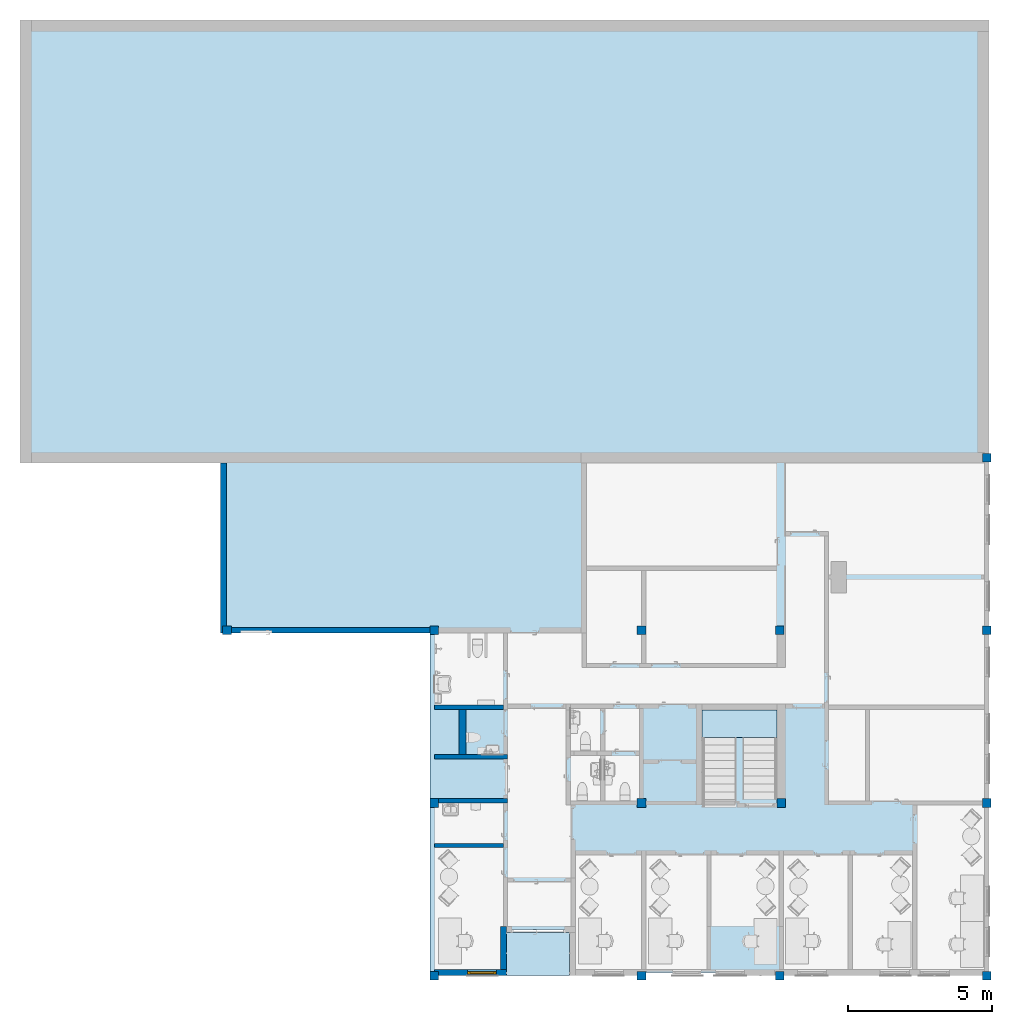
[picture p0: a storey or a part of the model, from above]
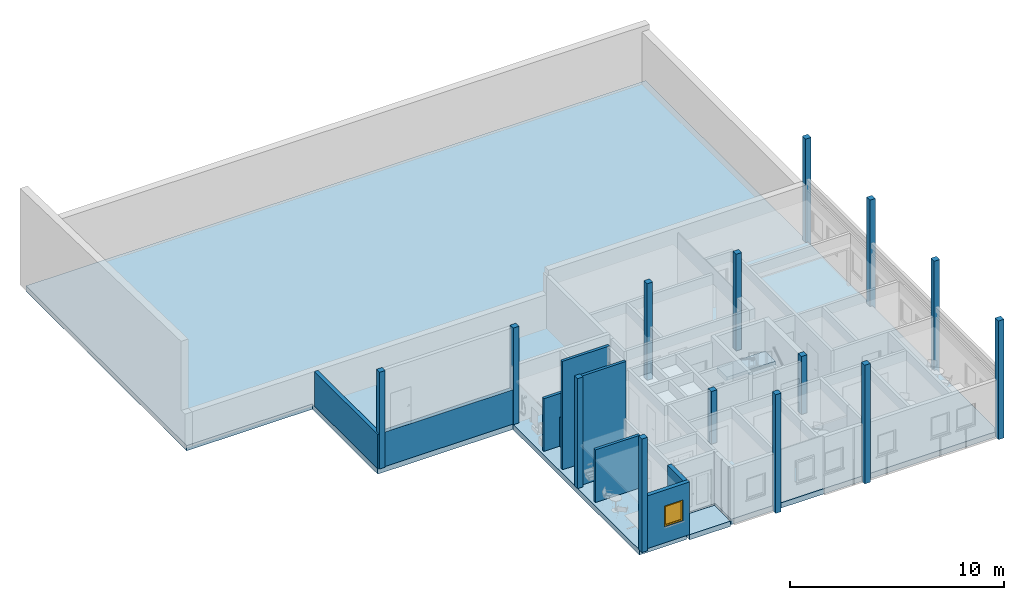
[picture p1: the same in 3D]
Properties of the parts of a building model (IFC2X3), part 1 of 4

# File
Description: ViewDefinition [CoordinationView_V2.0], RevitIdentifiers [ContentGUID: , VersionGUID: c2dd3010-3e74-4256-bd05-e16716eef5d8, NumberOfSaves: 1689], ExchangeRequirement [], CoordinateReference [CoordinateBase: Project Base Point, ProjectSite: Internal]
File name: A-200-00-ARK_TLV.ifc
Time: 2025-12-17T15:34:03+01:00
Organization: Arkitema
Written by: ODA SDAI 22.12
Made in: Autodesk Revit 23.1.80.30 (ENU) - IFC 23.4.1.0

# IfcProject, A271908
LongName: TROMSØ LEGEVAKT; Phase: SKISSEPROSJEKT

# IfcSite, Default
RefLatitude: 59, 54, 57, 599999; RefLongitude: 10, 44, 59, 999999; RefElevation: 0 mm

# IfcSite: Coordinate Marker Primary:Architect, Coordinate Marker Primary:Architect:1420675
Material: A_Coordinate Marker_ARC

# IfcBuilding
Pset_BuildingCommon - NumberOfStoreys: 8

# IfcBuildingStorey: Level:Trekant (8)
Pset_AirSideSystemInformation - sets with these values: 2
Name | LongName = Name | Elevation (mm)
OPPSTILLING | OPPSTILLING | -50000 | Pset_BuildingStoreyCommon - EntranceLevel: no
HAV | HAV | 6.71378e-11 | Pset_BuildingStoreyCommon - EntranceLevel: yes
PLAN U1 | PLAN U1 | 31140
PLAN 01 | PLAN 01 | 33100 | Pset_BuildingStoreyCommon - EntranceLevel: yes
PLAN 02 | PLAN 02 | 34440
TEKNISK SKILLE | TEKNISK SKILLE | 36090
PLAN 03 (EKS. TAK) | PLAN 03 (EKS. TAK) | 37100
PLAN 04 (TAK) | PLAN 04 (TAK) | 42000

# IfcSpace: Akuttrom 01 B4-407:1695459, B4-407
In: PLAN 01
LongName: Akuttrom 01; InteriorOrExteriorSpace: INTERNAL
Pset_AirSideSystemInformation - Name: Akuttrom 01; sets with these values: 2
Pset_SpaceCommon - Reference: Akuttrom 01 B4-407; FloorCovering: Vinyl, Halvledende; WallCovering: Baderomsplater; CeilingCovering: Perforert gipshimling

# IfcSpace: Akuttrom 02 B4-408:1695458, B4-408
In: PLAN 01
LongName: Akuttrom 02; InteriorOrExteriorSpace: INTERNAL
Pset_AirSideSystemInformation - Name: Akuttrom 02; sets with these values: 2
Pset_SpaceCommon - Reference: Akuttrom 02 B4-408; FloorCovering: Vinyl, Halvledende; WallCovering: Malt Gips; CeilingCovering: Systemhimling. hygiene

# IfcSpace: Ambulanse garasje B4-408A:1717682, B4-408A
In: PLAN 01
LongName: Ambulanse garasje; InteriorOrExteriorSpace: INTERNAL
Pset_AirSideSystemInformation - Name: Ambulanse garasje; sets with these values: 2
Pset_SpaceCommon - Reference: Ambulanse garasje B4-408A; FloorCovering: Epoxy / kjøresterk overflate; WallCovering: Platekledning; CeilingCovering: Støvbundet betong

# IfcSpace: Auditorie B5-306:1706835, B5-306
In: PLAN U1
LongName: Auditorie; InteriorOrExteriorSpace: INTERNAL
Pset_AirSideSystemInformation - Name: Auditorie; sets with these values: 2
Pset_SpaceCommon - Reference: Auditorie B5-306

# IfcSpace: Avfall 409:1706508, 409
In: PLAN 01
LongName: Avfall; InteriorOrExteriorSpace: INTERNAL
Pset_AirSideSystemInformation - Name: Avfall; sets with these values: 2
Pset_SpaceCommon - Reference: Avfall 409; FloorCovering: Epoxy; WallCovering: Malt Betong, våtromsmaling; CeilingCovering: Malt betong

# IfcSpace: Avklaringsrom B4-401:1695460, B4-401
In: PLAN 01
LongName: Avklaringsrom; InteriorOrExteriorSpace: INTERNAL
Pset_AirSideSystemInformation - Name: Avklaringsrom; sets with these values: 2
Pset_SpaceCommon - Reference: Avklaringsrom B4-401; FloorCovering: Vinyl; WallCovering: Malt Gips; CeilingCovering: Systemhimling. hygiene

# IfcSpace: BK. B5-302:1801416, B5-302
In: PLAN U1
LongName: BK.; InteriorOrExteriorSpace: INTERNAL
Pset_AirSideSystemInformation - Name: BK.; sets with these values: 2
Pset_SpaceCommon - Reference: BK. B5-302

# IfcSpace: BK. B5-413:1701542, B5-413
In: PLAN 02
LongName: BK.; InteriorOrExteriorSpace: INTERNAL
Pset_AirSideSystemInformation - Name: BK.; sets with these values: 2
Pset_SpaceCommon - Reference: BK. B5-413; FloorCovering: Vinyl; WallCovering: Malt Gips; CeilingCovering: Fast himling - våtromsmaling

# IfcSpace: Damegarderobe B5-421:2713467, B5-421
In: PLAN 02
LongName: Damegarderobe; InteriorOrExteriorSpace: INTERNAL
Pset_AirSideSystemInformation - Name: Damegarderobe; sets with these values: 2
Pset_SpaceCommon - Reference: Damegarderobe B5-421; FloorCovering: Vinyl; WallCovering: Malt Gips; CeilingCovering: Fast himling - våtromsmaling

# IfcSpace: Dusj B5-420B:2713472, B5-420B
In: PLAN 02
LongName: Dusj; InteriorOrExteriorSpace: INTERNAL
Pset_AirSideSystemInformation - Name: Dusj; sets with these values: 2
Pset_SpaceCommon - Reference: Dusj B5-420B; FloorCovering: Sklisikker Vinyl; WallCovering: Baderomsplater; CeilingCovering: Fast himling - våtromsmaling

# IfcSpace: Dusj B5-421B:2713502, B5-421B
In: PLAN 02
LongName: Dusj; InteriorOrExteriorSpace: INTERNAL
Pset_AirSideSystemInformation - Name: Dusj; sets with these values: 2
Pset_SpaceCommon - Reference: Dusj B5-421B; FloorCovering: Sklisikker Vinyl; WallCovering: Baderomsplater; CeilingCovering: Fast himling - våtromsmaling

# IfcSpace: EL Tavle B4-416A:1695467, B4-416A
In: PLAN 01
LongName: EL Tavle; InteriorOrExteriorSpace: INTERNAL
Pset_AirSideSystemInformation - Name: EL Tavle; sets with these values: 2
Pset_SpaceCommon - Reference: EL Tavle B4-416A

# IfcSpace: EL Tavle B5-309:1801423, B5-309
In: PLAN U1
LongName: EL Tavle; InteriorOrExteriorSpace: INTERNAL
Pset_AirSideSystemInformation - Name: EL Tavle; sets with these values: 2
Pset_SpaceCommon - Reference: EL Tavle B5-309

# IfcSpace: EL Tavle B5-312:1801425, B5-312
In: PLAN U1
LongName: EL Tavle; InteriorOrExteriorSpace: INTERNAL
Pset_AirSideSystemInformation - Name: EL Tavle; sets with these values: 2
Pset_SpaceCommon - Reference: EL Tavle B5-312

# IfcSpace: EL Tavle og UPS B4-414:1695468, B4-414
In: PLAN 01
LongName: EL Tavle og UPS; InteriorOrExteriorSpace: INTERNAL
Pset_AirSideSystemInformation - Name: EL Tavle og UPS; sets with these values: 2
Pset_SpaceCommon - Reference: EL Tavle og UPS B4-414; FloorCovering: Vinyl; WallCovering: Malt Gips; CeilingCovering: Systemhimling

# IfcSpace: Ekspedisjon/Sluse B4-425:2043666, B4-425
In: PLAN 01
LongName: Ekspedisjon/Sluse; InteriorOrExteriorSpace: INTERNAL
Pset_AirSideSystemInformation - Name: Ekspedisjon/Sluse; sets with these values: 2
Pset_SpaceCommon - Reference: Ekspedisjon/Sluse B4-425; FloorCovering: Vinyl; WallCovering: Malt Gips; CeilingCovering: Systemhimling

# IfcSpace: Ekspedisjon/Triage B4-425C:1734509, B4-425C
In: PLAN 01
LongName: Ekspedisjon/Triage; InteriorOrExteriorSpace: INTERNAL
Pset_AirSideSystemInformation - Name: Ekspedisjon/Triage; sets with these values: 2
Pset_SpaceCommon - Reference: Ekspedisjon/Triage B4-425C; FloorCovering: Vinyl; WallCovering: Malt Gips; CeilingCovering: Systemhimling

# IfcSpace: Felles Pauserom B5-422:1701539, B5-422
In: PLAN 02
LongName: Felles Pauserom; InteriorOrExteriorSpace: INTERNAL
Pset_AirSideSystemInformation - Name: Felles Pauserom; sets with these values: 2
Pset_SpaceCommon - Reference: Felles Pauserom B5-422; FloorCovering: Vinyl m trinnlydsdemping; WallCovering: Malt Gips; CeilingCovering: Treullsementplater montert UK dekke

# IfcSpace: Forrom B5-311:3232516, B5-311
In: PLAN U1
LongName: Forrom; InteriorOrExteriorSpace: INTERNAL
Pset_AirSideSystemInformation - Name: Forrom; sets with these values: 2
Pset_SpaceCommon - Reference: Forrom B5-311; FloorCovering: Vinyl; WallCovering: Malt Gips; CeilingCovering: Systemhimling

# IfcSpace: Forrom, smitte B5-409A:1837150, B5-409A
In: PLAN 01
LongName: Forrom, smitte; InteriorOrExteriorSpace: INTERNAL
Pset_AirSideSystemInformation - Name: Forrom, smitte; sets with these values: 2
Pset_SpaceCommon - Reference: Forrom, smitte B5-409A; FloorCovering: Vinyl; WallCovering: Malt Gips; CeilingCovering: Systemhimling. hygiene

# IfcSpace: Gang 410:1706509, 410
In: PLAN 01
LongName: Gang; InteriorOrExteriorSpace: INTERNAL
Pset_AirSideSystemInformation - Name: Gang; sets with these values: 2
Pset_SpaceCommon - Reference: Gang 410; FloorCovering: Vinyl; WallCovering: Malt Gips; CeilingCovering: Systemhimling

# IfcSpace: Gang:2708464
In: PLAN U1
LongName: Gang; InteriorOrExteriorSpace: INTERNAL
Pset_AirSideSystemInformation - Name: Gang; sets with these values: 2
Pset_SpaceCommon - Reference: Gang; FloorCovering: Nytt belegg i berørte områder (Vinyl); WallCovering: Males noe i berørte områder; CeilingCovering: Systemhimling tilpasses mot nye vegger

# IfcSpace: HC WC/dusj B4-411:1695466, B4-411
In: PLAN 01
LongName: HC WC/dusj; InteriorOrExteriorSpace: INTERNAL
Pset_AirSideSystemInformation - Name: HC WC/dusj; sets with these values: 2
Pset_SpaceCommon - Reference: HC WC/dusj B4-411; FloorCovering: Sklisikker Vinyl; WallCovering: Baderomsplater; CeilingCovering: Systemhimling. hygiene

# IfcSpace: HCWC B5-304:1805190, B5-304
In: PLAN U1
LongName: HCWC; InteriorOrExteriorSpace: INTERNAL
Pset_AirSideSystemInformation - Name: HCWC; sets with these values: 2
Pset_SpaceCommon - Reference: HCWC B5-304

# IfcSpace: HCWC/dusj B5-420:2713465, B5-420
In: PLAN 02
LongName: HCWC/dusj; InteriorOrExteriorSpace: INTERNAL
Pset_AirSideSystemInformation - Name: HCWC/dusj; sets with these values: 2
Pset_SpaceCommon - Reference: HCWC/dusj B5-420; FloorCovering: Sklisikker Vinyl; WallCovering: Baderomsplater; CeilingCovering: Fast himling - våtromsmaling

# IfcSpace: HCWC/stellerom B4-423:1697714, B4-423
In: PLAN 01
LongName: HCWC/stellerom; InteriorOrExteriorSpace: INTERNAL
Pset_AirSideSystemInformation - Name: HCWC/stellerom; sets with these values: 2
Pset_SpaceCommon - Reference: HCWC/stellerom B4-423; FloorCovering: Vinyl; WallCovering: Baderomsplater; CeilingCovering: Systemhimling

# IfcSpace: Heis 408:1706507, 408
In: PLAN 01
LongName: Heis; InteriorOrExteriorSpace: INTERNAL
Pset_AirSideSystemInformation - Name: Heis; sets with these values: 2
Pset_SpaceCommon - Reference: Heis 408

# IfcSpace: Herregarderobe B5-420:2713503, B5-420
In: PLAN 02
LongName: Herregarderobe; InteriorOrExteriorSpace: INTERNAL
Pset_AirSideSystemInformation - Name: Herregarderobe; sets with these values: 2
Pset_SpaceCommon - Reference: Herregarderobe B5-420; FloorCovering: Vinyl; WallCovering: Malt Gips; CeilingCovering: Fast himling - våtromsmaling

# IfcSpace: Hvilerom B5-405:2985970, B5-405
In: PLAN 02
LongName: Hvilerom; InteriorOrExteriorSpace: INTERNAL
Pset_AirSideSystemInformation - Name: Hvilerom; sets with these values: 2
Pset_SpaceCommon - Reference: Hvilerom B5-405; FloorCovering: Vinyl m trinnlydsdemping; WallCovering: Malt Gips; CeilingCovering: Systemhimling montert i UK. dekke

# IfcSpace: Interkommunal Legevaktsentral B5-421:1701530, B5-421
In: PLAN 02
LongName: Interkommunal Legevaktsentral; InteriorOrExteriorSpace: INTERNAL
Pset_AirSideSystemInformation - Name: Interkommunal Legevaktsentral; sets with these values: 2
Pset_SpaceCommon - Reference: Interkommunal Legevaktsentral B5-421; FloorCovering: Vinyl m trinnlydsdemping; WallCovering: Malt Gips; CeilingCovering: Treullsementplater montert UK dekke

# IfcSpace: Kontor B5-301:1801415, B5-301
In: PLAN U1
LongName: Kontor; InteriorOrExteriorSpace: INTERNAL
Pset_AirSideSystemInformation - Name: Kontor; sets with these values: 2
Pset_SpaceCommon - Reference: Kontor B5-301

# IfcSpace: Kontor B5-319:1801408, B5-319
In: PLAN U1
LongName: Kontor; InteriorOrExteriorSpace: INTERNAL
Pset_AirSideSystemInformation - Name: Kontor; sets with these values: 2
Pset_SpaceCommon - Reference: Kontor B5-319

# IfcSpace: Kontor B5-321:1801409, B5-321
In: PLAN U1
LongName: Kontor; InteriorOrExteriorSpace: INTERNAL
Pset_AirSideSystemInformation - Name: Kontor; sets with these values: 2
Pset_SpaceCommon - Reference: Kontor B5-321

# IfcSpace: Kontor B5-322:1801410, B5-322
In: PLAN U1
LongName: Kontor; InteriorOrExteriorSpace: INTERNAL
Pset_AirSideSystemInformation - Name: Kontor; sets with these values: 2
Pset_SpaceCommon - Reference: Kontor B5-322

# IfcSpace: Kontor B5-323:4452262, B5-323
In: PLAN U1
LongName: Kontor; InteriorOrExteriorSpace: INTERNAL
Pset_AirSideSystemInformation - Name: Kontor; sets with these values: 2
Pset_SpaceCommon - Reference: Kontor B5-323

# IfcSpace: Kontor B5-324:4452263, B5-324
In: PLAN U1
LongName: Kontor; InteriorOrExteriorSpace: INTERNAL
Pset_AirSideSystemInformation - Name: Kontor; sets with these values: 2
Pset_SpaceCommon - Reference: Kontor B5-324; FloorCovering: Nytt belegg i berørte områder (Vinyl); WallCovering: Malt Gips; CeilingCovering: systemhimling byttes i berørte områder

# IfcSpace: Kontor B5-326:4452264, B5-326
In: PLAN U1
LongName: Kontor; InteriorOrExteriorSpace: INTERNAL
Pset_AirSideSystemInformation - Name: Kontor; sets with these values: 2
Pset_SpaceCommon - Reference: Kontor B5-326

# IfcSpace: Kontor B5-403:2040337, B5-403
In: PLAN 02
LongName: Kontor; InteriorOrExteriorSpace: INTERNAL
Pset_AirSideSystemInformation - Name: Kontor; sets with these values: 2
Pset_SpaceCommon - Reference: Kontor B5-403; FloorCovering: Vinyl m trinnlydsdemping; WallCovering: Malt Gips; CeilingCovering: Systemhimling montert i UK. dekke

# IfcSpace: Kontor B5-408:1701536, B5-408
In: PLAN 02
LongName: Kontor; InteriorOrExteriorSpace: INTERNAL
Pset_AirSideSystemInformation - Name: Kontor; sets with these values: 2
Pset_SpaceCommon - Reference: Kontor B5-408; FloorCovering: Vinyl m trinnlydsdemping; WallCovering: Malt Gips; CeilingCovering: Systemhimling montert i UK. dekke

# IfcSpace: Kontor B5-409:1701532, B5-409
In: PLAN 02
LongName: Kontor; InteriorOrExteriorSpace: INTERNAL
Pset_AirSideSystemInformation - Name: Kontor; sets with these values: 2
Pset_SpaceCommon - Reference: Kontor B5-409; FloorCovering: Vinyl m trinnlydsdemping; WallCovering: Malt Gips; CeilingCovering: Systemhimling montert i UK. dekke

# IfcSpace: Kontor m. seng B5-406:1701538, B5-406
In: PLAN 02
LongName: Kontor m. seng; InteriorOrExteriorSpace: INTERNAL
Pset_AirSideSystemInformation - Name: Kontor m. seng; sets with these values: 2
Pset_SpaceCommon - Reference: Kontor m. seng B5-406; FloorCovering: Vinyl m trinnlydsdemping; WallCovering: Malt Gips; CeilingCovering: Systemhimling montert i UK. dekke

# IfcSpace: Kontor:2708261
In: PLAN U1
LongName: Kontor; InteriorOrExteriorSpace: INTERNAL
Pset_AirSideSystemInformation - Name: Kontor; sets with these values: 2
Pset_SpaceCommon - Reference: Kontor; FloorCovering: Vinyl; WallCovering: Malt Gips; CeilingCovering: Systemhimling tilpasses mot nye vegger

# IfcSpace: Kopirom B5-401:1801430, B5-401
In: PLAN U1
LongName: Kopirom; InteriorOrExteriorSpace: INTERNAL
Pset_AirSideSystemInformation - Name: Kopirom; sets with these values: 2
Pset_SpaceCommon - Reference: Kopirom B5-401

# IfcSpace: Kopirom/lager B5-303:1801418, B5-303
In: PLAN U1
LongName: Kopirom/lager; InteriorOrExteriorSpace: INTERNAL
Pset_AirSideSystemInformation - Name: Kopirom/lager; sets with these values: 2
Pset_SpaceCommon - Reference: Kopirom/lager B5-303

# IfcSpace: Korridor B4-002:1695457, B4-002
In: PLAN 01
LongName: Korridor; InteriorOrExteriorSpace: INTERNAL
Pset_AirSideSystemInformation - Name: Korridor; sets with these values: 2
Pset_SpaceCommon - Reference: Korridor B4-002; FloorCovering: Vinyl; WallCovering: Malt Gips; CeilingCovering: Systemhimling

# IfcSpace: Korridor B4-408B:2741082, B4-408B
In: PLAN 01
LongName: Korridor; InteriorOrExteriorSpace: INTERNAL
Pset_AirSideSystemInformation - Name: Korridor; sets with these values: 2
Pset_SpaceCommon - Reference: Korridor B4-408B; FloorCovering: Vinyl; WallCovering: Malt betong; CeilingCovering: Systemhimling

# IfcSpace: Korridor B4-419A:1706201, B4-419A
In: PLAN 01
LongName: Korridor; InteriorOrExteriorSpace: INTERNAL
Pset_AirSideSystemInformation - Name: Korridor; sets with these values: 2
Pset_SpaceCommon - Reference: Korridor B4-419A; FloorCovering: Vinyl; WallCovering: Malt Gips; CeilingCovering: Systemhimling

# IfcSpace: Korridor B4-424:1800888, B4-424
In: PLAN 01
LongName: Korridor; InteriorOrExteriorSpace: INTERNAL
Pset_AirSideSystemInformation - Name: Korridor; sets with these values: 2
Pset_SpaceCommon - Reference: Korridor B4-424; FloorCovering: Vinyl; WallCovering: Malt Gips; CeilingCovering: Treullsementplater

# IfcSpace: Korridor B5-318:4452265, B5-318
In: PLAN U1
LongName: Korridor; InteriorOrExteriorSpace: INTERNAL
Pset_AirSideSystemInformation - Name: Korridor; sets with these values: 2
Pset_SpaceCommon - Reference: Korridor B5-318; FloorCovering: Nytt belegg i berørte områder (Vinyl); WallCovering: Males noe i berørte områder; CeilingCovering: systemhimling byttes i berørte områder

# IfcSpace: Korridor B5-320:4929273, B5-320
In: PLAN 01
LongName: Korridor; InteriorOrExteriorSpace: INTERNAL
Pset_AirSideSystemInformation - Name: Korridor; sets with these values: 2
Pset_SpaceCommon - Reference: Korridor B5-320; FloorCovering: Vinyl; WallCovering: Malt Gips; CeilingCovering: Treullsementplater

# IfcSpace: Korridor B5-402:1940733, B5-402
In: PLAN 02
LongName: Korridor; InteriorOrExteriorSpace: INTERNAL
Pset_AirSideSystemInformation - Name: Korridor; sets with these values: 2
Pset_SpaceCommon - Reference: Korridor B5-402; FloorCovering: Vinyl m trinnlydsdemping; WallCovering: Malt Gips; CeilingCovering: Treullsementplater montert UK dekke

# IfcSpace: Korridor:1801431
In: PLAN U1
LongName: Korridor; InteriorOrExteriorSpace: INTERNAL
Pset_AirSideSystemInformation - Name: Korridor; sets with these values: 2
Pset_SpaceCommon - Reference: Korridor; WallCovering: Males noe i berørte områder; CeilingCovering: Systemhimling tilpasses mot nye vegger

# IfcSpace: Lab. B4-417A:1695430, B4-417A
In: PLAN 01
LongName: Lab.; InteriorOrExteriorSpace: INTERNAL
Pset_AirSideSystemInformation - Name: Lab.; sets with these values: 2
Pset_SpaceCommon - Reference: Lab. B4-417A; FloorCovering: Vinyl; WallCovering: Malt Gips; CeilingCovering: Systemhimling. hygiene

# IfcSpace: Lager B4-409:2512479, B4-409
In: PLAN 01
LongName: Lager; InteriorOrExteriorSpace: INTERNAL
Pset_AirSideSystemInformation - Name: Lager; sets with these values: 2
Pset_SpaceCommon - Reference: Lager B4-409; FloorCovering: Vinyl; WallCovering: Malt Gips; CeilingCovering: Systemhimling

# IfcSpace: Lager B4-412:1922391, B4-412
In: PLAN 01
LongName: Lager; InteriorOrExteriorSpace: INTERNAL
Pset_AirSideSystemInformation - Name: Lager; sets with these values: 2
Pset_SpaceCommon - Reference: Lager B4-412; FloorCovering: Vinyl; WallCovering: Malt Gips; CeilingCovering: Systemhimling

# IfcSpace: Lager B4-419B:2564856, B4-419B
In: PLAN 01
LongName: Lager; InteriorOrExteriorSpace: INTERNAL
Pset_AirSideSystemInformation - Name: Lager; sets with these values: 2
Pset_SpaceCommon - Reference: Lager B4-419B; FloorCovering: Vinyl; WallCovering: Malt Gips; CeilingCovering: Systemhimling

# IfcSpace: Lager B5-417:2039801, B5-417
In: PLAN 02
LongName: Lager; InteriorOrExteriorSpace: INTERNAL
Pset_AirSideSystemInformation - Name: Lager; sets with these values: 2
Pset_SpaceCommon - Reference: Lager B5-417; FloorCovering: Vinyl; WallCovering: Malt Gips; CeilingCovering: Malt betong

# IfcSpace: Lager Nisje B4-404B:2099752, B4-404B
In: PLAN 01
LongName: Lager Nisje; InteriorOrExteriorSpace: INTERNAL
Pset_AirSideSystemInformation - Name: Lager Nisje; sets with these values: 2
Pset_SpaceCommon - Reference: Lager Nisje B4-404B; FloorCovering: Vinyl; WallCovering: Malt Gips; CeilingCovering: Systemhimling

# IfcSpace: Lager Nisje B4-422B:2104934, B4-422B
In: PLAN 01
LongName: Lager Nisje; InteriorOrExteriorSpace: INTERNAL
Pset_AirSideSystemInformation - Name: Lager Nisje; sets with these values: 2
Pset_SpaceCommon - Reference: Lager Nisje B4-422B; FloorCovering: Vinyl; WallCovering: Malt Gips; CeilingCovering: Systemhimling

# IfcSpace: Lager Tøy B4-403B:1757750, B4-403B
In: PLAN 01
LongName: Lager Tøy; InteriorOrExteriorSpace: INTERNAL
Pset_AirSideSystemInformation - Name: Lager Tøy; sets with these values: 2
Pset_SpaceCommon - Reference: Lager Tøy B4-403B; FloorCovering: Vinyl; WallCovering: Malt Gips; CeilingCovering: Systemhimling

# IfcSpace: Løfteplattform B5-414:1705806, B5-414
In: PLAN 02
LongName: Løfteplattform; InteriorOrExteriorSpace: INTERNAL
Pset_AirSideSystemInformation - Name: Løfteplattform; sets with these values: 2
Pset_SpaceCommon - Reference: Løfteplattform B5-414; FloorCovering: Malt betong; WallCovering: Støvbundet betong; CeilingCovering: Støvbundet betong

# IfcSpace: Medisinrom B4-407B:1756223, B4-407B
In: PLAN 01
LongName: Medisinrom; InteriorOrExteriorSpace: INTERNAL
Pset_AirSideSystemInformation - Name: Medisinrom; sets with these values: 2
Pset_SpaceCommon - Reference: Medisinrom B4-407B; FloorCovering: Vinyl; WallCovering: Malt Gips; CeilingCovering: Systemhimling

# IfcSpace: Møterom B5-307:1801420, B5-307
In: PLAN U1
LongName: Møterom; InteriorOrExteriorSpace: INTERNAL
Pset_AirSideSystemInformation - Name: Møterom; sets with these values: 2
Pset_SpaceCommon - Reference: Møterom B5-307

# IfcSpace: Møterom B5-313:1801426, B5-313
In: PLAN U1
LongName: Møterom; InteriorOrExteriorSpace: INTERNAL
Pset_AirSideSystemInformation - Name: Møterom; sets with these values: 2
Pset_SpaceCommon - Reference: Møterom B5-313

# IfcSpace: Møterom B5-314:1801406, B5-314
In: PLAN U1
LongName: Møterom; InteriorOrExteriorSpace: INTERNAL
Pset_AirSideSystemInformation - Name: Møterom; sets with these values: 2
Pset_SpaceCommon - Reference: Møterom B5-314

# IfcSpace: Møterom B5-317:3502699, B5-317
In: PLAN U1
LongName: Møterom; InteriorOrExteriorSpace: INTERNAL
Pset_AirSideSystemInformation - Name: Møterom; sets with these values: 2
Pset_SpaceCommon - Reference: Møterom B5-317

# IfcSpace: Møterom B5-412:1701531, B5-412
In: PLAN 02
LongName: Møterom; InteriorOrExteriorSpace: INTERNAL
Pset_AirSideSystemInformation - Name: Møterom; sets with these values: 2
Pset_SpaceCommon - Reference: Møterom B5-412; FloorCovering: Vinyl m trinnlydsdemping; WallCovering: Malt Gips; CeilingCovering: Systemhimling montert i UK. dekke

# IfcSpace: Oppbevaring O2:2806572
In: PLAN 01
LongName: Oppbevaring O2; InteriorOrExteriorSpace: INTERNAL
Pset_AirSideSystemInformation - Name: Oppbevaring O2; sets with these values: 2
Pset_SpaceCommon - Reference: Oppbevaring O2; FloorCovering: Epoxy / kjøresterk overflate; WallCovering: Platekledning; CeilingCovering: Støvbundet betong

# IfcSpace: Prøvetaking B4-417:1695433, B4-417
In: PLAN 01
LongName: Prøvetaking; InteriorOrExteriorSpace: INTERNAL
Pset_AirSideSystemInformation - Name: Prøvetaking; sets with these values: 2
Pset_SpaceCommon - Reference: Prøvetaking B4-417; FloorCovering: Vinyl; WallCovering: Malt Gips; CeilingCovering: Systemhimling. hygiene

# IfcSpace: Renhold B4-413:1712593, B4-413
In: PLAN 01
LongName: Renhold; InteriorOrExteriorSpace: INTERNAL
Pset_AirSideSystemInformation - Name: Renhold; sets with these values: 2
Pset_SpaceCommon - Reference: Renhold B4-413; FloorCovering: Vinyl; WallCovering: Malt Gips, våtromsmaling; CeilingCovering: Systemhimling. hygiene

# IfcSpace: Skyllerom B4-412:1695534, B4-412
In: PLAN 01
LongName: Skyllerom; InteriorOrExteriorSpace: INTERNAL
Pset_AirSideSystemInformation - Name: Skyllerom; sets with these values: 2
Pset_SpaceCommon - Reference: Skyllerom B4-412; FloorCovering: Vinyl; WallCovering: Malt Gips, våtromsmaling; CeilingCovering: Systemhimling. hygiene

# IfcSpace: Sosial sone B5-416:1940722, B5-416
In: PLAN 02
LongName: Sosial sone; InteriorOrExteriorSpace: INTERNAL
Pset_AirSideSystemInformation - Name: Sosial sone; sets with these values: 2
Pset_SpaceCommon - Reference: Sosial sone B5-416; FloorCovering: Vinyl m trinnlydsdemping; WallCovering: Malt Gips; CeilingCovering: Treullsementplater montert UK dekke

# IfcSpace: Tekn. rom /KR B5-418:2712851, B5-418
In: PLAN 02
LongName: Tekn. rom /KR; InteriorOrExteriorSpace: INTERNAL
Pset_AirSideSystemInformation - Name: Tekn. rom /KR; sets with these values: 2
Pset_SpaceCommon - Reference: Tekn. rom /KR B5-418; FloorCovering: Antistatisk vinyl; WallCovering: Malt Gips; CeilingCovering: Malt betong

# IfcSpace: Tekn. rom B5-418A:1701546, B5-418A
In: PLAN 02
LongName: Tekn. rom; InteriorOrExteriorSpace: INTERNAL
Pset_AirSideSystemInformation - Name: Tekn. rom; sets with these values: 2
Pset_SpaceCommon - Reference: Tekn. rom B5-418A; FloorCovering: Eksisterende vinyl; WallCovering: Malt Gips; CeilingCovering: Malt betong

# IfcSpace: Teknisk rom B4-416:1695456, B4-416
In: PLAN 01
LongName: Teknisk rom; InteriorOrExteriorSpace: INTERNAL
Pset_AirSideSystemInformation - Name: Teknisk rom; sets with these values: 2
Pset_SpaceCommon - Reference: Teknisk rom B4-416; FloorCovering: Epoxy

# IfcSpace: Trapp B5-415:2567414, B5-415
In: PLAN 02
LongName: Trapp; InteriorOrExteriorSpace: INTERNAL
Pset_AirSideSystemInformation - Name: Trapp; sets with these values: 2
Pset_SpaceCommon - Reference: Trapp B5-415; FloorCovering: Vinyl m trinnlydsdemping; WallCovering: Malt Gips; CeilingCovering: Treullsementplater montert UK dekke

# IfcSpace: Trapperom B5-401:2746336, B5-401
In: PLAN 02
LongName: Trapperom; InteriorOrExteriorSpace: INTERNAL
Pset_AirSideSystemInformation - Name: Trapperom; sets with these values: 2
Pset_SpaceCommon - Reference: Trapperom B5-401

# IfcSpace: Trapperom:2941036
In: PLAN U1
LongName: Trapperom; InteriorOrExteriorSpace: INTERNAL
Pset_AirSideSystemInformation - Name: Trapperom; sets with these values: 2
Pset_SpaceCommon - Reference: Trapperom; WallCovering: Males noe i berørte områder

# IfcSpace: Triage B4-425B:1695436, B4-425B
In: PLAN 01
LongName: Triage; InteriorOrExteriorSpace: INTERNAL
Pset_AirSideSystemInformation - Name: Triage; sets with these values: 2
Pset_SpaceCommon - Reference: Triage B4-425B; FloorCovering: Vinyl; WallCovering: Malt Gips; CeilingCovering: Systemhimling. hygiene

# IfcSpace: Undersøkelse, behandlingsrom B4-403:1695461, B4-403
In: PLAN 01
LongName: Undersøkelse, behandlingsrom; InteriorOrExteriorSpace: INTERNAL
Pset_AirSideSystemInformation - Name: Undersøkelse, behandlingsrom; sets with these values: 2
Pset_SpaceCommon - Reference: Undersøkelse, behandlingsrom B4-403; FloorCovering: Vinyl; WallCovering: Malt Gips; CeilingCovering: Systemhimling. hygiene

# IfcSpace: Undersøkelse, behandlingsrom B4-404:1695462, B4-404
In: PLAN 01
LongName: Undersøkelse, behandlingsrom; InteriorOrExteriorSpace: INTERNAL
Pset_AirSideSystemInformation - Name: Undersøkelse, behandlingsrom; sets with these values: 2
Pset_SpaceCommon - Reference: Undersøkelse, behandlingsrom B4-404; FloorCovering: Vinyl; WallCovering: Malt Gips; CeilingCovering: Systemhimling. hygiene

# IfcSpace: Undersøkelse, behandlingsrom B4-406:1695463, B4-406
In: PLAN 01
LongName: Undersøkelse, behandlingsrom; InteriorOrExteriorSpace: INTERNAL
Pset_AirSideSystemInformation - Name: Undersøkelse, behandlingsrom; sets with these values: 2
Pset_SpaceCommon - Reference: Undersøkelse, behandlingsrom B4-406; FloorCovering: Vinyl; WallCovering: Malt Gips; CeilingCovering: Systemhimling. hygiene

# IfcSpace: Undersøkelse, behandlingsrom B5-409:1695464, B5-409
In: PLAN 01
LongName: Undersøkelse, behandlingsrom; InteriorOrExteriorSpace: INTERNAL
Pset_AirSideSystemInformation - Name: Undersøkelse, behandlingsrom; sets with these values: 2
Pset_SpaceCommon - Reference: Undersøkelse, behandlingsrom B5-409; FloorCovering: Vinyl; WallCovering: Malt Gips; CeilingCovering: Systemhimling. hygiene

# IfcSpace: Uteplass:2806164
In: PLAN 01
LongName: Uteplass; InteriorOrExteriorSpace: INTERNAL
Pset_AirSideSystemInformation - Name: Uteplass; sets with these values: 2
Pset_SpaceCommon - Reference: Uteplass

# IfcSpace: Vaktrom B4-425A:1695445, B4-425A
In: PLAN 01
LongName: Vaktrom; InteriorOrExteriorSpace: INTERNAL
Pset_AirSideSystemInformation - Name: Vaktrom; sets with these values: 2
Pset_SpaceCommon - Reference: Vaktrom B4-425A; FloorCovering: Vinyl; WallCovering: Malt Gips; CeilingCovering: Systemhimling

# IfcSpace: Vaskerom B5-419:2713466, B5-419
In: PLAN 02
LongName: Vaskerom; InteriorOrExteriorSpace: INTERNAL
Pset_AirSideSystemInformation - Name: Vaskerom; sets with these values: 2
Pset_SpaceCommon - Reference: Vaskerom B5-419; FloorCovering: Vinyl; WallCovering: Malt Gips, våtromsmaling; CeilingCovering: Fast himling - våtromsmaling

# IfcSpace: Venterom B4-010:1833794, B4-010
In: PLAN 01
LongName: Venterom; InteriorOrExteriorSpace: INTERNAL
Pset_AirSideSystemInformation - Name: Venterom; sets with these values: 2
Pset_SpaceCommon - Reference: Venterom B4-010; FloorCovering: Vinyl; WallCovering: Malt Gips; CeilingCovering: Systemhimling

# IfcSpace: Venterom B4-401A:2564837, B4-401A
In: PLAN 01
LongName: Venterom; InteriorOrExteriorSpace: INTERNAL
Pset_AirSideSystemInformation - Name: Venterom; sets with these values: 2
Pset_SpaceCommon - Reference: Venterom B4-401A; FloorCovering: Vinyl; WallCovering: Malt Gips; CeilingCovering: Systemhimling

# IfcSpace: Venterom B4-424B:1695455, B4-424B
In: PLAN 01
LongName: Venterom; InteriorOrExteriorSpace: INTERNAL
Pset_AirSideSystemInformation - Name: Venterom; sets with these values: 2
Pset_SpaceCommon - Reference: Venterom B4-424B; FloorCovering: Vinyl; WallCovering: Malt Gips; CeilingCovering: Treullsementplater

# IfcSpace: Vindfang B4-001:4286111, B4-001
In: PLAN 01
LongName: Vindfang; InteriorOrExteriorSpace: INTERNAL
Pset_AirSideSystemInformation - Name: Vindfang; sets with these values: 2
Pset_SpaceCommon - Reference: Vindfang B4-001; FloorCovering: Fliser; WallCovering: Malt Gips; CeilingCovering: Treullsementplater

# IfcSpace: Vindfang:1801414
In: PLAN U1
LongName: Vindfang; InteriorOrExteriorSpace: INTERNAL
Pset_AirSideSystemInformation - Name: Vindfang; sets with these values: 2
Pset_SpaceCommon - Reference: Vindfang

# IfcSpace: WC B4-422:1698915, B4-422
In: PLAN 01
LongName: WC; InteriorOrExteriorSpace: INTERNAL
Pset_AirSideSystemInformation - Name: WC; sets with these values: 2
Pset_SpaceCommon - Reference: WC B4-422; FloorCovering: Vinyl; WallCovering: Baderomsplater; CeilingCovering: Systemhimling

# IfcSpace: WC B5-303:1939560, B5-303
In: PLAN U1
LongName: WC; InteriorOrExteriorSpace: INTERNAL
Pset_AirSideSystemInformation - Name: WC; sets with these values: 2
Pset_SpaceCommon - Reference: WC B5-303; FloorCovering: Vinyl; WallCovering: Malt Gips; CeilingCovering: Malt Gips

# IfcSpace: WC B5-311A:1801427, B5-311A
In: PLAN U1
LongName: WC; InteriorOrExteriorSpace: INTERNAL
Pset_AirSideSystemInformation - Name: WC; sets with these values: 2
Pset_SpaceCommon - Reference: WC B5-311A; WallCovering: Malt Gips; CeilingCovering: Systemhimling

# IfcSpace: WC B5-311B:1801428, B5-311B
In: PLAN U1
LongName: WC; InteriorOrExteriorSpace: INTERNAL
Pset_AirSideSystemInformation - Name: WC; sets with these values: 2
Pset_SpaceCommon - Reference: WC B5-311B; FloorCovering: Vinyl; WallCovering: Malt Gips; CeilingCovering: Systemhimling

# IfcSpace: WC B5-420A:2713471, B5-420A
In: PLAN 02
LongName: WC; InteriorOrExteriorSpace: INTERNAL
Pset_AirSideSystemInformation - Name: WC; sets with these values: 2
Pset_SpaceCommon - Reference: WC B5-420A; FloorCovering: Vinyl; WallCovering: Baderomsplater; CeilingCovering: Fast himling - våtromsmaling

# IfcSpace: WC B5-420A:2713473, B5-420A
In: PLAN 02
LongName: WC; InteriorOrExteriorSpace: INTERNAL
Pset_AirSideSystemInformation - Name: WC; sets with these values: 2
Pset_SpaceCommon - Reference: WC B5-420A; FloorCovering: Vinyl; WallCovering: Baderomsplater; CeilingCovering: Fast himling - våtromsmaling

# IfcSpace: WC:4167080
In: PLAN U1
LongName: WC; InteriorOrExteriorSpace: INTERNAL
Pset_AirSideSystemInformation - Name: WC; sets with these values: 2
Pset_SpaceCommon - Reference: WC; FloorCovering: Vinyl; WallCovering: Malt Gips; CeilingCovering: Systemhimling

# IfcBuildingElementProxy: 012.013-Blodtrykksapparat:Blodtrykksapparat, elektronisk, med pulsokymeter, 012.013-Blodtrykksapparat:Blodtrykksapparat, elektronisk, med pulsokymeter:4877518
In: B4-425B
Type - Material: <Unnamed>
Pset_BuildingElementProxyCommon - Reference: Blodtrykksapparat, elektronisk, med pulsokymeter; sets with these values: 2

# IfcBuildingElementProxy: 012_02_003-Lampe_operasjon_100 000 lux:Operasjonslampe (2)
Type - Material: <Unnamed>
Pset_BuildingElementProxyCommon - Reference: Operasjonslampe; sets with these values: 2
Name (012_02_003-Lampe_operasjon_100 000 lux:Operasjonslampe:...) | In
2418147 | B4-408
4878788 | B4-407

# IfcBuildingElementProxy: 031-020-Akuttvogn med skuffer:Akutttralle, 031-020-Akuttvogn med skuffer:Akutttralle:4824039
In: B4-425A
Type - Material: <Unnamed>
Pset_BuildingElementProxyCommon - Reference: Akutttralle; sets with these values: 2

# IfcBuildingElementProxy: 090.016-Makuleringsmaskin:Makuleringsmaskin, 090.016-Makuleringsmaskin:Makuleringsmaskin:2425658
In: B5-402
Type - Material: <Unnamed>
Pset_BuildingElementProxyCommon - Reference: Makuleringsmaskin; sets with these values: 2

# IfcBuildingElementProxy: 490_01_018-KK3701_Back_up_kanal_operasjon:Sykeromskanal_Vertikal (2)
Type - Material: <Unnamed>
Pset_BuildingElementProxyCommon - Reference: Sykeromskanal_Vertikal; sets with these values: 2
Name (490_01_018-KK3701_Back_up_kanal_operasjon:Sykeromskanal_Vertikal:...) | In
4906728 | B4-406
4906935 | B4-404

# IfcBuildingElementProxy: 660_04_185-El_kanal_m_lys_vegghengt:Sykeromskanal Horisontal (2)
Type - Material: <Unnamed>
Pset_BuildingElementProxyCommon - Reference: Sykeromskanal Horisontal; sets with these values: 2
Name (660_04_185-El_kanal_m_lys_vegghengt:Sykeromskanal Horisontal:...) | In
4901323 | B4-407
4907012 | B4-408

# IfcBuildingElementProxy: Avfallsbeholder:Avfallsbøtte med hjul (7)
Type - Material: <Unnamed>, Metall
Pset_BuildingElementProxyCommon - Reference: Avfallsbøtte med hjul; sets with these values: 2
Name (Avfallsbeholder:Avfallsbøtte med hjul:...) | In
4585392 | B4-407
4585874 | B4-408
4585990 | B4-406
4586014 | B4-404
4586038 | B4-403
4645027 | B4-425C
4687270 | B5-409

# IfcBuildingElementProxy: Benkebelysning LED:Benkebelysning LED (3)
Type - Material: <Unnamed>
Pset_BuildingElementProxyCommon - Reference: Benkebelysning LED; sets with these values: 2
Name (Benkebelysning LED:Benkebelysning LED:...) | In
4904861 | B4-407
4907594 | B4-408
4937859 | B4-403

# IfcBuildingElementProxy: Båre:Båre, akutt (4)
Type - Material: <Unnamed>
Pset_BuildingElementProxyCommon - Reference: Båre, akutt; sets with these values: 2
Name (Båre:Båre, akutt:...) | In
1728677 | B4-408
1728794 | B4-407
1937154 | B4-401
2554737 | B4-425B

# IfcBuildingElementProxy: Båre:Båre, bariatrisk, Båre:Båre, bariatrisk:1727363
In: B4-401
Type - Material: <Unnamed>
Pset_BuildingElementProxyCommon - Reference: Båre, bariatrisk; sets with these values: 2

# IfcBuildingElementProxy: CAR_Person car B_5 km-t:Legvaktsbil, CAR_Person car B_5 km-t:Legvaktsbil:2114667
In: PLAN 01
Type - Material: Rubber, Painted_ShadowBlack, Painted_BlueJeans_Metallic, Glazing_DarkGrey
Pset_BuildingElementProxyCommon - Reference: Legvaktsbil; sets with these values: 2

# IfcBuildingElementProxy: Dekontaminator:Dekontaminator_spyl_enkel_desinf, Dekontaminator:Dekontaminator_spyl_enkel_desinf:2419850
In: B4-412
Type - Material: <Unnamed>
Pset_BuildingElementProxyCommon - Reference: Dekontaminator_spyl_enkel_desinf; sets with these values: 2

# IfcBuildingElementProxy: El_kanal_vegghengt:Elkanal (10)
Type - Material: <Unnamed>
Pset_BuildingElementProxyCommon - Reference: Elkanal; sets with these values: 2
Name (El_kanal_vegghengt:Elkanal:...) | In
4904075 | B4-407
4907452 | B4-408
4929402 | B4-403
4929614 | B4-403
4929854 | B4-403
4930153 | B4-407
4930442 | B5-409
4934603 | B4-417
4934865 | B4-417A
4934875 | B4-412

# IfcBuildingElementProxy: Enscape AssetDefinition - Ambulance 001:Ambulanse, Enscape AssetDefinition - Ambulance 001:Ambulanse:2114665
In: B4-408A
Type - Material: <Unnamed>
Pset_BuildingElementProxyCommon - Reference: Ambulanse; sets with these values: 2

# IfcBuildingElementProxy: Fallsikring:Fallsikring (58)
In: PLAN 04 (TAK)
Type - Material: <Unnamed>
Pset_BuildingElementProxyCommon - Reference: Fallsikring; sets with these values: 2
Name (Fallsikring:Fallsikring:...)
3473098
3473319
3473415
3473421
3473429
3473533
3473534
3473535
3473536
3473604
3473605
3473606
3473607
3473613
3473614
3473615
3473616
3473624
3473625
3473626
3473627
3473636
3473637
3473766
3473788
3473796
3473804
3474338
3474461
3477048
3477056
3477064
3477205
3477213
3477286
3479202
3479295
3479303
3479311
3479349
3479350
3479351
3479357
3479358
3479359
3479367
3479368
3479369
3479599
3479600
3479601
3479602
3479612
3479613
3479614
3479615
3479626
3479627

# IfcBuildingElementProxy: Fasade profil, HOR:Fasade profil 100x50 (74)
Type - Material: Aluminum
Pset_BuildingElementProxyCommon - Reference: Fasade profil 100x50; sets with these values: 2
Name (Fasade profil, HOR:Fasade profil 100x50:...) | In
3268012 | PLAN 01
3268300 | PLAN 02
3268347 | PLAN 01
3268348 | PLAN 02
3268357 | PLAN 01
3268358 | PLAN 02
3268582 | PLAN 01
3268583 | PLAN 02
3269045 | TEKNISK SKILLE
3269114 | TEKNISK SKILLE
3269146 | PLAN 02
3269147 | PLAN 02
3269209 | TEKNISK SKILLE
3269210 | PLAN 02
3269223 | TEKNISK SKILLE
3269224 | PLAN 02
3269235 | TEKNISK SKILLE
3269236 | PLAN 02
3269251 | TEKNISK SKILLE
3269252 | PLAN 02
3269263 | TEKNISK SKILLE
3269264 | PLAN 02
3269273 | PLAN 01
3269274 | PLAN U1
3269388 | PLAN 01
3269389 | PLAN U1
3269424 | PLAN 01
3269425 | PLAN U1
3269450 | PLAN 01
3269451 | PLAN U1
3269462 | PLAN 01
3269463 | PLAN U1
3269476 | PLAN 01
3269477 | PLAN U1
3269563 | PLAN 01
3270055 | TEKNISK SKILLE
3270056 | PLAN 02
3270057 | PLAN 01
3270058 | PLAN U1
3270383 | PLAN 01
3270384 | PLAN U1
3270395 | TEKNISK SKILLE
3270396 | PLAN 02
3270409 | TEKNISK SKILLE
3270410 | PLAN 02
3270419 | TEKNISK SKILLE
3270420 | PLAN 02
3270433 | TEKNISK SKILLE
3270434 | PLAN 02
3270445 | TEKNISK SKILLE
3270446 | PLAN 02
3270457 | TEKNISK SKILLE
3270458 | PLAN 02
3270467 | TEKNISK SKILLE
3270468 | PLAN 02
3270477 | PLAN 01
3270478 | PLAN U1
3270487 | PLAN 01
3270488 | PLAN U1
3270499 | PLAN 01
3270500 | PLAN U1
3270509 | PLAN 01
3270510 | PLAN U1
3270519 | PLAN 01
3270520 | PLAN U1
3270531 | PLAN 01
3270532 | PLAN U1
3271530 | PLAN 01
3271727 | PLAN 02
3272196 | PLAN 01
4452269 | PLAN 01
4452270 | PLAN U1
4531708 | TEKNISK SKILLE
4531709 | PLAN 02

# IfcBuildingElementProxy: Fasade profil, VER:Fasade profil 100x50 (341)
Type - Material: Aluminum
Pset_BuildingElementProxyCommon - Reference: Fasade profil 100x50; sets with these values: 2
Name (Fasade profil, VER:Fasade profil 100x50:...) | In
2393034 | PLAN 01
2394160 | PLAN 01
2394266 | PLAN 01
2394510 | PLAN 01
2394530 | PLAN 01
2394625 | PLAN 01
2394690 | PLAN 01
2394698 | PLAN 01
2394781 | PLAN 01
2394832 | PLAN 01
2395017 | PLAN 01
2395167 | PLAN 01
2395178 | PLAN 01
2395286 | PLAN 01
2395419 | PLAN 01
2395523 | PLAN 01
2395524 | PLAN 01
2395525 | PLAN 01
2395527 | PLAN 01
2395528 | PLAN 01
2395530 | PLAN 01
2395531 | PLAN 01
2395544 | PLAN 01
2396640 | PLAN 01
2396641 | PLAN 01
2397020 | PLAN 01
2397291 | PLAN 01
2397411 | PLAN 01
2397906 | PLAN 01
2397984 | PLAN 01
2398217 | PLAN 01
2398265 | PLAN 01
2398295 | PLAN 01
2398328 | PLAN 01
2398340 | PLAN 01
2398389 | PLAN 01
2398669 | PLAN 01
2398997 | PLAN 01
2399015 | PLAN 01
2399176 | PLAN 01
2399476 | PLAN 01
2399811 | PLAN 01
2400050 | PLAN 01
2400256 | PLAN 02
2400349 | PLAN 01
2400642 | PLAN 03 (EKS. TAK)
2400854 | PLAN 01
2401374 | PLAN 01
2401691 | PLAN 01
2401977 | PLAN U1
2402091 | PLAN 03 (EKS. TAK)
2402179 | PLAN 03 (EKS. TAK)
2402193 | PLAN 01
2402195 | PLAN U1
2402197 | PLAN 03 (EKS. TAK)
2402213 | PLAN 01
2402217 | PLAN 03 (EKS. TAK)
2402229 | PLAN 01
2402233 | PLAN 03 (EKS. TAK)
2402569 | PLAN 01
2402660 | PLAN 01
2402874 | PLAN 01
2404548 | PLAN 01
2404668 | PLAN 01
2404699 | PLAN 01
2404755 | PLAN 01
2404793 | PLAN 01
2404803 | PLAN 01
2404813 | PLAN 01
2404853 | PLAN 01
2404896 | PLAN 01
2404916 | PLAN 01
2404926 | PLAN 01
2404936 | PLAN 01
2404987 | PLAN 01
2405031 | PLAN 01
2405041 | PLAN 01
2405098 | PLAN 01
2405131 | PLAN 01
2405165 | PLAN 01
2405459 | PLAN 01
2405568 | PLAN 01
2405610 | PLAN 01
2405617 | PLAN 01
2405634 | PLAN 01
2405762 | PLAN 01
2405771 | PLAN 01
2405782 | PLAN 01
2405842 | PLAN 03 (EKS. TAK)
2406079 | PLAN 03 (EKS. TAK)
2406094 | PLAN 03 (EKS. TAK)
2406105 | PLAN 03 (EKS. TAK)
2406116 | PLAN 03 (EKS. TAK)
2406125 | PLAN 03 (EKS. TAK)
2406134 | PLAN 03 (EKS. TAK)
2406145 | PLAN 03 (EKS. TAK)
2406219 | PLAN 04 (TAK)
2406294 | PLAN 04 (TAK)
2406362 | PLAN 04 (TAK)
2406373 | PLAN 04 (TAK)
2406386 | PLAN 04 (TAK)
2406395 | PLAN 04 (TAK)
2406404 | PLAN 04 (TAK)
2406415 | PLAN 04 (TAK)
2406711 | PLAN 03 (EKS. TAK)
2406890 | PLAN 01
2406900 | PLAN 01
2406946 | PLAN 01
2407007 | PLAN 01
2409231 | PLAN 01
2409455 | PLAN 01
2409461 | PLAN 01
2409709 | PLAN 02
2409963 | PLAN 01
2410114 | PLAN 01
2410167 | PLAN 01
2410169 | PLAN 01
2410213 | PLAN 02
2410314 | PLAN 02
2410320 | PLAN 02
2410328 | PLAN 02
2410336 | PLAN 02
2410562 | PLAN 02
2410563 | PLAN 02
2410564 | PLAN 02
2410565 | PLAN 02
2410607 | PLAN 02
2410608 | PLAN 02
2410609 | PLAN 02
2410610 | PLAN 02
2410611 | PLAN 02
2410612 | PLAN 02
2410613 | PLAN 02
2410614 | PLAN 02
2410713 | PLAN 02
2410714 | PLAN 02
2410780 | PLAN 02
2410788 | PLAN 02
2410903 | PLAN 02
2410911 | PLAN 02
2410919 | PLAN 02
2410927 | PLAN 02
2410933 | PLAN 02
2411244 | PLAN 02
2411252 | PLAN 02
2411260 | PLAN 02
2411272 | PLAN 02
2411280 | PLAN 02
2446720 | PLAN 02
2446728 | PLAN 02
2446736 | PLAN 02
2446744 | PLAN 02
2446752 | PLAN 02
2446760 | PLAN 02
2446768 | PLAN 02
2446776 | PLAN 02
2446784 | PLAN 02
2446792 | PLAN 02
2446800 | PLAN 02
2446808 | PLAN 02
2446816 | PLAN 02
2446824 | PLAN 02
2446832 | PLAN 02
2446840 | PLAN 02
2446850 | PLAN 02
2446858 | PLAN 02
2446866 | PLAN 02
2446876 | PLAN 02
2446884 | PLAN 02
2446892 | PLAN 02
2446900 | PLAN 02
2446908 | PLAN 02
2446916 | PLAN 02
2446924 | PLAN 02
2446932 | PLAN 02
2446942 | PLAN 02
2446950 | PLAN 02
2446958 | PLAN 02
2446966 | PLAN 02
2446974 | PLAN 02
2447014 | PLAN 02
2447022 | PLAN 02
2447030 | PLAN 02
2447038 | PLAN 02
2467775 | PLAN 02
2467883 | PLAN 02
2467891 | PLAN 02
2467899 | PLAN 02
2467905 | PLAN 02
2467911 | PLAN 02
2467919 | PLAN 02
3265974 | PLAN 01
3265975 | PLAN 01
3266119 | PLAN 01
3266127 | PLAN 01
3266598 | PLAN 01
3268987 | PLAN 01
3268988 | PLAN 01
3269335 | PLAN 01
3269336 | PLAN U1
3269562 | PLAN 01
3269655 | PLAN 01
3269661 | PLAN 01
3519533 | PLAN 01
3519541 | PLAN 01
3519549 | PLAN 01
3519557 | PLAN 01
3519565 | PLAN 01
3541587 | PLAN 02
3541588 | PLAN 02
3541589 | PLAN 02
3541590 | PLAN 02
3541591 | PLAN 02
3541592 | PLAN 02
3541593 | PLAN 02
3541594 | PLAN 02
3541595 | PLAN 02
3541596 | PLAN 02
3541597 | PLAN 02
3541598 | PLAN 02
3541599 | PLAN 02
3541600 | PLAN 02
3541601 | PLAN 02
3541602 | PLAN 02
3541603 | PLAN 02
3541604 | PLAN 02
3541605 | PLAN 02
3541606 | PLAN 02
3541607 | PLAN 02
3541608 | PLAN 02
3541609 | PLAN 02
3541610 | PLAN 02
3541611 | PLAN 02
3541612 | PLAN 02
3541613 | PLAN 02
3541614 | PLAN 02
3541615 | PLAN 02
3541616 | PLAN 02
3541617 | PLAN 02
3541618 | PLAN 02
3541619 | PLAN 02
3541620 | PLAN 02
3541621 | PLAN 02
3541622 | PLAN 02
3541623 | PLAN 02
3541624 | PLAN 02
3541625 | PLAN 02
3541626 | PLAN 02
3541627 | PLAN 02
3541628 | PLAN 02
3541629 | PLAN 02
3542099 | PLAN 02
3542118 | PLAN 02
3542338 | PLAN 02
3542339 | PLAN 01
3542340 | PLAN 01
3542341 | PLAN 01
3542342 | PLAN 01
3621882 | PLAN 01
3621883 | PLAN 01
3622121 | PLAN 01
3622129 | PLAN 01
3622137 | PLAN 01
3622431 | PLAN 02
3622553 | PLAN 02
3622561 | PLAN 02
3622569 | PLAN 02
3622577 | PLAN 02
3624164 | PLAN 02
3627899 | PLAN 02
3627900 | PLAN 02
3627901 | PLAN 02
3668187 | PLAN U1
3668374 | PLAN U1
3668845 | PLAN U1
3668897 | PLAN U1
3669005 | PLAN U1
3669099 | PLAN U1
3669100 | PLAN U1
3669101 | PLAN U1
3669253 | PLAN 01
3669280 | PLAN 01
3669288 | PLAN 01
3669296 | PLAN 01
3669304 | PLAN 01
3669312 | PLAN 01
3669716 | PLAN 01
3777106 | PLAN 01
3777635 | TEKNISK SKILLE
3777740 | TEKNISK SKILLE
3778060 | PLAN 01
3778145 | PLAN 01
3778267 | PLAN 01
3778268 | TEKNISK SKILLE
3778526 | TEKNISK SKILLE
3778621 | TEKNISK SKILLE
3780203 | PLAN 01
3780204 | TEKNISK SKILLE
3780205 | PLAN 01
3780206 | TEKNISK SKILLE
3780207 | PLAN 01
3780208 | TEKNISK SKILLE
3780209 | PLAN 01
3780210 | TEKNISK SKILLE
3783827 | PLAN 02
3783830 | PLAN 02
3783831 | PLAN 02
3783832 | PLAN 02
3783833 | PLAN 02
3783834 | PLAN 02
3783837 | PLAN 02
3783838 | PLAN 02
3785184 | PLAN 02
3785342 | PLAN 02
3785479 | PLAN 02
3785480 | PLAN 02
3785481 | PLAN 02
3785482 | PLAN 02
3785565 | PLAN 02
3785625 | PLAN 02
3785678 | PLAN 02
3785679 | PLAN 02
4302608 | PLAN 01
4302616 | PLAN 01
4302624 | PLAN 01
4302632 | PLAN 01
4302640 | PLAN 01
4302648 | PLAN 01
4452266 | PLAN U1
4452267 | PLAN 01
4452268 | PLAN 01
4452271 | PLAN 01
4452272 | PLAN 01
4452273 | PLAN 01
4452274 | PLAN 01
4531560 | PLAN 01
4531639 | PLAN 01
4531710 | TEKNISK SKILLE
4531769 | PLAN 01
4531770 | PLAN 02
4532011 | PLAN 01

# IfcBuildingElementProxy: Flatskjermer:Monitor, 50-52", inkl. høyttalere (2)
In: B4-425A
Type - Material: <Unnamed>
Pset_BuildingElementProxyCommon - Reference: Monitor, 50-52", inkl. høyttalere; sets with these values: 2
Name (Flatskjermer:Monitor, 50-52", inkl. høyttalere:...)
2736904
2799293

# IfcBuildingElementProxy: Flatskjermer:Monitor, 55-60", inkl. høyttalere (5)
Type - Material: <Unnamed>
Pset_BuildingElementProxyCommon - Reference: Monitor, 55-60", inkl. høyttalere; sets with these values: 2
Name (Flatskjermer:Monitor, 55-60", inkl. høyttalere:...) | In
3032917 | B5-421
4330661 | B4-424B
4348734 | B5-422
4531115 | B5-412
4531286 | B5-422

# IfcBuildingElementProxy: Gulvvaskemaskin:Gulvvaskemaskin, stor, Gulvvaskemaskin:Gulvvaskemaskin, stor:2094450
In: B4-413
Type - Material: <Unnamed>
Pset_BuildingElementProxyCommon - Reference: Gulvvaskemaskin, stor; sets with these values: 2

# IfcBuildingElementProxy: Kaffemaskin:Kaffemaskin (2)
Type - Material: <Unnamed>, _Kaffemaschine_Black, _Kaffemaschine_Silber
Pset_BuildingElementProxyCommon - Reference: Kaffemaskin; sets with these values: 2
Name (Kaffemaskin:Kaffemaskin:...) | In
2636061 | B5-422
3109596 | B4-424B

# IfcBuildingElementProxy: Kaffetrakter:Kaffetrakter (2)
Type - Material: <Unnamed>
Pset_BuildingElementProxyCommon - Reference: Kaffetrakter; sets with these values: 2
Name (Kaffetrakter:Kaffetrakter:...) | In
2633653 | B5-422
2798276 | B4-425A

# IfcBuildingElementProxy: Kjøleskap:Kjøleskap, medisin 1 dør, Kjøleskap:Kjøleskap, medisin 1 dør:2553589
In: B4-417A
Type - Material: <Unnamed>
Pset_BuildingElementProxyCommon - Reference: Kjøleskap, medisin 1 dør; sets with these values: 2

# IfcBuildingElementProxy: Kjøleskap:Kjøleskap, medisin, H85cm, Kjøleskap:Kjøleskap, medisin, H85cm:2740052
In: B4-407B
Type - Material: <Unnamed>
Pset_BuildingElementProxyCommon - Reference: Kjøleskap, medisin, H85cm; sets with these values: 2

# IfcBuildingElementProxy: Kjøleskap:Kjøleskap, mopper, Kjøleskap:Kjøleskap, mopper:4323588
In: B4-413
Type - Material: <Unnamed>
Pset_BuildingElementProxyCommon - Reference: Kjøleskap, mopper; sets with these values: 2

# IfcBuildingElementProxy: Klokke:Klokke (15)
Type - Material: A_Default_Building_Part, <Unnamed>
Pset_BuildingElementProxyCommon - Reference: Klokke; sets with these values: 2
Name (Klokke:Klokke:...) | In
2594626 | B4-424B
2596676 | B4-425
2596841 | B4-425C
2596930 | B4-425B
2597178 | B4-425A
2597346 | B4-401
2597474 | B4-408
2598028 | B5-409
2598122 | B4-417
2939856 | B5-421
3501667 | B4-406
3501689 | B4-404
3501844 | B4-403
4619522 | B4-407
4849549 | B5-422

# IfcBuildingElementProxy: Lampe_undersøkelse_takmontert:Undersøk_lampe_kombi_Gyn (4)
Type - Material: <Unnamed>
Pset_BuildingElementProxyCommon - Reference: Undersøk_lampe_kombi_Gyn; sets with these values: 2
Name (Lampe_undersøkelse_takmontert:Undersøk_lampe_kombi_Gyn:...) | In
2770779 | B4-404
2770781 | B4-406
2770782 | B4-403
4916610 | B5-409

# IfcBuildingElementProxy: Legevakt skilt frittstående:Legevakt skilt frittstående, Legevakt skilt frittstående:Legevakt skilt frittstående:3779414
In: PLAN 01
Type - Material: Legevakt Skilt, A_Finish_Metal_Steel_Brushed
Pset_BuildingElementProxyCommon - Reference: Legevakt skilt frittstående; sets with these values: 2

# IfcBuildingElementProxy: Model Text:100mm Arial, Model Text:100mm Arial:3794839
In: PLAN 01
Pset_BuildingElementProxyCommon - Reference: 100mm Arial; sets with these values: 2

# IfcBuildingElementProxy: Model Text:180mm Arial, Model Text:180mm Arial:3787844
In: PLAN 02
Pset_BuildingElementProxyCommon - Reference: 180mm Arial; sets with these values: 2

# IfcBuildingElementProxy: Model Text:200mm Arial, Model Text:200mm Arial:3765936
In: PLAN 02
Pset_BuildingElementProxyCommon - Reference: 200mm Arial; sets with these values: 2

# IfcBuildingElementProxy: Model Text:400mm Arial (2)
In: TEKNISK SKILLE
Pset_BuildingElementProxyCommon - Reference: 400mm Arial; sets with these values: 2
Name (Model Text:400mm Arial:...)
3293957
3765934

# IfcBuildingElementProxy: O2 flaske på tralle:O2-flaske (3)
Type - Material: <Unnamed>
Pset_BuildingElementProxyCommon - Reference: O2-flaske; sets with these values: 2
Name (O2 flaske på tralle:O2-flaske:...) | In
4597865 | PLAN 01
4599581 | B4-407
4755784 | B4-408

# IfcBuildingElementProxy: PC, 1 Skjerm og tastatur:PC, 1 skjerm og tastatur (2)
Type - Material: <Unnamed>
Pset_BuildingElementProxyCommon - Reference: PC, 1 skjerm og tastatur; sets with these values: 2
Name (PC, 1 Skjerm og tastatur:PC, 1 skjerm og tastatur:...) | In
3212075 | B4-407B
3212886 | B4-425B

# IfcBuildingElementProxy: PC, 2 skjermer:PC, 2 skjermer og tastatur (7)
Type - Material: <Unnamed>
Pset_BuildingElementProxyCommon - Reference: PC, 2 skjermer og tastatur; sets with these values: 2
Name (PC, 2 skjermer:PC, 2 skjermer og tastatur:...) | In
3213038 | B5-403
3213284 | B5-409
3213352 | B5-406
3213380 | B5-408
4554644 | B5-403
4943752 | B5-403
4943757 | B5-403

# IfcBuildingElementProxy: PC, 3 Skjermer og tastatur:PC, 3 Skjermer og tastatur (6)
In: B5-421
Type - Material: <Unnamed>
Pset_BuildingElementProxyCommon - Reference: PC, 3 Skjermer og tastatur; sets with these values: 2
Name (PC, 3 Skjermer og tastatur:PC, 3 Skjermer og tastatur:...) | Group
3216600 | Model Group:Klyngebord:3041162
3217806 | Model Group:Klyngebord:3041162
3217857 | Model Group:Klyngebord:3041162
3218304 | Model Group:Klyngebord:3218300
3218305 | Model Group:Klyngebord:3218300
3218306 | Model Group:Klyngebord:3218300

# IfcBuildingElementProxy: PC, Buet skjerm og tastatur:PC, Buet skjerm og tastatur (7)
Type - Material: <Unnamed>
Pset_BuildingElementProxyCommon - Reference: PC, Buet skjerm og tastatur; sets with these values: 2
Name (PC, Buet skjerm og tastatur:PC, Buet skjerm og tastatur:...) | In
3185793 | B4-425A
3211821 | B5-409
3212279 | B4-403
3212333 | B4-404
3212357 | B4-425A
3213406 | B4-406
4138735 | B4-425C

# IfcBuildingElementProxy: Pasientløfter_takskinne:Pasientløfter_takskinne (2)
Type - Material: <Unnamed>
Pset_BuildingElementProxyCommon - Reference: Pasientløfter_takskinne; sets with these values: 2
Name (Pasientløfter_takskinne:Pasientløfter_takskinne:...) | In
2566168 | B4-408
4770197 | B4-407

# IfcBuildingElementProxy: Persiennekasse:Persiennekasse (31)
Type - Material: Aluminum
Pset_BuildingElementProxyCommon - Reference: Persiennekasse; sets with these values: 2
Name (Persiennekasse:Persiennekasse:...) | In
3772282 | B5-409
3772284 | B5-409
3772286 | B5-421
3772287 | B5-403
3772288 | B5-422
3772289 | B5-422
3772290 | B5-422
3772291 | B5-421
3772292 | B5-421
3772294 | B5-412
3772295 | B5-406
3772296 | B5-405
3772297 | B5-403
3772298 | B5-403
3772299 | B5-409
3772300 | B5-408
3772301 | B5-412
3772302 | B5-403
3774762 | B4-403
3774764 | B4-403
3774765 | B4-406
3774766 | B4-406
3774767 | B4-404
3774775 | B4-424B
3774776 | B4-424B
3774779 | B4-425C
3774781 | B4-425C
3774783 | B4-425A
3774784 | B4-425A
3774786 | B4-401
3774787 | B4-401

# IfcBuildingElementProxy: Printer A4:Printer A4 (6)
Type - Material: <Unnamed>
Pset_BuildingElementProxyCommon - Reference: Printer A4; sets with these values: 2
Name (Printer A4:Printer A4:...) | In
2734129 | B4-403
2770768 | B4-406
2770773 | B4-404
2772226 | B5-409
4273698 | B5-421
4645040 | B4-425C

# IfcBuildingElementProxy: Printer med scanner:Printer med scanner, Printer med scanner:Printer med scanner:2612482
In: B4-425A
Type - Material: <Unnamed>
Pset_BuildingElementProxyCommon - Reference: Printer med scanner; sets with these values: 2

# IfcBuildingElementProxy: Radioterminal:Radioterminal, Radioterminal:Radioterminal:4785408
In: B4-425A
Type - Material: <Unnamed>
Pset_BuildingElementProxyCommon - Reference: Radioterminal; sets with these values: 2

# IfcBuildingElementProxy: Rullegardin:Rullegardin (2)
In: B4-401
Type - Material: Overflate-Hvit
Pset_BuildingElementProxyCommon - Reference: Rullegardin; sets with these values: 2
Name (Rullegardin:Rullegardin:...)
4646615
4646905

# IfcBuildingElementProxy: Rullestol:Rullestol (3)
Type - Material: <Unnamed>
Pset_BuildingElementProxyCommon - Reference: Rullestol; sets with these values: 2
Name (Rullestol:Rullestol:...) | In
3122267 | B4-409
3122268 | B4-409
4285021 | B4-001

# IfcBuildingElementProxy: Sekkestativ, tøy:Sekkestativ tøy, Sekkestativ, tøy:Sekkestativ tøy:3034975
In: B5-419
Type - Material: <Unnamed>
Pset_BuildingElementProxyCommon - Reference: Sekkestativ tøy; sets with these values: 2

# IfcBuildingElementProxy: Sekkestativ, tøy:Sekkestativ, tøy, Sekkestativ, tøy:Sekkestativ, tøy:2553584
In: B4-412
Type - Material: <Unnamed>
Pset_BuildingElementProxyCommon - Reference: Sekkestativ, tøy; sets with these values: 2

# IfcBuildingElementProxy: Sekkestativ, tøy:Søppelstativ m. lokk -høy (10)
Type - Material: <Unnamed>
Pset_BuildingElementProxyCommon - Reference: Søppelstativ m. lokk -høy; sets with these values: 2
Name (Sekkestativ, tøy:Søppelstativ m. lokk -høy:...) | In
1765016 | B4-404
1765221 | B4-403
1765280 | B4-406
1890699 | B5-409A
1920300 | B4-412
1921379 | B4-417A
2553583 | B4-408A
3042365 | B4-408
3211495 | B4-407
3389385 | B4-408A

# IfcBuildingElementProxy: Selvbetjeningsautomat:Snacks, automat, Selvbetjeningsautomat:Snacks, automat:4285018
In: B4-001
Type - Material: <Unnamed>
Pset_BuildingElementProxyCommon - Reference: Snacks, automat; sets with these values: 2

# IfcBuildingElementProxy: Sikkerhetskabinett bordmodell:Sikkerhetskabinett bordmodell kl2, Sikkerhetskabinett bordmodell:Sikkerhetskabinett bordmodell kl2:2738721
In: B4-407B
Type - Material: <Unnamed>
Type - Pset_ManufacturerTypeInformation - Manufacturer: Sikkerhetskabinett bordmodell kl2. Sirius
Pset_BuildingElementProxyCommon - Reference: Sikkerhetskabinett bordmodell kl2; sets with these values: 2

# IfcBuildingElementProxy: Skjermtak:Skjermtak, Skjermtak:Skjermtak:3631536
In: PLAN 01
Type - Material: <Unnamed>, Plywood_01_1K
Material: Plywood_01_1K
Pset_BuildingElementProxyCommon - Reference: Skjermtak; sets with these values: 2

# IfcBuildingElementProxy: Stativ Blodtrykksapparat:Stativ Blodtrykksapparat, Stativ Blodtrykksapparat:Stativ Blodtrykksapparat:4877517
In: B4-425B
Type - Material: <Unnamed>
Pset_BuildingElementProxyCommon - Reference: Stativ Blodtrykksapparat; sets with these values: 2

# IfcBuildingElementProxy: Stol_behandling:Stol_behandling, Stol_behandling:Stol_behandling:1762146
In: B4-417
Type - Material: <Unnamed>
Pset_BuildingElementProxyCommon - Reference: Stol_behandling; sets with these values: 2

# IfcBuildingElementProxy: Støvsuger_industri:Støvsuger, industri (2)
Type - Material: <Unnamed>
Pset_BuildingElementProxyCommon - Reference: Støvsuger, industri; sets with these values: 2
Name (Støvsuger_industri:Støvsuger, industri:...) | In
3092854 | B5-413
4323750 | B4-413

# IfcBuildingElementProxy: Sug fastmontert på vegg:Sug, fastmontert på vegg, Sug fastmontert på vegg:Sug, fastmontert på vegg:2643341
In: PLAN 01
Type - Material: <Unnamed>
Pset_BuildingElementProxyCommon - Reference: Sug, fastmontert på vegg; sets with these values: 2

# IfcBuildingElementProxy: Toalett_dusjstol_mobil:Dostol, Toalett_dusjstol_mobil:Dostol:4650541
In: B4-411
Type - Material: <Unnamed>
Pset_BuildingElementProxyCommon - Reference: Dostol; sets with these values: 2

# IfcBuildingElementProxy: Tralle, PC, hev-senk:Tralle, PC, hev-senk (3)
Type - Material: <Unnamed>
Pset_BuildingElementProxyCommon - Reference: Tralle, PC, hev-senk; sets with these values: 2
Name (Tralle, PC, hev-senk:Tralle, PC, hev-senk:...) | In
2795944 | B4-408
2796050 | B4-407
2796112 | B4-401

# IfcBuildingElementProxy: Trillebord_m-håndtak:Trillebord-400x500 (4)
Type - Material: <Unnamed>
Pset_BuildingElementProxyCommon - Reference: Trillebord-400x500; sets with these values: 2
Name (Trillebord_m-håndtak:Trillebord-400x500:...) | In
2561361 | B4-401
2562915 | B4-403
2563112 | B4-404
2563427 | B4-406

# IfcBuildingElementProxy: Trillebord_m-håndtak:Trillebord-400x500, 2 hyller (4)
Type - Material: <Unnamed>
Pset_BuildingElementProxyCommon - Reference: Trillebord-400x500, 2 hyller; sets with these values: 2
Name (Trillebord_m-håndtak:Trillebord-400x500, 2 hyller:...) | In
2560443 | B4-425B
2561871 | B4-408
2562080 | B4-407
2563609 | B5-409

# IfcBuildingElementProxy: Ultralyd:Ultralyd, Ultralyd:Ultralyd:2414349
In: B4-409
Type - Material: <Unnamed>
Pset_BuildingElementProxyCommon - Reference: Ultralyd; sets with these values: 2

# IfcBuildingElementProxy: Undersøkelse- og behandlingsstol, kombi, gyn - vanlig us.benk:Undersøkelse- og behandlingsstol, kombi, gyn-vanlig (4)
Type - Material: <Unnamed>
Pset_BuildingElementProxyCommon - Reference: Undersøkelse- og behandlingsstol, kombi, gyn-vanlig; sets with these values: 2
Name (Undersøkelse- og behandlingsstol, kombi, gyn - vanlig us.benk:Undersøkelse- og behandlingsstol, kombi, gyn-vanlig:...) | In
2734124 | B4-403
2770777 | B4-406
2770778 | B4-404
4878066 | B5-409

# IfcBuildingElementProxy: Vanndispenser, stor:Vanndispenser på benk (2)
Type - Material: Default
Pset_BuildingElementProxyCommon - Reference: Vanndispenser på benk; sets with these values: 2
Name (Vanndispenser, stor:Vanndispenser på benk:...) | In
2417045 | B4-424B
4941037 | B5-422

# IfcBuildingElementProxy: Varmeskap:Varmeskap, Varmeskap:Varmeskap:2740053
In: B4-407B
Type - Material: <Unnamed>
Pset_BuildingElementProxyCommon - Reference: Varmeskap; sets with these values: 2

# IfcBuildingElementProxy: Vattenkokare:Vannkoker (2)
Type - Material: <Unnamed>
Pset_BuildingElementProxyCommon - Reference: Vannkoker; sets with these values: 2
Name (Vattenkokare:Vannkoker:...) | In
2634842 | B5-422
2798277 | B4-425A

# IfcBuildingElementProxy: Vegghengt Kanyleboks:Vegghengt Kanyleboks (6)
Type - Material: <Unnamed>
Pset_BuildingElementProxyCommon - Reference: Vegghengt Kanyleboks; sets with these values: 2
Name (Vegghengt Kanyleboks:Vegghengt Kanyleboks:...) | In
4613259 | B4-403
4630675 | B4-408
4630738 | B4-407
4631046 | B4-404
4631099 | B4-406
4631291 | B4-401

# IfcBuildingElementProxy: Vegghengt oftalmoskop:Vegghengt oftalmoskop_ otoskop (2)
Type - Material: <Unnamed>
Pset_BuildingElementProxyCommon - Reference: Vegghengt oftalmoskop_ otoskop; sets with these values: 2
Name (Vegghengt oftalmoskop:Vegghengt oftalmoskop_ otoskop:...) | In
4623981 | B4-408
4864271 | B4-407

# IfcBuildingElementProxy: Wall Sweep:Gesimsbeslag Garasje, Wall Sweep:Gesimsbeslag Garasje:3433998
In: PLAN 01
Material: A_Finish_Metal_Steel_Polished
Pset_BuildingElementProxyCommon - Reference: Gesimsbeslag Garasje; sets with these values: 2

# IfcBuildingElementProxy: ben-ventestol:Ben (9)
In: B4-424B
Type - Material: Sort metall
Pset_BuildingElementProxyCommon - Reference: Ben; sets with these values: 2
Name (ben-ventestol:Ben:...)
4088935
4088936
4088937
4088938
4093453
4093454
4093455
4093456
4093457

# IfcBuildingElementProxy: ​​Stand med skjerm:Selvinnsjekk, ​​Stand med skjerm:Selvinnsjekk:2421001
In: B4-424B
Type - Material: Sort, <Unnamed>
Pset_BuildingElementProxyCommon - Reference: Selvinnsjekk; sets with these values: 2

# IfcBuildingElementProxy: ​​Stand med skjerm:Taxibestilling, ​​Stand med skjerm:Taxibestilling:2416198
In: B4-424B
Type - Material: Sort, <Unnamed>
Pset_BuildingElementProxyCommon - Reference: Taxibestilling; sets with these values: 2

# IfcColumn: Søyle - Firkantet:222 Betongsøyle 300x300mm (36)
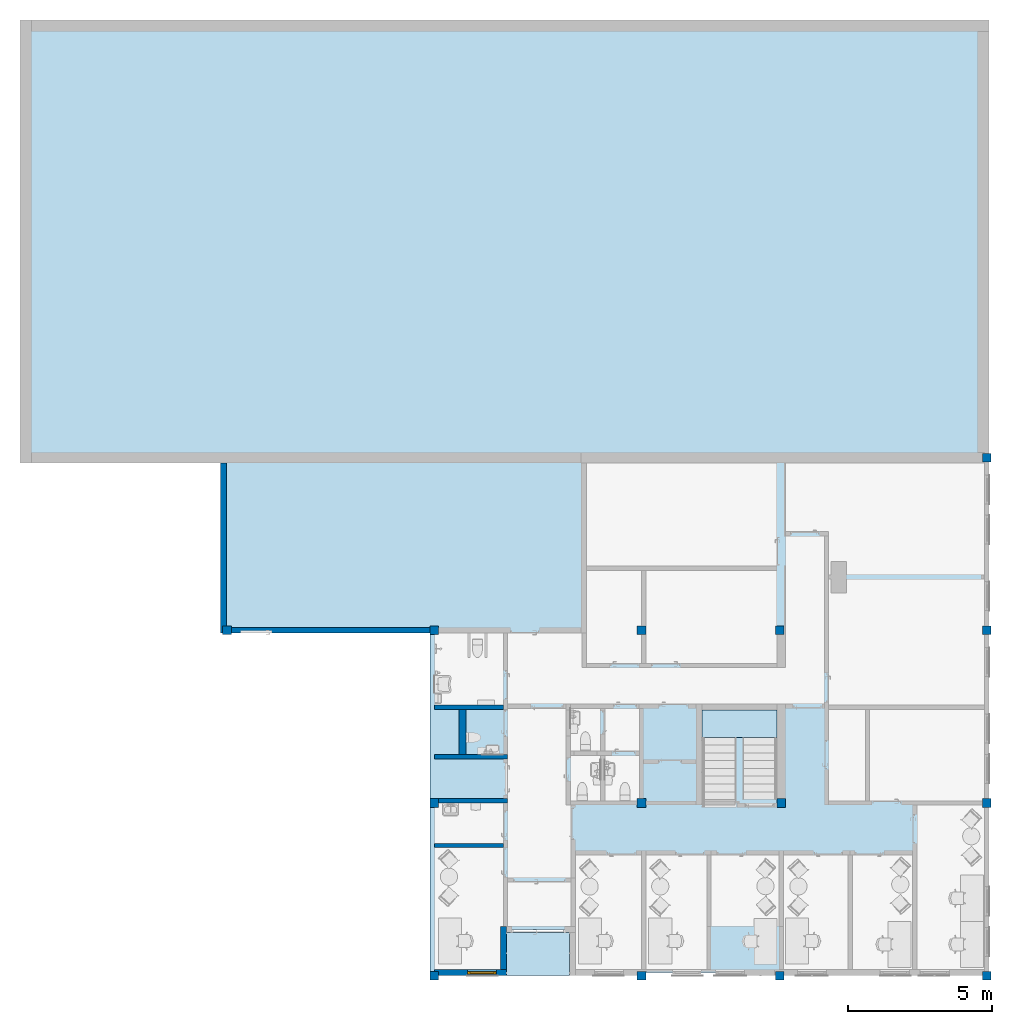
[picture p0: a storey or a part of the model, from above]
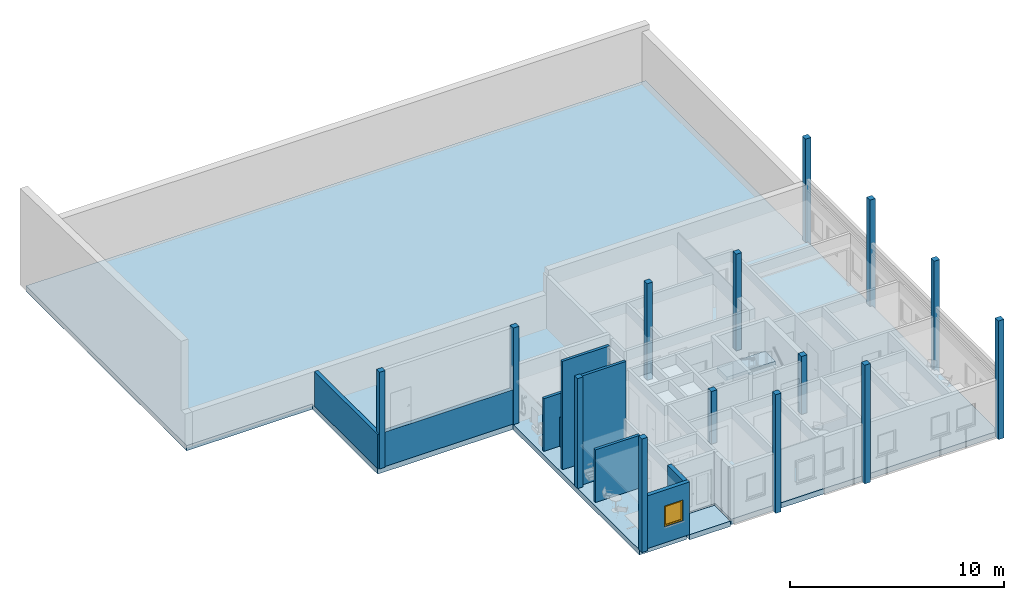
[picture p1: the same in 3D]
Properties of the parts of a building model (IFC2X3), part 2 of 4

# IfcColumn: Søyle - Firkantet:222 Betongsøyle 300x300mm (36)
Type - PredefinedType: COLUMN; Material: A_Material_Concrete_Insitu_Beam_Semi-Rough_Grey
Type - Pset_ColumnCommon - LoadBearing: yes
Pset_ColumnCommon - IsExternal: no; Reference: 222 Betongsøyle 300x300mm
Pset_QuantityTakeOff - Reference: 222 Betongsøyle 300x300mm; sets with these values: 2
Name (Søyle - Firkantet:222 Betongsøyle 300x300mm:...) | In
1557876 | PLAN 01
1558818 | PLAN 01
1558828 | PLAN 01
1558840 | PLAN 01
1559333 | PLAN 01
1559334 | PLAN 01 | Pset_ColumnCommon - Slope: 0 deg
1559335 | PLAN 01 | Pset_ColumnCommon - Slope: 0 deg
1559336 | PLAN 01 | Pset_ColumnCommon - Slope: 0 deg
1559337 | PLAN 02
1559338 | PLAN 02
1559339 | PLAN 02
1559350 | PLAN 01 | Pset_ColumnCommon - Slope: 0 deg
1559351 | PLAN 01
1559352 | PLAN 01
1559353 | PLAN U1
1559354 | PLAN 01
1559355 | PLAN 02
1559356 | PLAN 02
1661931 | PLAN U1
1661932 | PLAN U1
1661933 | PLAN U1
1661934 | PLAN U1 | Pset_ColumnCommon - Slope: 0 deg
1661935 | PLAN U1
1661936 | PLAN U1 | Pset_ColumnCommon - Slope: 0 deg
1661937 | PLAN U1
1661938 | PLAN U1
1661939 | PLAN U1
1661940 | PLAN U1
1661941 | PLAN U1 | Pset_ColumnCommon - Slope: 0 deg
1999590 | PLAN U1
2652073 | PLAN 01
3480429 | PLAN U1
3620614 | PLAN 01
3620615 | PLAN 01 | Pset_ColumnCommon - Slope: 0 deg
3669224 | PLAN 01
3669225 | PLAN 01

# IfcCovering: Compound Ceiling:256 Fast gips himling, perforert 100 mm (2)
In: B4-407
Type - PredefinedType: CEILING
Type - Pset_CoveringCommon - TotalThickness: 100 mm
Material: Gips, himling 100 mm
Pset_CoveringCommon - Reference: 256 Fast gips himling, perforert 100 mm; sets with these values: 2
Name (Compound Ceiling:256 Fast gips himling, perforert 100 mm:...)
1969265
4212259

# IfcCovering: Compound Ceiling:257 Generisk himling 100 mm (19)
Type - PredefinedType: CEILING
Type - Pset_CoveringCommon - TotalThickness: 100 mm
Material: <Unnamed> 100 mm
Pset_CoveringCommon - Reference: 257 Generisk himling 100 mm; sets with these values: 2
Name (Compound Ceiling:257 Generisk himling 100 mm:...) | In
4490592 | B5-326
4490614 | B5-323
4490625 | B5-322
4490633 | B5-321
4490641 | B5-401
4490649 | B5-317
4490657 | B5-314
4490671 | B5-319
4490683 | B5-302
4490691 | B5-301
4490709 | B5-311B
4490717 | WC:4167080
4490725 | B5-311
4490733 | B5-311A
4490749 | B5-304
4490765 | B5-303
4490774 | B5-307
4843217 | B5-313
4843260 | Vindfang:1801414

# IfcCovering: Compound Ceiling:257 Treullsementplater 1200x600 100 mm, T1 (2)
Type - PredefinedType: CEILING
Type - Pset_CoveringCommon - TotalThickness: 100 mm
Material: <Unnamed> 80 mm, Treull sementplater 1200x600 20 mm
Pset_CoveringCommon - Reference: 257 Treullsementplater 1200x600 100 mm, T1; Finish: Treull sementplater 1200x600;
Pset_QuantityTakeOff - Reference: 257 Treullsementplater 1200x600 100 mm, T1
Name (Compound Ceiling:257 Treullsementplater 1200x600 100 mm, T1:...) | In
1969400 | PLAN 01
2264628 | B4-001

# IfcCovering: Compound Ceiling:257 Treullsementplater 1200x600 40 mm, T2 (3)
Type - PredefinedType: CEILING
Type - Pset_CoveringCommon - TotalThickness: 40 mm
Material: Treull sementplater 1200x600 40 mm
Pset_CoveringCommon - Reference: 257 Treullsementplater 1200x600 40 mm, T2; sets with these values: 2
Name (Compound Ceiling:257 Treullsementplater 1200x600 40 mm, T2:...) | In
3395958 | PLAN 02
3807668 | B5-421
4224974 | B5-422

# IfcCovering: Compound Ceiling:2571 Innvendig hygienehimling 600x600 100 mm (14)
Type - PredefinedType: CEILING
Type - Pset_CoveringCommon - TotalThickness: 100 mm
Material: <Unnamed> 80 mm, Himling, system, 600 x 600 20 mm
Pset_CoveringCommon - Reference: 2571 Innvendig hygienehimling 600x600 100 mm; Finish: Himling, system, 600 x 600;
Pset_QuantityTakeOff - Reference: 2571 Innvendig hygienehimling 600x600 100 mm
Name (Compound Ceiling:2571 Innvendig hygienehimling 600x600 100 mm:...) | In
1969212 | B5-409
1969220 | B4-411
1969237 | B4-413
1969253 | B4-408
1969275 | B4-406
1969285 | B4-404
1969339 | B4-403
1969392 | B4-425B
1969436 | B4-412
1969444 | B4-417A
1969452 | B4-417
2242508 | B4-407B
2264615 | B4-401
3396245 | B5-409A

# IfcCovering: Compound Ceiling:2571 Innvendig systemhimling 600x600 100 mm (28)
Type - PredefinedType: CEILING
Type - Pset_CoveringCommon - TotalThickness: 100 mm
Material: <Unnamed> 80 mm, Himling, system, 600 x 600 20 mm
Pset_CoveringCommon - Reference: 2571 Innvendig systemhimling 600x600 100 mm; sets with these values: 2
Name (Compound Ceiling:2571 Innvendig systemhimling 600x600 100 mm:...) | In
1969229 | B4-412
1969245 | B4-409
1969384 | B4-425C
1969415 | B4-423
1969428 | B4-422
2468474 | B4-425A
3394548 | B4-414
3394626 | PLAN 01
3394659 | B4-404B
3394667 | B4-403B
3394715 | PLAN 01
3394729 | PLAN 01
3394874 | B4-425
3394882 | B4-422B
3394896 | B4-010
3395078 | B5-405
3395086 | B5-406
3395094 | B5-408
3395102 | B5-409
3395123 | B5-412
3395168 | B5-403
3395888 | B5-413
4490527 | Korridor:1801431
4490546 | Gang:2708464
4490580 | Kontor:2708261
4490602 | B5-324
4490701 | Vindfang:1801414
4863654 | 410

# IfcDoor: Enfløyet:234 Utvendig WAa 13x21M - Tett, Enfløyet:234 Utvendig WAa 13x21M - Tett:3634529
In: PLAN 01
Type - OperationType: SINGLE_SWING_RIGHT; ParameterTakesPrecedence: no; Sizeable: no; Material: Door - Leaf, Door - Handle, Door - Frame
Type - Enfløyet:234 Utvendig WAa 13x21M - Tett:3634529:1 - PanelOperation: SWINGING
OverallHeight: 2100 mm; OverallWidth: 1310 mm
Pset_DoorCommon - IsExternal: yes; Reference: 234 Utvendig WAa 13x21M - Tett
Pset_QuantityTakeOff - Reference: 234 Utvendig WAa 13x21M - Tett

# IfcDoor: Enfløyet:244 Innvendig AAa 10x21M - Tett (4)
Type - OperationType: SINGLE_SWING_RIGHT; ParameterTakesPrecedence: no; Sizeable: no; Material: Door - Beige, Door - Handle
Type - Enfløyet:244 Innvendig AAa 10x21M - Tett:1707733:1 - PanelOperation: SWINGING
OverallHeight: 2100 mm; OverallWidth: 1010 mm
Pset_DoorCommon - IsExternal: no; Reference: 244 Innvendig AAa 10x21M - Tett
Pset_QuantityTakeOff - Reference: 244 Innvendig AAa 10x21M - Tett
Name (Enfløyet:244 Innvendig AAa 10x21M - Tett:...) | In
1707733 | PLAN 02
1869859 | PLAN 01
2519549 | PLAN 01
2713496 | PLAN 02

# IfcDoor: Enfløyet:244 Innvendig AAa 10x21M - Tett (7)
Type - OperationType: SINGLE_SWING_RIGHT; ParameterTakesPrecedence: no; Sizeable: no; Material: Door - Beige, Door - Handle
Type - Enfløyet:244 Innvendig AAa 10x21M - Tett:1910230:1 - PanelOperation: SWINGING
OverallHeight: 2100 mm; OverallWidth: 1010 mm
Pset_DoorCommon - IsExternal: no; Reference: 244 Innvendig AAa 10x21M - Tett
Pset_QuantityTakeOff - Reference: 244 Innvendig AAa 10x21M - Tett
Name (Enfløyet:244 Innvendig AAa 10x21M - Tett:...) | In
1910230 | PLAN 01
2093668 | PLAN 02
2252644 | PLAN U1
2257676 | PLAN 01
2708142 | PLAN U1
2712880 | PLAN 02
4347422 | PLAN U1

# IfcDoor: Enfløyet:244 Innvendig AAa 10x21M - Tett, Enfløyet:244 Innvendig AAa 10x21M - Tett:1915015
In: PLAN 02
Type - OperationType: SINGLE_SWING_RIGHT; ParameterTakesPrecedence: no; Sizeable: no; Material: Door - Beige, Door - Handle
Type - Enfløyet:244 Innvendig AAa 10x21M - Tett:1915015:1 - PanelOperation: SWINGING
OverallHeight: 2100 mm; OverallWidth: 1010 mm
Pset_DoorCommon - IsExternal: no; Reference: 244 Innvendig AAa 10x21M - Tett
Pset_QuantityTakeOff - Reference: 244 Innvendig AAa 10x21M - Tett

# IfcDoor: Enfløyet:244 Innvendig AAa 10x21M - Tett - Trelaminat (2)
Type - OperationType: SINGLE_SWING_RIGHT; ParameterTakesPrecedence: no; Sizeable: no; Material: Ask, Door - Handle
Type - Enfløyet:244 Innvendig AAa 10x21M - Tett - Trelaminat:1892404:1 - PanelOperation: SWINGING
OverallHeight: 2100 mm; OverallWidth: 1010 mm
Pset_DoorCommon - IsExternal: no; Reference: 244 Innvendig AAa 10x21M - Tett - Trelaminat
Pset_QuantityTakeOff - Reference: 244 Innvendig AAa 10x21M - Tett - Trelaminat
Name (Enfløyet:244 Innvendig AAa 10x21M - Tett - Trelaminat:...) | In
1892404 | PLAN 01
3809020 | PLAN 02

# IfcDoor: Enfløyet:244 Innvendig AAa 10x21M - Tett Grå (2)
In: PLAN 01
Type - OperationType: SINGLE_SWING_RIGHT; ParameterTakesPrecedence: no; Sizeable: no; Material: formica_Citadel, Door - Handle
Type - Enfløyet:244 Innvendig AAa 10x21M - Tett Grå:1779586:1 - PanelOperation: SWINGING
OverallHeight: 2100 mm; OverallWidth: 1010 mm
Pset_DoorCommon - IsExternal: no; Reference: 244 Innvendig AAa 10x21M - Tett Grå
Pset_QuantityTakeOff - Reference: 244 Innvendig AAa 10x21M - Tett Grå
Name (Enfløyet:244 Innvendig AAa 10x21M - Tett Grå:...)
1779586
2526005

# IfcDoor: Enfløyet:244 Innvendig AAa 11x21M - Tett, Enfløyet:244 Innvendig AAa 11x21M - Tett:1705576
In: PLAN 02
Type - OperationType: SINGLE_SWING_RIGHT; ParameterTakesPrecedence: no; Sizeable: no; Material: Door - Beige, Door - Handle
Type - Enfløyet:244 Innvendig AAa 11x21M - Tett:1705576:1 - PanelOperation: SWINGING
OverallHeight: 2100 mm; OverallWidth: 1110 mm
Pset_DoorCommon - IsExternal: no; Reference: 244 Innvendig AAa 11x21M - Tett
Pset_QuantityTakeOff - Reference: 244 Innvendig AAa 11x21M - Tett

# IfcDoor: Enfløyet:244 Innvendig AAa 11x21M - Tett, Enfløyet:244 Innvendig AAa 11x21M - Tett:1705617
In: PLAN 01
Type - OperationType: SINGLE_SWING_RIGHT; ParameterTakesPrecedence: no; Sizeable: no; Material: Door - Beige, Door - Handle
Type - Enfløyet:244 Innvendig AAa 11x21M - Tett:1705617:1 - PanelOperation: SWINGING
OverallHeight: 2100 mm; OverallWidth: 1110 mm
Pset_DoorCommon - IsExternal: no; Reference: 244 Innvendig AAa 11x21M - Tett
Pset_QuantityTakeOff - Reference: 244 Innvendig AAa 11x21M - Tett

# IfcDoor: Enfløyet:244 Innvendig AAa 11x21M - Tett (2)
Type - OperationType: SINGLE_SWING_RIGHT; ParameterTakesPrecedence: no; Sizeable: no; Material: Door - Beige, Door - Handle
Type - Enfløyet:244 Innvendig AAa 11x21M - Tett:2521165:1 - PanelOperation: SWINGING
OverallHeight: 2100 mm; OverallWidth: 1110 mm
Pset_DoorCommon - IsExternal: no; Reference: 244 Innvendig AAa 11x21M - Tett
Pset_QuantityTakeOff - Reference: 244 Innvendig AAa 11x21M - Tett
Name (Enfløyet:244 Innvendig AAa 11x21M - Tett:...) | In
2521165 | PLAN 01
4167103 | PLAN U1

# IfcDoor: Enfløyet:244 Innvendig AAa 11x21M - Tett, Enfløyet:244 Innvendig AAa 11x21M - Tett:2813751
In: PLAN U1
Type - OperationType: SINGLE_SWING_RIGHT; ParameterTakesPrecedence: no; Sizeable: no; Material: Door - Beige, Door - Handle
Type - Enfløyet:244 Innvendig AAa 11x21M - Tett:2813751:1 - PanelOperation: SWINGING
OverallHeight: 2100 mm; OverallWidth: 1110 mm
Pset_DoorCommon - IsExternal: no; Reference: 244 Innvendig AAa 11x21M - Tett
Pset_QuantityTakeOff - Reference: 244 Innvendig AAa 11x21M - Tett

# IfcDoor: Enfløyet:244 Innvendig AAa 11x21M - Tett, Enfløyet:244 Innvendig AAa 11x21M - Tett:4167611
In: PLAN 01
Type - OperationType: SINGLE_SWING_RIGHT; ParameterTakesPrecedence: no; Sizeable: no; Material: Door - Beige, Door - Handle
Type - Enfløyet:244 Innvendig AAa 11x21M - Tett:4167611:1 - PanelOperation: SWINGING
OverallHeight: 2100 mm; OverallWidth: 1110 mm
Pset_DoorCommon - IsExternal: no; Reference: 244 Innvendig AAa 11x21M - Tett
Pset_QuantityTakeOff - Reference: 244 Innvendig AAa 11x21M - Tett

# IfcDoor: Enfløyet:244 Innvendig AAa 11x21M - Tett, Enfløyet:244 Innvendig AAa 11x21M - Tett:4347792
In: PLAN U1
Type - OperationType: SINGLE_SWING_RIGHT; ParameterTakesPrecedence: no; Sizeable: no; Material: Door - Beige, Door - Handle
Type - Enfløyet:244 Innvendig AAa 11x21M - Tett:4347792:1 - PanelOperation: SWINGING
OverallHeight: 2100 mm; OverallWidth: 1110 mm
Pset_DoorCommon - IsExternal: no; Reference: 244 Innvendig AAa 11x21M - Tett
Pset_QuantityTakeOff - Reference: 244 Innvendig AAa 11x21M - Tett

# IfcDoor: Enfløyet:244 Innvendig AAa 11x21M - Tett, Enfløyet:244 Innvendig AAa 11x21M - Tett:4477625
In: PLAN 01
Type - OperationType: SINGLE_SWING_RIGHT; ParameterTakesPrecedence: no; Sizeable: no; Material: Door - Beige, Door - Handle
Type - Enfløyet:244 Innvendig AAa 11x21M - Tett:4477625:1 - PanelOperation: SWINGING
OverallHeight: 2100 mm; OverallWidth: 1110 mm
Pset_DoorCommon - IsExternal: no; Reference: 244 Innvendig AAa 11x21M - Tett
Pset_QuantityTakeOff - Reference: 244 Innvendig AAa 11x21M - Tett

# IfcDoor: Enfløyet:244 Innvendig AAa 11x21M - Tett, Enfløyet:244 Innvendig AAa 11x21M - Tett:4478673
In: PLAN 01
Type - OperationType: SINGLE_SWING_RIGHT; ParameterTakesPrecedence: no; Sizeable: no; Material: Door - Beige, Door - Handle
Type - Enfløyet:244 Innvendig AAa 11x21M - Tett:4478673:1 - PanelOperation: SWINGING
OverallHeight: 2100 mm; OverallWidth: 1110 mm
Pset_DoorCommon - IsExternal: no; Reference: 244 Innvendig AAa 11x21M - Tett
Pset_QuantityTakeOff - Reference: 244 Innvendig AAa 11x21M - Tett

# IfcDoor: Enfløyet:244 Innvendig AAa 11x21M - Tett - Trelaminat (2)
In: PLAN 01
Type - OperationType: SINGLE_SWING_RIGHT; ParameterTakesPrecedence: no; Sizeable: no; Material: Ask, Door - Handle
Type - Enfløyet:244 Innvendig AAa 11x21M - Tett - Trelaminat:1744954:1 - PanelOperation: SWINGING
OverallHeight: 2100 mm; OverallWidth: 1110 mm
Pset_DoorCommon - IsExternal: no; Reference: 244 Innvendig AAa 11x21M - Tett - Trelaminat
Pset_QuantityTakeOff - Reference: 244 Innvendig AAa 11x21M - Tett - Trelaminat
Name (Enfløyet:244 Innvendig AAa 11x21M - Tett - Trelaminat:...)
1744954
2100672

# IfcDoor: Enfløyet:244 Innvendig AAa 11x21M - Tett Grå (2)
In: PLAN 01
Type - OperationType: SINGLE_SWING_RIGHT; ParameterTakesPrecedence: no; Sizeable: no; Material: formica_Citadel, Door - Handle
Type - Enfløyet:244 Innvendig AAa 11x21M - Tett Grå:1753103:1 - PanelOperation: SWINGING
OverallHeight: 2100 mm; OverallWidth: 1110 mm
Pset_DoorCommon - IsExternal: no; Reference: 244 Innvendig AAa 11x21M - Tett Grå
Pset_QuantityTakeOff - Reference: 244 Innvendig AAa 11x21M - Tett Grå
Name (Enfløyet:244 Innvendig AAa 11x21M - Tett Grå:...)
1753103
1753666

# IfcDoor: Enfløyet:244 Innvendig AAa 11x21M - Tett Grå (2)
In: PLAN 01
Type - OperationType: SINGLE_SWING_RIGHT; ParameterTakesPrecedence: no; Sizeable: no; Material: formica_Citadel, Door - Handle
Type - Enfløyet:244 Innvendig AAa 11x21M - Tett Grå:1753159:1 - PanelOperation: SWINGING
OverallHeight: 2100 mm; OverallWidth: 1110 mm
Pset_DoorCommon - IsExternal: no; Reference: 244 Innvendig AAa 11x21M - Tett Grå
Pset_QuantityTakeOff - Reference: 244 Innvendig AAa 11x21M - Tett Grå
Name (Enfløyet:244 Innvendig AAa 11x21M - Tett Grå:...)
1753159
2519552

# IfcDoor: Enfløyet:244 Innvendig AAa 12x21M - Tett Grå, Enfløyet:244 Innvendig AAa 12x21M - Tett Grå:1917865
In: PLAN 01
Type - OperationType: SINGLE_SWING_RIGHT; ParameterTakesPrecedence: no; Sizeable: no; Material: formica_Citadel, Door - Handle
Type - Enfløyet:244 Innvendig AAa 12x21M - Tett Grå:1917865:1 - PanelOperation: SWINGING
OverallHeight: 2100 mm; OverallWidth: 1210 mm
Pset_DoorCommon - IsExternal: no; Reference: 244 Innvendig AAa 12x21M - Tett Grå
Pset_QuantityTakeOff - Reference: 244 Innvendig AAa 12x21M - Tett Grå

# IfcDoor: Enfløyet:244 Innvendig AAa 13x21M - Tett, Enfløyet:244 Innvendig AAa 13x21M - Tett:2256147
In: PLAN 01
Type - OperationType: SINGLE_SWING_RIGHT; ParameterTakesPrecedence: no; Sizeable: no; Material: Door - Beige, Door - Handle
Type - Enfløyet:244 Innvendig AAa 13x21M - Tett:2256147:1 - PanelOperation: SWINGING
OverallHeight: 2100 mm; OverallWidth: 1310 mm
Pset_DoorCommon - IsExternal: no; Reference: 244 Innvendig AAa 13x21M - Tett
Pset_QuantityTakeOff - Reference: 244 Innvendig AAa 13x21M - Tett

# IfcDoor: Enfløyet:244 Innvendig AAa 8x21M - Tett, Enfløyet:244 Innvendig AAa 8x21M - Tett:2713509
In: PLAN 02
Type - OperationType: SINGLE_SWING_RIGHT; ParameterTakesPrecedence: no; Sizeable: no; Material: Door - Beige, Door - Handle
Type - Enfløyet:244 Innvendig AAa 8x21M - Tett:2713509:1 - PanelOperation: SWINGING
OverallHeight: 2100 mm; OverallWidth: 810 mm
Pset_DoorCommon - IsExternal: no; Reference: 244 Innvendig AAa 8x21M - Tett
Pset_QuantityTakeOff - Reference: 244 Innvendig AAa 8x21M - Tett

# IfcDoor: Enfløyet:244 Innvendig AAa 8x21M - Tett (2)
Type - OperationType: SINGLE_SWING_RIGHT; ParameterTakesPrecedence: no; Sizeable: no; Material: Door - Beige, Door - Handle
Type - Enfløyet:244 Innvendig AAa 8x21M - Tett:2722994:1 - PanelOperation: SWINGING
OverallHeight: 2100 mm; OverallWidth: 810 mm
Pset_DoorCommon - IsExternal: no; Reference: 244 Innvendig AAa 8x21M - Tett
Pset_QuantityTakeOff - Reference: 244 Innvendig AAa 8x21M - Tett
Name (Enfløyet:244 Innvendig AAa 8x21M - Tett:...) | In
2722994 | PLAN 02
4166401 | PLAN U1

# IfcDoor: Enfløyet:244 Innvendig AAa 8x21M - Tett (2)
In: PLAN U1
Type - OperationType: SINGLE_SWING_RIGHT; ParameterTakesPrecedence: no; Sizeable: no; Material: Door - Beige, Door - Handle
Type - Enfløyet:244 Innvendig AAa 8x21M - Tett:4166287:1 - PanelOperation: SWINGING
OverallHeight: 2100 mm; OverallWidth: 810 mm
Pset_DoorCommon - IsExternal: no; Reference: 244 Innvendig AAa 8x21M - Tett
Pset_QuantityTakeOff - Reference: 244 Innvendig AAa 8x21M - Tett
Name (Enfløyet:244 Innvendig AAa 8x21M - Tett:...)
4166287
4166522

# IfcDoor: Enfløyet:244 Innvendig AAa 8x21M - Tett - Trelaminat, Enfløyet:244 Innvendig AAa 8x21M - Tett - Trelaminat:1712446
In: PLAN 01
Type - OperationType: SINGLE_SWING_RIGHT; ParameterTakesPrecedence: no; Sizeable: no; Material: Ask, Door - Handle
Type - Enfløyet:244 Innvendig AAa 8x21M - Tett - Trelaminat:1712446:1 - PanelOperation: SWINGING
OverallHeight: 2100 mm; OverallWidth: 810 mm
Pset_DoorCommon - IsExternal: no; Reference: 244 Innvendig AAa 8x21M - Tett - Trelaminat
Pset_QuantityTakeOff - Reference: 244 Innvendig AAa 8x21M - Tett - Trelaminat

# IfcDoor: Enfløyet:244 Innvendig AAa 9x21M - Tett Tre, Enfløyet:244 Innvendig AAa 9x21M - Tett Tre:2721720
In: PLAN 02
Type - OperationType: SINGLE_SWING_RIGHT; ParameterTakesPrecedence: no; Sizeable: no; Material: Ask, Door - Handle
Type - Enfløyet:244 Innvendig AAa 9x21M - Tett Tre:2721720:1 - PanelOperation: SWINGING
OverallHeight: 2100 mm; OverallWidth: 910 mm
Pset_DoorCommon - IsExternal: no; Reference: 244 Innvendig AAa 9x21M - Tett Tre
Pset_QuantityTakeOff - Reference: 244 Innvendig AAa 9x21M - Tett Tre

# IfcDoor: Enfløyet:244 Innvendig AAa 9x21M - Tett Tre, Enfløyet:244 Innvendig AAa 9x21M - Tett Tre:2721818
In: PLAN 02
Type - OperationType: SINGLE_SWING_RIGHT; ParameterTakesPrecedence: no; Sizeable: no; Material: Ask, Door - Handle
Type - Enfløyet:244 Innvendig AAa 9x21M - Tett Tre:2721818:1 - PanelOperation: SWINGING
OverallHeight: 2100 mm; OverallWidth: 910 mm
Pset_DoorCommon - IsExternal: no; Reference: 244 Innvendig AAa 9x21M - Tett Tre
Pset_QuantityTakeOff - Reference: 244 Innvendig AAa 9x21M - Tett Tre

# IfcDoor: Enfløyet:244 Innvendig AAb 10x21M - Frostet Glass - trelaminat, Enfløyet:244 Innvendig AAb 10x21M - Frostet Glass - trelaminat:1695085
In: PLAN 01
Type - OperationType: SINGLE_SWING_RIGHT; ParameterTakesPrecedence: no; Sizeable: no; Material: NO_Glass, Ask, Door - Handle
Type - Enfløyet:244 Innvendig AAb 10x21M - Frostet Glass - trelaminat:1695085:1 - PanelOperation: SWINGING
OverallHeight: 2100 mm; OverallWidth: 1010 mm
Pset_DoorCommon - IsExternal: no; Reference: 244 Innvendig AAb 10x21M - Frostet Glass - trelaminat
Pset_QuantityTakeOff - Reference: 244 Innvendig AAb 10x21M - Frostet Glass - trelaminat

# IfcDoor: Enfløyet:244 Innvendig AAb 10x21M - Frostet Glass - trelaminat, Enfløyet:244 Innvendig AAb 10x21M - Frostet Glass - trelaminat:1695227
In: PLAN 01
Type - OperationType: SINGLE_SWING_RIGHT; ParameterTakesPrecedence: no; Sizeable: no; Material: NO_Glass, Ask, Door - Handle
Type - Enfløyet:244 Innvendig AAb 10x21M - Frostet Glass - trelaminat:1695227:1 - PanelOperation: SWINGING
OverallHeight: 2100 mm; OverallWidth: 1010 mm
Pset_DoorCommon - IsExternal: no; Reference: 244 Innvendig AAb 10x21M - Frostet Glass - trelaminat
Pset_QuantityTakeOff - Reference: 244 Innvendig AAb 10x21M - Frostet Glass - trelaminat

# IfcDoor: Enfløyet:244 Innvendig AAb 10x21M - Glass - Trelaminat (4)
In: PLAN 01
Type - OperationType: SINGLE_SWING_RIGHT; ParameterTakesPrecedence: no; Sizeable: no; Material: NO_Glass, Ask, Door - Handle
Type - Enfløyet:244 Innvendig AAb 10x21M - Glass - Trelaminat:1790154:1 - PanelOperation: SWINGING
OverallHeight: 2100 mm; OverallWidth: 1010 mm
Pset_DoorCommon - IsExternal: no; Reference: 244 Innvendig AAb 10x21M - Glass - Trelaminat
Pset_QuantityTakeOff - Reference: 244 Innvendig AAb 10x21M - Glass - Trelaminat
Name (Enfløyet:244 Innvendig AAb 10x21M - Glass - Trelaminat:...)
1790154
2267271
2737193
2791614

# IfcDoor: Enfløyet:244 Innvendig AAb 11x21M - Glass, Enfløyet:244 Innvendig AAb 11x21M - Glass:1716198
In: PLAN 01
Type - OperationType: SINGLE_SWING_RIGHT; ParameterTakesPrecedence: no; Sizeable: no; Material: NO_Glass, Door - Beige, Door - Handle
Type - Enfløyet:244 Innvendig AAb 11x21M - Glass:1716198:1 - PanelOperation: SWINGING
OverallHeight: 2100 mm; OverallWidth: 1110 mm
Pset_DoorCommon - IsExternal: no; Reference: 244 Innvendig AAb 11x21M - Glass
Pset_QuantityTakeOff - Reference: 244 Innvendig AAb 11x21M - Glass

# IfcDoor: Enfløyet:244 Innvendig AAc 10x21M - Firkantet vindu, Enfløyet:244 Innvendig AAc 10x21M - Firkantet vindu:1817336
In: PLAN 01
Type - OperationType: SINGLE_SWING_RIGHT; ParameterTakesPrecedence: no; Sizeable: no; Material: NO_Glass, Door - Beige, Door - Handle
Type - Enfløyet:244 Innvendig AAc 10x21M - Firkantet vindu:1817336:1 - PanelOperation: SWINGING
OverallHeight: 2100 mm; OverallWidth: 1010 mm
Pset_DoorCommon - IsExternal: no; Reference: 244 Innvendig AAc 10x21M - Firkantet vindu
Pset_QuantityTakeOff - Reference: 244 Innvendig AAc 10x21M - Firkantet vindu

# IfcDoor: Enfløyet:244 Innvendig AAc 10x21M - Firkantet vindu (2)
In: PLAN 01
Type - OperationType: SINGLE_SWING_RIGHT; ParameterTakesPrecedence: no; Sizeable: no; Material: NO_Glass, Door - Beige, Door - Handle
Type - Enfløyet:244 Innvendig AAc 10x21M - Firkantet vindu:1899735:1 - PanelOperation: SWINGING
OverallHeight: 2100 mm; OverallWidth: 1010 mm
Pset_DoorCommon - IsExternal: no; Reference: 244 Innvendig AAc 10x21M - Firkantet vindu
Pset_QuantityTakeOff - Reference: 244 Innvendig AAc 10x21M - Firkantet vindu
Name (Enfløyet:244 Innvendig AAc 10x21M - Firkantet vindu:...)
1899735
1920354

# IfcDoor: Enfløyet:244 Innvendig BAa 10x21M - Tett, Enfløyet:244 Innvendig BAa 10x21M - Tett:2016581
In: PLAN 01
Type - OperationType: SINGLE_SWING_RIGHT; ParameterTakesPrecedence: no; Sizeable: no; Material: Door - Beige, Door - Handle
Type - Enfløyet:244 Innvendig BAa 10x21M - Tett:2016581:1 - PanelOperation: SWINGING
OverallHeight: 2100 mm; OverallWidth: 1010 mm
Pset_DoorCommon - IsExternal: no; Reference: 244 Innvendig BAa 10x21M - Tett
Pset_QuantityTakeOff - Reference: 244 Innvendig BAa 10x21M - Tett

# IfcDoor: Enfløyet:244 Innvendig BAa 10x21M - Tett Grå, Enfløyet:244 Innvendig BAa 10x21M - Tett Grå:2520851
In: PLAN 01
Type - OperationType: SINGLE_SWING_RIGHT; ParameterTakesPrecedence: no; Sizeable: no; Material: formica_Citadel, Door - Handle
Type - Enfløyet:244 Innvendig BAa 10x21M - Tett Grå:2520851:1 - PanelOperation: SWINGING
OverallHeight: 2100 mm; OverallWidth: 1010 mm
Pset_DoorCommon - IsExternal: no; Reference: 244 Innvendig BAa 10x21M - Tett Grå
Pset_QuantityTakeOff - Reference: 244 Innvendig BAa 10x21M - Tett Grå

# IfcDoor: Enfløyet:244 Innvendig BAa 10x21M - Tett Tre, Enfløyet:244 Innvendig BAa 10x21M - Tett Tre:2713491
In: PLAN 02
Type - OperationType: SINGLE_SWING_RIGHT; ParameterTakesPrecedence: no; Sizeable: no; Material: Ask, Door - Handle
Type - Enfløyet:244 Innvendig BAa 10x21M - Tett Tre:2713491:1 - PanelOperation: SWINGING
OverallHeight: 2100 mm; OverallWidth: 1010 mm
Pset_DoorCommon - IsExternal: no; Reference: 244 Innvendig BAa 10x21M - Tett Tre
Pset_QuantityTakeOff - Reference: 244 Innvendig BAa 10x21M - Tett Tre

# IfcDoor: Enfløyet:244 Innvendig BAa 8x21M - Tett, Enfløyet:244 Innvendig BAa 8x21M - Tett:2713508
In: PLAN 02
Type - OperationType: SINGLE_SWING_RIGHT; ParameterTakesPrecedence: no; Sizeable: no; Material: Door - Beige, Door - Handle, Door - Frame
Type - Enfløyet:244 Innvendig BAa 8x21M - Tett:2713508:1 - PanelOperation: SWINGING
OverallHeight: 2100 mm; OverallWidth: 810 mm
Pset_DoorCommon - IsExternal: no; Reference: 244 Innvendig BAa 8x21M - Tett
Pset_QuantityTakeOff - Reference: 244 Innvendig BAa 8x21M - Tett

# IfcDoor: Enfløyet:244 Innvendig BAa 8x21M - Tett, Enfløyet:244 Innvendig BAa 8x21M - Tett:2722993
In: PLAN 02
Type - OperationType: SINGLE_SWING_RIGHT; ParameterTakesPrecedence: no; Sizeable: no; Material: Door - Beige, Door - Handle, Door - Frame
Type - Enfløyet:244 Innvendig BAa 8x21M - Tett:2722993:1 - PanelOperation: SWINGING
OverallHeight: 2100 mm; OverallWidth: 810 mm
Pset_DoorCommon - IsExternal: no; Reference: 244 Innvendig BAa 8x21M - Tett
Pset_QuantityTakeOff - Reference: 244 Innvendig BAa 8x21M - Tett

# IfcDoor: Enfløyet:244 Innvendig CAb 10x21M - Glass - Heltre Ask, Enfløyet:244 Innvendig CAb 10x21M - Glass - Heltre Ask:4530625
In: PLAN 02
Type - OperationType: SINGLE_SWING_RIGHT; ParameterTakesPrecedence: no; Sizeable: no; Material: NO_Glass, Ask, Door - Handle
Type - Enfløyet:244 Innvendig CAb 10x21M - Glass - Heltre Ask:4530625:1 - PanelOperation: SWINGING
OverallHeight: 2100 mm; OverallWidth: 1010 mm
Pset_DoorCommon - IsExternal: no; Reference: 244 Innvendig CAb 10x21M - Glass - Heltre Ask
Pset_QuantityTakeOff - Reference: 244 Innvendig CAb 10x21M - Glass - Heltre Ask

# IfcDoor: Enfløyet:244 Innvendig CAb 11x21M - Glass - Heltre Ask, Enfløyet:244 Innvendig CAb 11x21M - Glass - Heltre Ask:2278295
In: PLAN 02
Type - OperationType: SINGLE_SWING_RIGHT; ParameterTakesPrecedence: no; Sizeable: no; Material: NO_Glass, Ask, Door - Handle
Type - Enfløyet:244 Innvendig CAb 11x21M - Glass - Heltre Ask:2278295:1 - PanelOperation: SWINGING
OverallHeight: 2100 mm; OverallWidth: 1110 mm
Pset_DoorCommon - IsExternal: no; Reference: 244 Innvendig CAb 11x21M - Glass - Heltre Ask
Pset_QuantityTakeOff - Reference: 244 Innvendig CAb 11x21M - Glass - Heltre Ask

# IfcDoor: Enfløyet:2441 Innvendig 10x21M (10)
Type - OperationType: SINGLE_SWING_RIGHT; ParameterTakesPrecedence: no; Sizeable: no; Material: Door - Leaf, Door - Handle, Door - Frame
Type - Enfløyet:2441 Innvendig 10x21M:1574782:1 - PanelOperation: SWINGING
OverallHeight: 2100 mm; OverallWidth: 1010 mm
Pset_DoorCommon - IsExternal: no; Reference: 2441 Innvendig 10x21M
Pset_QuantityTakeOff - Reference: 2441 Innvendig 10x21M
Name (Enfløyet:2441 Innvendig 10x21M:...) | In
1574782 | PLAN 01
1666559 | PLAN U1
1666729 | PLAN U1
1666929 | PLAN U1
1667076 | PLAN U1
1667631 | PLAN U1
1667819 | PLAN U1
1668133 | PLAN U1
4348157 | PLAN U1
4452298 | PLAN U1

# IfcDoor: Enfløyet:2441 Innvendig 10x21M (6)
In: PLAN U1
Type - OperationType: SINGLE_SWING_RIGHT; ParameterTakesPrecedence: no; Sizeable: no; Material: Door - Leaf, Door - Handle, Door - Frame
Type - Enfløyet:2441 Innvendig 10x21M:1667317:1 - PanelOperation: SWINGING
OverallHeight: 2100 mm; OverallWidth: 1010 mm
Pset_DoorCommon - IsExternal: no; Reference: 2441 Innvendig 10x21M
Pset_QuantityTakeOff - Reference: 2441 Innvendig 10x21M
Name (Enfløyet:2441 Innvendig 10x21M:...)
1667317
1667380
1667718
1667908
1668074
2427704

# IfcDoor: Enfløyet:2441 Innvendig 10x21M, Enfløyet:2441 Innvendig 10x21M:1667445
In: PLAN U1
Type - OperationType: SINGLE_SWING_RIGHT; ParameterTakesPrecedence: no; Sizeable: no; Material: Door - Leaf, Door - Handle, Door - Frame
Type - Enfløyet:2441 Innvendig 10x21M:1667445:1 - PanelOperation: SWINGING
OverallHeight: 2100 mm; OverallWidth: 1010 mm
Pset_DoorCommon - IsExternal: no; Reference: 2441 Innvendig 10x21M
Pset_QuantityTakeOff - Reference: 2441 Innvendig 10x21M

# IfcDoor: Enfløyet:2441 Innvendig 10x21M, Enfløyet:2441 Innvendig 10x21M:1948191
In: PLAN U1
Type - OperationType: SINGLE_SWING_RIGHT; ParameterTakesPrecedence: no; Sizeable: no; Material: Door - Leaf, Door - Handle, Door - Frame
Type - Enfløyet:2441 Innvendig 10x21M:1948191:1 - PanelOperation: SWINGING
OverallHeight: 2100 mm; OverallWidth: 1010 mm
Pset_DoorCommon - IsExternal: no; Reference: 2441 Innvendig 10x21M
Pset_QuantityTakeOff - Reference: 2441 Innvendig 10x21M

# IfcDoor: Enfløyet:2441 Innvendig 8x21M (3)
Type - OperationType: SINGLE_SWING_RIGHT; ParameterTakesPrecedence: no; Sizeable: no; Material: Door - Hvit, Door - Handle
Type - Enfløyet:2441 Innvendig 8x21M:1574822:1 - PanelOperation: SWINGING
OverallHeight: 2100 mm; OverallWidth: 810 mm
Pset_DoorCommon - IsExternal: no; Reference: 2441 Innvendig 8x21M
Pset_QuantityTakeOff - Reference: 2441 Innvendig 8x21M
Name (Enfløyet:2441 Innvendig 8x21M:...) | In
1574822 | PLAN 01
1669708 | PLAN U1
2708834 | PLAN U1

# IfcDoor: Enfløyet:2441 Innvendig 9x21M, Enfløyet:2441 Innvendig 9x21M:2716240
In: PLAN U1
Type - OperationType: SINGLE_SWING_RIGHT; ParameterTakesPrecedence: no; Sizeable: no; Material: Door - Hvit, Door - Handle
Type - Enfløyet:2441 Innvendig 9x21M:2716240:1 - PanelOperation: SWINGING
OverallHeight: 2100 mm; OverallWidth: 910 mm
Pset_DoorCommon - IsExternal: no; Reference: 2441 Innvendig 9x21M
Pset_QuantityTakeOff - Reference: 2441 Innvendig 9x21M

# IfcDoor: FOLDEVEGG:244 Innvendig, FOLDE 5400x2100, FOLDEVEGG:244 Innvendig, FOLDE 5400x2100:4348271
In: PLAN U1
Type - ParameterTakesPrecedence: no; Sizeable: no; Material: <Unnamed>
OverallHeight: 2181 mm; OverallWidth: 5400 mm
Pset_DoorCommon - IsExternal: no; Reference: 244 Innvendig, FOLDE 5400x2100
Pset_QuantityTakeOff - Reference: 244 Innvendig, FOLDE 5400x2100

# IfcDoor: Garasjeport:234 Utvendig, Port 6100x3500, Garasjeport:234 Utvendig, Port 6100x3500:1773965
In: PLAN 01
Type - ParameterTakesPrecedence: no; Sizeable: no; Material: A_Finish_Paint_LC 4320h - Gris 59_Matte, <Unnamed>
OverallHeight: 3000 mm; OverallWidth: 6100 mm
Pset_DoorCommon - IsExternal: yes; Reference: 234 Utvendig, Port 6100x3500
Pset_QuantityTakeOff - Reference: 234 Utvendig, Port 6100x3500

# IfcDoor: Glassfelt-m_dør:244 Innvendig GJb 16x21M (10x21M) - Glass - Heltre Ask, Glassfelt-m_dør:244 Innvendig GJb 16x21M (10x21M) - Glass - Heltre Ask:2774136
In: PLAN 02
Type - ParameterTakesPrecedence: no; Sizeable: no; Material: NO_Glass, Ask, Door - Handle
OverallHeight: 2100 mm; OverallWidth: 1610 mm
Pset_DoorCommon - IsExternal: no; Reference: 244 Innvendig GJb 16x21M (10x21M) - Glass - Heltre Ask
Pset_QuantityTakeOff - Reference: 244 Innvendig GJb 16x21M (10x21M) - Glass - Heltre Ask

# IfcDoor: Glassfelt-m_dør:244 Innvendig GJb 20x21M (10x21M) - Glass - Heltre Ask (5)
In: PLAN 02
Type - ParameterTakesPrecedence: no; Sizeable: no; Material: NO_Glass, Ask, Door - Handle
OverallHeight: 2100 mm; OverallWidth: 2010 mm
Pset_DoorCommon - IsExternal: no; Reference: 244 Innvendig GJb 20x21M (10x21M) - Glass - Heltre Ask
Pset_QuantityTakeOff - Reference: 244 Innvendig GJb 20x21M (10x21M) - Glass - Heltre Ask
Name (Glassfelt-m_dør:244 Innvendig GJb 20x21M (10x21M) - Glass - Heltre Ask:...)
2278041
2278128
2774098
2774102
4554475

# IfcDoor: Heis:Heis 2 Sengeheis, Heis:Heis 2 Sengeheis:1757178
In: PLAN 01
Type - ParameterTakesPrecedence: no; Sizeable: no; Material: <Unnamed>, Aluminium Lakkert RAL 7021
OverallHeight: 2380 mm; OverallWidth: 1200 mm
Pset_DoorCommon - IsExternal: no; Reference: Heis 2 Sengeheis
Pset_QuantityTakeOff - Reference: Heis 2 Sengeheis

# IfcDoor: Inv-Glassfelt:244 Innvendig GH 20x12M, Inv-Glassfelt:244 Innvendig GH 20x12M:2854204
In: PLAN 01
Type - ParameterTakesPrecedence: no; Sizeable: no; Material: NO_Glass, RAL 7006
OverallHeight: 1210 mm; OverallWidth: 2010 mm
Pset_DoorCommon - IsExternal: no; Reference: 244 Innvendig GH 20x12M
Pset_QuantityTakeOff - Reference: 244 Innvendig GH 20x12M

# IfcDoor: Inv-Hjørnevindu-2 sider:244 Innvendig, SL (5+17)x13M - Hjørne 2 sider, Inv-Hjørnevindu-2 sider:244 Innvendig, SL (5+17)x13M - Hjørne 2 sider:3503942
In: PLAN 01
Type - ParameterTakesPrecedence: no; Sizeable: no; Material: RAL 7006, NO_Glass
OverallHeight: 1310 mm; OverallWidth: 1922.5 mm
Pset_DoorCommon - IsExternal: no; Reference: 244 Innvendig, SL (5+17)x13M - Hjørne 2 sider
Pset_QuantityTakeOff - Reference: 244 Innvendig, SL (5+17)x13M - Hjørne 2 sider

# IfcDoor: Likefløyet:234 Utvendig 18x21M - Glass, Likefløyet:234 Utvendig 18x21M - Glass:1666379
In: PLAN U1
Type - OperationType: DOUBLE_DOOR_SINGLE_SWING; ParameterTakesPrecedence: no; Sizeable: no; Material: NO_Glass, Door - Hvit, Door - Handle, Door - Frame
Type - Likefløyet:234 Utvendig 18x21M - Glass:1666379:1 - PanelOperation: SWINGING
OverallHeight: 2100 mm; OverallWidth: 1810 mm
Pset_DoorCommon - IsExternal: yes; Reference: 234 Utvendig 18x21M - Glass
Pset_QuantityTakeOff - Reference: 234 Utvendig 18x21M - Glass

# IfcDoor: Likefløyet:234 Utvendig YBc 18x21M - Firkantede vinduer, Likefløyet:234 Utvendig YBc 18x21M - Firkantede vinduer:1879763
In: PLAN 01
Type - OperationType: DOUBLE_DOOR_SINGLE_SWING; ParameterTakesPrecedence: no; Sizeable: no; Material: NO_Glass, Door - Beige, Door - Handle
Type - Likefløyet:234 Utvendig YBc 18x21M - Firkantede vinduer:1879763:1 - PanelOperation: SWINGING
OverallHeight: 2100 mm; OverallWidth: 1810 mm
Pset_DoorCommon - IsExternal: yes; Reference: 234 Utvendig YBc 18x21M - Firkantede vinduer
Pset_QuantityTakeOff - Reference: 234 Utvendig YBc 18x21M - Firkantede vinduer

# IfcDoor: Likefløyet:234 Utvendig YBc 18x21M - Firkantede vinduer, Likefløyet:234 Utvendig YBc 18x21M - Firkantede vinduer:1756957
In: PLAN 01
Type - ParameterTakesPrecedence: no; Sizeable: no; Material: NO_Glass, Door - Beige, Door - Handle
OverallHeight: 2100 mm; OverallWidth: 1810 mm
Pset_DoorCommon - IsExternal: yes; Reference: 234 Utvendig YBc 18x21M - Firkantede vinduer
Pset_QuantityTakeOff - Reference: 234 Utvendig YBc 18x21M - Firkantede vinduer

# IfcDoor: Likefløyet:244 Innvendig ABa 11x21M - Tett, Likefløyet:244 Innvendig ABa 11x21M - Tett:2093468
In: PLAN 01
Type - OperationType: DOUBLE_DOOR_SINGLE_SWING; ParameterTakesPrecedence: no; Sizeable: no; Material: Door - Beige, Door - Handle, Door - Frame
Type - Likefløyet:244 Innvendig ABa 11x21M - Tett:2093468:1 - PanelOperation: SWINGING
OverallHeight: 2100 mm; OverallWidth: 1110 mm
Pset_DoorCommon - IsExternal: no; Reference: 244 Innvendig ABa 11x21M - Tett
Pset_QuantityTakeOff - Reference: 244 Innvendig ABa 11x21M - Tett

# IfcDoor: Likefløyet:244 Innvendig ABa 14x21M - Tett, Likefløyet:244 Innvendig ABa 14x21M - Tett:2288382
In: PLAN 01
Type - OperationType: DOUBLE_DOOR_SINGLE_SWING; ParameterTakesPrecedence: no; Sizeable: no; Material: Door - Beige, Door - Handle
Type - Likefløyet:244 Innvendig ABa 14x21M - Tett:2288382:1 - PanelOperation: SWINGING
OverallHeight: 2100 mm; OverallWidth: 1410 mm
Pset_DoorCommon - IsExternal: no; Reference: 244 Innvendig ABa 14x21M - Tett
Pset_QuantityTakeOff - Reference: 244 Innvendig ABa 14x21M - Tett

# IfcDoor: Likefløyet:244 Innvendig ABa 16x21M - Tett (2)
In: PLAN 01
Type - OperationType: DOUBLE_DOOR_SINGLE_SWING; ParameterTakesPrecedence: no; Sizeable: no; Material: Door - Hvit, Door - Handle
Type - Likefløyet:244 Innvendig ABa 16x21M - Tett:2091980:1 - PanelOperation: SWINGING
OverallHeight: 2100 mm; OverallWidth: 1610 mm
Pset_DoorCommon - IsExternal: no; Reference: 244 Innvendig ABa 16x21M - Tett
Pset_QuantityTakeOff - Reference: 244 Innvendig ABa 16x21M - Tett
Name (Likefløyet:244 Innvendig ABa 16x21M - Tett:...)
2091980
2092200

# IfcDoor: Likefløyet:2441 Innvendig 18x21M - Glass, Likefløyet:2441 Innvendig 18x21M - Glass:1666482
In: PLAN U1
Type - OperationType: DOUBLE_DOOR_SINGLE_SWING; ParameterTakesPrecedence: no; Sizeable: no; Material: NO_Glass, Door - Hvit, Door - Handle
Type - Likefløyet:2441 Innvendig 18x21M - Glass:1666482:1 - PanelOperation: SWINGING
OverallHeight: 2100 mm; OverallWidth: 1810 mm
Pset_DoorCommon - IsExternal: no; Reference: 2441 Innvendig 18x21M - Glass
Pset_QuantityTakeOff - Reference: 2441 Innvendig 18x21M - Glass

# IfcDoor: Likefløyet:2441 Innvendig ABc 16x21M - Firkantete vinduer - Grå (2)
In: PLAN 01
Type - OperationType: DOUBLE_DOOR_SINGLE_SWING; ParameterTakesPrecedence: no; Sizeable: no; Material: NO_Glass, formica_Citadel, Door - Handle
Type - Likefløyet:2441 Innvendig ABc 16x21M - Firkantete vinduer - Grå:2255655:1 - PanelOperation: SWINGING
OverallHeight: 2100 mm; OverallWidth: 1610 mm
Pset_DoorCommon - IsExternal: no; Reference: 2441 Innvendig ABc 16x21M - Firkantete vinduer - Grå
Pset_QuantityTakeOff - Reference: 2441 Innvendig ABc 16x21M - Firkantete vinduer - Grå
Name (Likefløyet:2441 Innvendig ABc 16x21M - Firkantete vinduer - Grå:...)
2255655
2353663

# IfcDoor: Likefløyet:2441 Innvendig ABc 18x21M - Firkantete vinduer, Likefløyet:2441 Innvendig ABc 18x21M - Firkantete vinduer:3670602
In: PLAN 01
Type - OperationType: DOUBLE_DOOR_SINGLE_SWING; ParameterTakesPrecedence: no; Sizeable: no; Material: NO_Glass, Door - Beige, Door - Handle
Type - Likefløyet:2441 Innvendig ABc 18x21M - Firkantete vinduer:3670602:1 - PanelOperation: SWINGING
OverallHeight: 2100 mm; OverallWidth: 1810 mm
Pset_DoorCommon - IsExternal: no; Reference: 2441 Innvendig ABc 18x21M - Firkantete vinduer
Pset_QuantityTakeOff - Reference: 2441 Innvendig ABc 18x21M - Firkantete vinduer

# IfcDoor: Luke-Lab:244 Luke, Lab, 4x4M, Luke-Lab:244 Luke, Lab, 4x4M:1920811
In: PLAN 01
Type - ParameterTakesPrecedence: no; Sizeable: no; Material: N_Door - Handle, Door - Frame
OverallHeight: 410 mm; OverallWidth: 410 mm
Pset_DoorCommon - IsExternal: no; Reference: 244 Luke, Lab, 4x4M
Pset_QuantityTakeOff - Reference: 244 Luke, Lab, 4x4M

# IfcDoor: Skyvedør (Innfelt):244 Innvendig AFb 10x21M - Glass-tre (2)
In: PLAN 01
Type - ParameterTakesPrecedence: no; Sizeable: no; Material: NO_Glass, Ask, N_Door - Handle
OverallHeight: 2100 mm; OverallWidth: 967 mm
Pset_DoorCommon - IsExternal: no; Reference: 244 Innvendig AFb 10x21M - Glass-tre
Pset_QuantityTakeOff - Reference: 244 Innvendig AFb 10x21M - Glass-tre
Name (Skyvedør (Innfelt):244 Innvendig AFb 10x21M - Glass-tre:...)
1833604
1917043

# IfcDoor: Skyvedør (Utenpå):244 Innvendig, ADa 10x21M (2)
In: PLAN 01
Type - ParameterTakesPrecedence: no; Sizeable: no; Material: N_Door - Leaf, N_Door - Frame
Type - Pset_ConcreteElementGeneral - FireRating: -
Type - Pset_DoorCommon - FireRating: -
OverallHeight: 2100 mm; OverallWidth: 1010 mm
Pset_DoorCommon - IsExternal: no; Reference: 244 Innvendig, ADa 10x21M
Pset_QuantityTakeOff - Reference: 244 Innvendig, ADa 10x21M
Name (Skyvedør (Utenpå):244 Innvendig, ADa 10x21M:...)
1695699
1900430

# IfcDoor: Skyvedør (Utenpå):244 Innvendig, ADa 9x21M (3)
In: PLAN 01
Type - ParameterTakesPrecedence: no; Sizeable: no; Material: N_Door - Leaf, N_Door - Frame
Type - Pset_ConcreteElementGeneral - FireRating: -
Type - Pset_DoorCommon - FireRating: -
OverallHeight: 2100 mm; OverallWidth: 910 mm
Pset_DoorCommon - IsExternal: no; Reference: 244 Innvendig, ADa 9x21M
Pset_QuantityTakeOff - Reference: 244 Innvendig, ADa 9x21M
Name (Skyvedør (Utenpå):244 Innvendig, ADa 9x21M:...)
1695923
1920051
2522133

# IfcDoor: Skyvedør Akutt:Skyvedør Akutt ADa, Skyvedør Akutt:Skyvedør Akutt ADa:3444249
In: PLAN 01
Type - ParameterTakesPrecedence: no; Sizeable: no; Material: N_Door - Leaf, Overflate-Hvit, aluminium
OverallHeight: 609.6 mm; OverallWidth: 3875 mm
Pset_DoorCommon - IsExternal: no; Reference: Skyvedør Akutt ADa
Pset_QuantityTakeOff - Reference: Skyvedør Akutt ADa

# IfcDoor: Skyveluke:244 Innvendig Skyveluke, SL 12x13M, Skyveluke:244 Innvendig Skyveluke, SL 12x13M:2043682
In: PLAN 01
Type - ParameterTakesPrecedence: no; Sizeable: no; Material: RAL 7006, NO_Glass
OverallHeight: 1310 mm; OverallWidth: 1210 mm
Pset_DoorCommon - IsExternal: no; Reference: 244 Innvendig Skyveluke, SL 12x13M
Pset_QuantityTakeOff - Reference: 244 Innvendig Skyveluke, SL 12x13M

# IfcDoor: Ulikefløyet-m_overfelt:234 Utvendig ZCb 14x25M - Glass, Ulikefløyet-m_overfelt:234 Utvendig ZCb 14x25M - Glass:4285019
In: PLAN 01
Type - OperationType: DOUBLE_DOOR_SINGLE_SWING; ParameterTakesPrecedence: no; Sizeable: no; Material: NO_Glass, RAL 7006, Door - Handle
Type - Ulikefløyet-m_overfelt:234 Utvendig ZCb 14x25M - Glass:4285019:1 - PanelOperation: SWINGING
OverallHeight: 2500 mm; OverallWidth: 1410 mm
Pset_DoorCommon - IsExternal: yes; Reference: 234 Utvendig ZCb 14x25M - Glass
Pset_QuantityTakeOff - Reference: 234 Utvendig ZCb 14x25M - Glass

# IfcDoor: Ulikefløyet-m_overfelt:244 Innvendig LCb14x25M - Glass, Ulikefløyet-m_overfelt:244 Innvendig LCb14x25M - Glass:3293013
In: PLAN 01
Type - OperationType: SINGLE_SWING_RIGHT; ParameterTakesPrecedence: no; Sizeable: no; Material: NO_Glass, RAL 7006, Door - Handle
Type - Ulikefløyet-m_overfelt:244 Innvendig LCb14x25M - Glass:3293013:1 - PanelOperation: SWINGING
OverallHeight: 2500 mm; OverallWidth: 1410 mm
Pset_DoorCommon - IsExternal: no; Reference: 244 Innvendig LCb14x25M - Glass
Pset_QuantityTakeOff - Reference: 244 Innvendig LCb14x25M - Glass

# IfcDoor: Ulikefløyet:244 Innvendig ACa 13x21M - Tett Grå (2)
In: PLAN 01
Type - OperationType: DOUBLE_DOOR_SINGLE_SWING; ParameterTakesPrecedence: no; Sizeable: no; Material: formica_Citadel, Door - Handle
Type - Ulikefløyet:244 Innvendig ACa 13x21M - Tett Grå:1699249:1 - PanelOperation: SWINGING
OverallHeight: 2100 mm; OverallWidth: 1310 mm
Pset_DoorCommon - IsExternal: no; Reference: 244 Innvendig ACa 13x21M - Tett Grå
Pset_QuantityTakeOff - Reference: 244 Innvendig ACa 13x21M - Tett Grå
Name (Ulikefløyet:244 Innvendig ACa 13x21M - Tett Grå:...)
1699249
4929241

# IfcFlowTerminal: 310-Toalett på vegg:Toalett på vegg (3)
Type - Material: Finishes - Interior - Porcelain, Default, <Unnamed>
Pset_DistributionFlowElementCommon - Reference: Toalett på vegg; sets with these values: 2
Name (310-Toalett på vegg:Toalett på vegg:...) | In
2016079 | B4-422
2713513 | B5-420A
2723742 | B5-420A

# IfcFlowTerminal: 310-Vask_utslag:Utslagskum (3)
Type - Material: Metal - Steel, Polished
Pset_DistributionFlowElementCommon - Reference: Utslagskum; sets with these values: 2
Name (310-Vask_utslag:Utslagskum:...) | In
3053602 | B4-413
3053940 | B5-413
3340997 | B5-302

# IfcFlowTerminal: 310-Vask_utslag:Utslagsvask m_bøtterist, 310-Vask_utslag:Utslagsvask m_bøtterist:2944040
In: B4-408A
Type - Material: Metal - Steel, Polished, <Unnamed>
Pset_DistributionFlowElementCommon - Reference: Utslagsvask m_bøtterist; sets with these values: 2

# IfcFlowTerminal: 314-Dusjarmatur-vegg:Dusjarmatur (5)
Type - Material: <Unnamed>
Pset_DistributionFlowElementCommon - Reference: Dusjarmatur; sets with these values: 2
Name (314-Dusjarmatur-vegg:Dusjarmatur:...) | In
1803448 | B5-304
2010804 | B4-411
2713481 | B5-420B
2713518 | B5-421B
2715439 | B5-420

# IfcFlowTerminal: 314-Hånddusj:Hånddusj (2)
Type - Material: <Unnamed>
Pset_DistributionFlowElementCommon - Reference: Hånddusj; sets with these values: 2
Name (314-Hånddusj:Hånddusj:...) | In
4760650 | B4-407
4770561 | B4-408

# IfcFlowTerminal: 315-Servant-HC:"Frisørvask" (2)
Type - Material: Metal-Steel, Finishes - Interior - Porcelain
Pset_DistributionFlowElementCommon - Reference: "Frisørvask"; sets with these values: 2
Name (315-Servant-HC:"Frisørvask":...) | In
1720857 | B4-407
4770559 | B4-408

# IfcFlowTerminal: 315-Servant-HC:Servant, HC (4)
Type - Material: Metal-Steel, Finishes - Interior - Porcelain
Pset_DistributionFlowElementCommon - Reference: Servant, HC; sets with these values: 2
Name (315-Servant-HC:Servant, HC:...) | In
1698491 | B4-423
2016384 | B4-411
2029327 | B5-304
2715438 | B5-420

# IfcFlowTerminal: 315-Servant-Liten:Servant, Liten (7)
Type - Material: Metal-Steel, Finishes - Interior - Porcelain
Pset_DistributionFlowElementCommon - Reference: Servant, Liten; sets with these values: 2
Name (315-Servant-Liten:Servant, Liten:...) | In
2016080 | B4-422
2029814 | B5-311A
2029937 | B5-311B
2723335 | B5-420A
2723611 | B5-420A
3713775 | B5-303
4166720 | WC:4167080

# IfcFlowTerminal: 315-WC-gulv-HC:HCWC-TEK 17 - 850mm (3)
Type - Material: Finishes - Interior - Porcelain, Default, <Unnamed>
Pset_DistributionFlowElementCommon - Reference: HCWC-TEK 17 - 850mm; sets with these values: 2
Name (315-WC-gulv-HC:HCWC-TEK 17 - 850mm:...) | In
1698621 | B4-423
2030105 | B5-304
2715437 | B5-420

# IfcFlowTerminal: 315-WC-gulv-HC:NS - 700mm, 315-WC-gulv-HC:NS - 700mm:1652922
In: B4-411
Type - Material: Finishes - Interior - Porcelain, Default, <Unnamed>
Pset_DistributionFlowElementCommon - Reference: NS - 700mm; sets with these values: 2

# IfcFlowTerminal: 315-WC-gulv:WC-gulv (3)
Type - Material: Finishes - Interior - Porcelain, Default
Pset_DistributionFlowElementCommon - Reference: WC-gulv; sets with these values: 2
Name (315-WC-gulv:WC-gulv:...) | In
2030371 | B5-311B
2030488 | B5-311A
4166706 | WC:4167080

# IfcFlowTerminal: 315-WC-vegg_u-sisterne:WC-vegg_u-sisterne, 315-WC-vegg_u-sisterne:WC-vegg_u-sisterne:3713774
In: B5-303
Type - Material: <Unnamed>, Finishes - Interior - Porcelain, Default
Pset_DistributionFlowElementCommon - Reference: WC-vegg_u-sisterne; sets with these values: 2

# IfcFlowTerminal: Maskin:Vaskemaskin, kluter og mopper, Maskin:Vaskemaskin, kluter og mopper:4322178
In: B4-413
Type - Material: <Unnamed>
Pset_DistributionFlowElementCommon - Reference: Vaskemaskin, kluter og mopper; sets with these values: 2

# IfcFlowTerminal: Maskin:Vaskemaskin, tøy, Maskin:Vaskemaskin, tøy:3035229
In: B5-419
Type - Material: Overflate-Hvit
Pset_DistributionFlowElementCommon - Reference: Vaskemaskin, tøy; sets with these values: 2

# IfcFlowTerminal: Servant Stor:Servant Stor (12)
Type - Material: Metal-Steel, Finishes - Interior - Porcelain
Pset_DistributionFlowElementCommon - Reference: Servant Stor; sets with these values: 2
Name (Servant Stor:Servant Stor:...) | In
1718779 | B4-404
1719183 | B4-403
1720406 | B4-417
1720714 | B4-425B
1833399 | B5-409
1920299 | B4-412
1921378 | B4-417A
2088175 | B4-425A
2101278 | B4-401
2256635 | B5-409A
2520968 | B4-407B
2738547 | B4-406

# IfcFlowTerminal: Slangetrommel:Slangetrommel, Slangetrommel:Slangetrommel:2114666
In: B4-408A
Type - Material: <Unnamed>
Pset_DistributionFlowElementCommon - Reference: Slangetrommel; sets with these values: 2

# IfcFlowTerminal: Sluk:Gulvsluk (200x200) (7)
Type - Material: <Unnamed>
Pset_DistributionFlowElementCommon - Reference: Gulvsluk (200x200); sets with these values: 2
Name (Sluk:Gulvsluk (200x200):...) | In
3410626 | B4-411
4395755 | B4-413
4397079 | B5-421B
4397263 | B5-420B
4397897 | B5-419
4690002 | B5-420
4690347 | B5-413

# IfcFlowTerminal: Vent-rist:Rist 2000x1200, Vent-rist:Rist 2000x1200:3625342
In: PLAN 02
Type - Material: Aluminum, Rist
Pset_DistributionFlowElementCommon - Reference: Rist 2000x1200; sets with these values: 2

# IfcFlowTerminal: void_sluk:Gulvbrønn, void_sluk:Gulvbrønn:4325131
In: B4-413
Type - Material: Slukrist
Pset_DistributionFlowElementCommon - Reference: Gulvbrønn; sets with these values: 2

# IfcFlowTerminal: void_sluk:Lokasse, void_sluk:Lokasse:4323903
In: B4-413
Type - Material: Slukrist
Pset_DistributionFlowElementCommon - Reference: Lokasse; sets with these values: 2

# IfcFurnishingElement: 0-Benkeplate med kum:Benkeplate, d600 m/kum b350xd400, 0-Benkeplate med kum:Benkeplate, d600 m/kum b350xd400:3180358
In: B4-425A
Type - Material: Metal - Steel, Polished, Grå laminat
Pset_QuantityTakeOff - Reference: Benkeplate, d600 m/kum b350xd400

# IfcFurnishingElement: 0-Benkeplate med kum:Benkeplate, d600 m/kum b500xd400, 0-Benkeplate med kum:Benkeplate, d600 m/kum b500xd400:3166269
In: B5-422
Type - Material: Metal - Steel, Polished, Grå laminat
Pset_QuantityTakeOff - Reference: Benkeplate, d600 m/kum b500xd400

# IfcFurnishingElement: 0-Benkeplate med kum:Benkeplate, d650 m/kum b500xd400, 0-Benkeplate med kum:Benkeplate, d650 m/kum b500xd400:2772845
In: B4-412
Type - Material: Metal - Steel, Polished, Grå laminat
Pset_QuantityTakeOff - Reference: Benkeplate, d650 m/kum b500xd400

# IfcFurnishingElement: 0-Høyskap, dobbelt:Høyskap b800xd400x2100, dobbelt, 0-Høyskap, dobbelt:Høyskap b800xd400x2100, dobbelt:2985972
In: B5-406
Type - Material: <Unnamed>, Overflate-Hvit
Pset_QuantityTakeOff - Reference: Høyskap b800xd400x2100, dobbelt

# IfcFurnishingElement: 0-Høyskap_Ovner:Høyskap b600xd600xh2100, V, 0-Høyskap_Ovner:Høyskap b600xd600xh2100, V:3457282
In: B5-422
Type - Material: <Unnamed>, Ask
Pset_QuantityTakeOff - Reference: Høyskap b600xd600xh2100, V

# IfcFurnishingElement: 0-Overskap, dobbelt:RF Overskap b700xd350xh700, 0-Overskap, dobbelt:RF Overskap b700xd350xh700:3652745
In: B4-412
Type - Material: <Unnamed>, Metal - Steel, Polished
Pset_QuantityTakeOff - Reference: RF Overskap b700xd350xh700

# IfcFurnishingElement: 0-Overskap, dobbelt:RF Overskap b700xd350xh700, låsbart, 0-Overskap, dobbelt:RF Overskap b700xd350xh700, låsbart:3652381
In: B4-412
Type - Material: <Unnamed>, Metal - Steel, Polished
Pset_QuantityTakeOff - Reference: RF Overskap b700xd350xh700, låsbart

# IfcFurnishingElement: 0-Overskap:Overskap b600xd350xh700, H (2)
In: B5-402
Type - Material: <Unnamed>, Ask
Pset_QuantityTakeOff - Reference: Overskap b600xd350xh700, H
Name (0-Overskap:Overskap b600xd350xh700, H:...)
3822649
3822706

# IfcFurnishingElement: 0-Overskap:Overskap b600xd350xh700, V, 0-Overskap:Overskap b600xd350xh700, V:3822767
In: B5-402
Type - Material: <Unnamed>, Ask
Pset_QuantityTakeOff - Reference: Overskap b600xd350xh700, V

# IfcFurnishingElement: 0-Underskap, dobbelt:Underskap avfall b1000xd600x900, dobbelt, 0-Underskap, dobbelt:Underskap avfall b1000xd600x900, dobbelt:2849928
In: B4-424B
Type - Material: <Unnamed>, Ask
Pset_QuantityTakeOff - Reference: Underskap avfall b1000xd600x900, dobbelt

# IfcFurnishingElement: 0-Underskap, dobbelt:Underskap b1200xd350xh600, dobbelt, 0-Underskap, dobbelt:Underskap b1200xd350xh600, dobbelt:4531116
In: B5-412
Type - Material: <Unnamed>, Ask
Pset_QuantityTakeOff - Reference: Underskap b1200xd350xh600, dobbelt

# IfcFurnishingElement: 0-Underskap-Skuffer:Underskap b600xd600, 2 skuffer (3)
In: B5-422
Type - Material: <Unnamed>, Ask
Pset_QuantityTakeOff - Reference: Underskap b600xd600, 2 skuffer
Name (0-Underskap-Skuffer:Underskap b600xd600, 2 skuffer:...)
3042779
3158425
3158448

# IfcFurnishingElement: 0-Underskap-Skuffer:Underskap b600xd600, 3 skuffer (2)
In: B5-402
Type - Material: <Unnamed>, Ask
Pset_QuantityTakeOff - Reference: Underskap b600xd600, 3 skuffer
Name (0-Underskap-Skuffer:Underskap b600xd600, 3 skuffer:...)
2808377
3397031

# IfcFurnishingElement: 0-Underskap-Skuffer:Underskap b600xd600, 4 skuffer, 0-Underskap-Skuffer:Underskap b600xd600, 4 skuffer:3158324
In: B5-422
Type - Material: <Unnamed>, Ask
Pset_QuantityTakeOff - Reference: Underskap b600xd600, 4 skuffer

# IfcFurnishingElement: 0-Underskap-Skuffer:Underskap b800xd600, 2 skuffer, 0-Underskap-Skuffer:Underskap b800xd600, 2 skuffer:2808788
In: B5-422
Type - Material: <Unnamed>, Ask
Pset_QuantityTakeOff - Reference: Underskap b800xd600, 2 skuffer

# IfcFurnishingElement: 0-Underskap-Skuffer_2:Underskap b600xd600, 4 skuffer, 0-Underskap-Skuffer_2:Underskap b600xd600, 4 skuffer:2798557
In: B4-425A
Type - Material: <Unnamed>, Ask
Pset_QuantityTakeOff - Reference: Underskap b600xd600, 4 skuffer

# IfcFurnishingElement: 0-Underskap-Skuffer_2:Underskap b600xd600, Sjalusi+2 skuffer, 0-Underskap-Skuffer_2:Underskap b600xd600, Sjalusi+2 skuffer:4099791
In: B4-425A
Type - Material: <Unnamed>, Ask, Aluminum
Pset_QuantityTakeOff - Reference: Underskap b600xd600, Sjalusi+2 skuffer

# IfcFurnishingElement: 0-Underskap:RF Underskap b600xd650xh600, H, 0-Underskap:RF Underskap b600xd650xh600, H:3652382
In: B4-412
Type - Material: <Unnamed>, Metal - Steel, Polished
Pset_QuantityTakeOff - Reference: RF Underskap b600xd650xh600, H

# IfcFurnishingElement: 0-Underskap:RF Underskap b600xd650xh600, V, 0-Underskap:RF Underskap b600xd650xh600, V:3653203
In: B4-412
Type - Material: <Unnamed>, Metal - Steel, Polished
Pset_QuantityTakeOff - Reference: RF Underskap b600xd650xh600, V

# IfcFurnishingElement: 0-Underskap:Underskap b400xd600, V, 0-Underskap:Underskap b400xd600, V:2848852
In: B4-408A
Type - Material: <Unnamed>, Overflate-Grå
Pset_QuantityTakeOff - Reference: Underskap b400xd600, V

# IfcFurnishingElement: 0-Underskap:Underskap b600xd600, H, 0-Underskap:Underskap b600xd600, H:3202416
In: B4-408A
Type - Material: <Unnamed>, Overflate-Grå
Pset_QuantityTakeOff - Reference: Underskap b600xd600, H

# IfcFurnishingElement: 0-Underskap:Underskap b600xd600, H, 0-Underskap:Underskap b600xd600, H:2787991
In: B4-425A
Type - Material: Ask, <Unnamed>
Pset_QuantityTakeOff - Reference: Underskap b600xd600, H

# IfcFurnishingElement: 0-Underskap:Underskap b600xd600, V, 0-Underskap:Underskap b600xd600, V:3483828
In: B5-419
Type - Material: <Unnamed>
Pset_QuantityTakeOff - Reference: Underskap b600xd600, V

# IfcFurnishingElement: 0-Underskap:Underskap b600xd600, V, 0-Underskap:Underskap b600xd600, V:2848854
In: B4-408A
Type - Material: <Unnamed>, Overflate-Grå
Pset_QuantityTakeOff - Reference: Underskap b600xd600, V

# IfcFurnishingElement: 274.019-Stellebord, nedfellbart fra vegg:Stellebord, nedfellbart (2)
Type - Material: <Unnamed>
Pset_QuantityTakeOff - Reference: Stellebord, nedfellbart
Name (274.019-Stellebord, nedfellbart fra vegg:Stellebord, nedfellbart:...) | In
2555615 | B4-423
2574859 | B5-304

# IfcFurnishingElement: 275 Lagerhyller (Gulvstående):Gulvstående lagerhyller (400x600x1750) (5)
Type - Material: <Unnamed>
Pset_QuantityTakeOff - Reference: Gulvstående lagerhyller (400x600x1750)
Name (275 Lagerhyller (Gulvstående):Gulvstående lagerhyller (400x600x1750):...) | In
2602813 | B4-412
2602920 | B4-412
2602928 | B4-412
2602936 | B4-412
3042358 | B5-413

# IfcFurnishingElement: 275 Lagerhyller (Gulvstående):Gulvstående lagerhyller (600x600x1750) (11)
Type - Material: <Unnamed>
Pset_QuantityTakeOff - Reference: Gulvstående lagerhyller (600x600x1750)
Name (275 Lagerhyller (Gulvstående):Gulvstående lagerhyller (600x600x1750):...) | In
2602350 | B4-412
2602573 | B4-412
2602581 | B4-412
2602591 | B4-412
2602712 | B4-412
2701159 | B4-413
2701278 | B4-413
2987747 | B5-417
2987748 | B5-417
2987756 | B5-417
2987757 | B5-417

# IfcFurnishingElement: 275 Lagerhyller (Gulvstående):Gulvstående lagerhyller (800x600) (4)
In: B5-417
Type - Material: <Unnamed>
Pset_QuantityTakeOff - Reference: Gulvstående lagerhyller (800x600)
Name (275 Lagerhyller (Gulvstående):Gulvstående lagerhyller (800x600):...)
2987744
2987745
2987753
2987754

# IfcFurnishingElement: 275-02x-Skuffeseksjon-KB:Skuffer KB-b455xd650, 3 skuffer (2)
In: B4-417A
Type - Material: Overflate-Hvit, <Unnamed>
Pset_QuantityTakeOff - Reference: Skuffer KB-b455xd650, 3 skuffer
Name (275-02x-Skuffeseksjon-KB:Skuffer KB-b455xd650, 3 skuffer:...)
3649263
3657652

# IfcFurnishingElement: 275-02x-Skuffeseksjon-KB:Skuffer KB-b455xd650, 4 skuffer (6)
Type - Material: Overflate-Hvit, <Unnamed>
Pset_QuantityTakeOff - Reference: Skuffer KB-b455xd650, 4 skuffer
Name (275-02x-Skuffeseksjon-KB:Skuffer KB-b455xd650, 4 skuffer:...) | In
2770682 | B4-407
2770683 | B4-407
2770684 | B4-407
4296985 | B4-408
4296986 | B4-408
4296987 | B4-408

# IfcFurnishingElement: 275-02x-Skuffeseksjon-KB:Skuffer KB-b650xd455 4 skuffer (2)
In: B4-417
Type - Material: Overflate-Hvit, <Unnamed>
Pset_QuantityTakeOff - Reference: Skuffer KB-b650xd455 4 skuffer
Name (275-02x-Skuffeseksjon-KB:Skuffer KB-b650xd455 4 skuffer:...)
2773782
2773783

# IfcFurnishingElement: 275-02x-Skuffeseksjon-KB:Skuffer KB-b650xd650, 3 skuffer, 275-02x-Skuffeseksjon-KB:Skuffer KB-b650xd650, 3 skuffer:3657662
In: B4-417A
Type - Material: Overflate-Hvit, <Unnamed>
Pset_QuantityTakeOff - Reference: Skuffer KB-b650xd650, 3 skuffer

# IfcFurnishingElement: 275-032-Underskap-KB:Underskap KB-b455x650xh900 (11)
Type - Material: <Unnamed>, Overflate-Hvit
Pset_QuantityTakeOff - Reference: Underskap KB-b455x650xh900
Name (275-032-Underskap-KB:Underskap KB-b455x650xh900:...) | In
2763610 | B4-407B
2763872 | B4-407B
2763922 | B4-407B
2764287 | B4-406
2764618 | B4-404
2764860 | B4-403
2771577 | B5-409
4842700 | B4-406
4842737 | B4-404
4842768 | B4-403
4842826 | B5-409

# IfcFurnishingElement: 275-0xx-Overskap-KB:Overskap KB-b455xd350xh650 Medisinskap m. kodelås, 275-0xx-Overskap-KB:Overskap KB-b455xd350xh650 Medisinskap m. kodelås:2751661
In: B4-407B
Type - Material: <Unnamed>, Overflate-Hvit
Pset_QuantityTakeOff - Reference: Overskap KB-b455xd350xh650 Medisinskap m. kodelås

# IfcFurnishingElement: 275-0xx-Overskap-KB_GLASS:Overskap KB-b455xd350xh650 -Glass (17)
Type - Material: <Unnamed>, Overflate-Hvit, NO_Glass
Pset_QuantityTakeOff - Reference: Overskap KB-b455xd350xh650 -Glass
Name (275-0xx-Overskap-KB_GLASS:Overskap KB-b455xd350xh650 -Glass:...) | In
2764519 | B4-406
2764581 | B4-406
2764621 | B4-404
2764622 | B4-404
2764863 | B4-403
2764864 | B4-403
2770746 | B4-407
2770747 | B4-407
2770748 | B4-407
2771579 | B5-409
2772688 | B4-417A
2772689 | B4-417A
2773785 | B4-417
3643773 | B4-417
4296989 | B4-408
4296990 | B4-408
4296991 | B4-408

# IfcFurnishingElement: 275-xxx-Høyskap-KB:Høyskap KB-b455xd650xh2100, Stål, Låsbare (6)
In: B4-419B
Type - Material: <Unnamed>, Metal - Steel, Polished
Pset_QuantityTakeOff - Reference: Høyskap KB-b455xd650xh2100, Stål, Låsbare
Name (275-xxx-Høyskap-KB:Høyskap KB-b455xd650xh2100, Stål, Låsbare:...)
2749930
2764085
2764101
2764135
2764219
2764227

# IfcFurnishingElement: 275-xxx-Høyskap-KB_GLASS:Høyskap KB-b455xd650xh2100-Glass (2)
Type - Material: <Unnamed>, Overflate-Hvit, NO_Glass
Pset_QuantityTakeOff - Reference: Høyskap KB-b455xd650xh2100-Glass
Name (275-xxx-Høyskap-KB_GLASS:Høyskap KB-b455xd650xh2100-Glass:...) | In
2770685 | B4-407
4296988 | B4-408

# IfcFurnishingElement: 2751 Skisseskap:Engangsbekkenkvern b600xd800xh900, 2751 Skisseskap:Engangsbekkenkvern b600xd800xh900:3254605
In: B4-412
Type - Material: <Unnamed>
Pset_QuantityTakeOff - Reference: Engangsbekkenkvern b600xd800xh900

# IfcFurnishingElement: 279 Knagger 5 stk:Knagger (5 stk) (5)
Type - Material: Metal - Chrome Polished, Kryssfiner, kantlist
Pset_QuantityTakeOff - Reference: Knagger (5 stk)
Name (279 Knagger 5 stk:Knagger (5 stk):...) | In
2713567 | B5-421
2713568 | B5-420
3034206 | B5-420
3034340 | B5-421
3036220 | B5-419

# IfcFurnishingElement: 279 Knagger:Knagger (2 stk) (18)
Type - Material: Metal - Chrome Polished, Kryssfiner, kantlist
Pset_QuantityTakeOff - Reference: Knagger (2 stk)
Name (279 Knagger:Knagger (2 stk):...) | In
2616052 | B4-423
2616562 | B4-417
2616788 | B4-422
2616880 | B4-425B
2771490 | B5-409
2805388 | B5-420A
2805480 | B5-421B
2805679 | B5-422
2805682 | B5-405
2805683 | B5-420
3034260 | B5-420B
3106303 | B5-409
3106334 | B5-408
3108711 | B5-420A
3114788 | B4-412
3114907 | B4-417A
3114941 | B4-425
4530595 | B5-406

# IfcFurnishingElement: 279 Knagger:Knagger (4 stk) (10)
Type - Material: Metal - Chrome Polished, Kryssfiner, kantlist
Pset_QuantityTakeOff - Reference: Knagger (4 stk)
Name (279 Knagger:Knagger (4 stk):...) | In
2617080 | B4-408
2617133 | B4-407
2617411 | B4-403
2617476 | B4-404
2617748 | B4-406
2617822 | B5-409A
3091710 | B4-409
3114994 | B4-425A
4555351 | B5-412
4948658 | B5-403

# IfcFurnishingElement: 279.xxx-Speil:Speil veggfast,280x670, 279.xxx-Speil:Speil veggfast,280x670:4958518
In: B4-413
Type - Material: <Unnamed>
Pset_QuantityTakeOff - Reference: Speil veggfast,280x670

# IfcFurnishingElement: 279.xxx-Speil:Speil veggfast,280x800 (18)
Type - Material: <Unnamed>
Pset_QuantityTakeOff - Reference: Speil veggfast,280x800
Name (279.xxx-Speil:Speil veggfast,280x800:...) | In
3339561 | B4-425A
3339625 | B4-425B
3339915 | B4-407B
3341071 | B5-311A
3341195 | B5-311B
4755156 | WC:4167080
4755334 | B5-303
4869333 | B4-412
4869336 | B4-417A
4869339 | B4-408
4869342 | B5-409
4869345 | B4-417
4869348 | B4-406
4869351 | B4-404
4869354 | B4-403
4869357 | B4-401
4869360 | B4-408A
4869363 | B5-409A

# IfcFurnishingElement: 279.xxx-Speil:Speil veggfast,400x1000, 279.xxx-Speil:Speil veggfast,400x1000:4078958
In: B5-409A
Type - Material: <Unnamed>
Pset_QuantityTakeOff - Reference: Speil veggfast,400x1000

# IfcFurnishingElement: 279.xxx-Speil:Speil veggfast,400x900 (3)
Type - Material: <Unnamed>
Pset_QuantityTakeOff - Reference: Speil veggfast,400x900
Name (279.xxx-Speil:Speil veggfast,400x900:...) | In
3374136 | B4-422
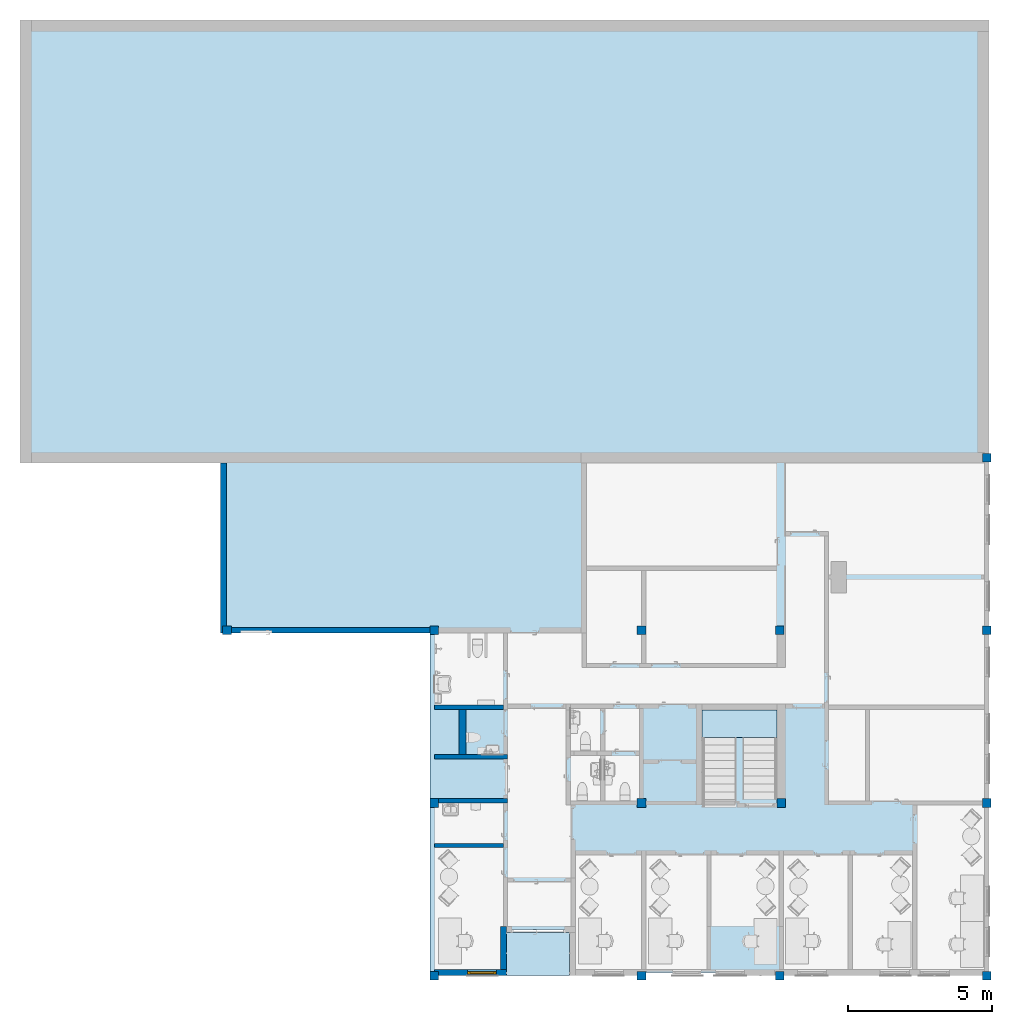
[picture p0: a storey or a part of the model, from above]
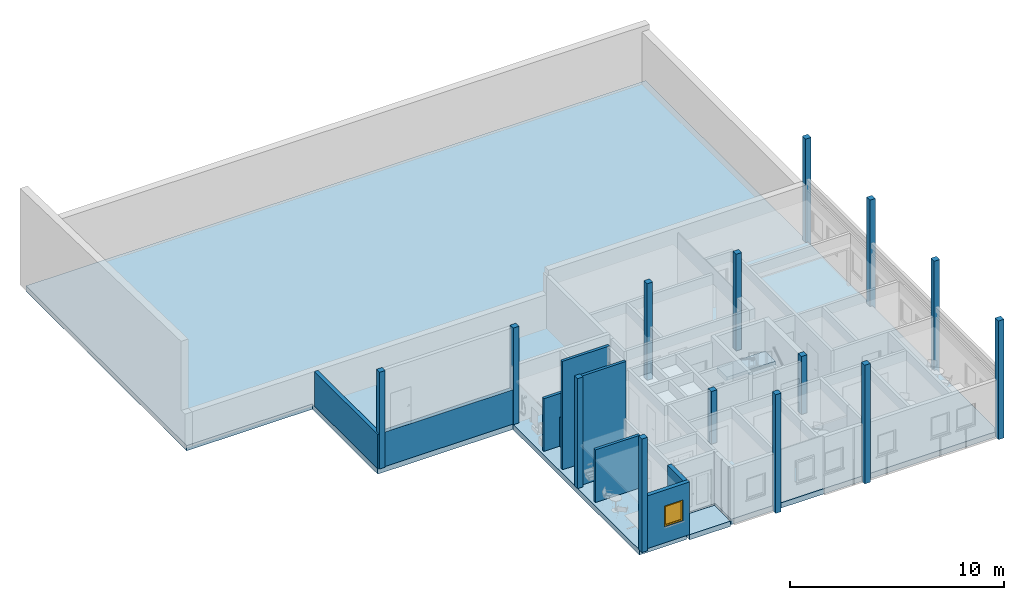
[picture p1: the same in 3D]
Properties of the parts of a building model (IFC2X3), part 3 of 4

# IfcFurnishingElement: 279.xxx-Speil:Speil veggfast,400x900 (3)
Name (279.xxx-Speil:Speil veggfast,400x900:...) | In
3374139 | B5-420A
3374140 | B5-420A

# IfcFurnishingElement: 279.xxx-Speil:Speil veggfast,600x600, 279.xxx-Speil:Speil veggfast,600x600:4227869
In: B4-407
Type - Material: <Unnamed>
Pset_QuantityTakeOff - Reference: Speil veggfast,600x600

# IfcFurnishingElement: 279.xxx-Speil:Speil veggfast,600x900 (4)
Type - Material: <Unnamed>
Pset_QuantityTakeOff - Reference: Speil veggfast,600x900
Name (279.xxx-Speil:Speil veggfast,600x900:...) | In
3321588 | B4-423
3337644 | B4-411
3340462 | B5-420
3341337 | B5-304

# IfcFurnishingElement: Arbeidsbord_Klynge_elektrisk_hevsenk:Klyngebord (2)
In: B5-421
Type - Material: Ask, Overflate-Hvit
Pset_QuantityTakeOff - Reference: Klyngebord
Name (Arbeidsbord_Klynge_elektrisk_hevsenk:Klyngebord:...) | Group
3041149 | Model Group:Klyngebord:3041162
3218296 | Model Group:Klyngebord:3218300

# IfcFurnishingElement: Arbeidsbord_elektrisk_hevsenk:Arb.bord 600x800, Arbeidsbord_elektrisk_hevsenk:Arb.bord 600x800:2660748
In: B4-425B
Type - Material: Metall, Plate
Pset_QuantityTakeOff - Reference: Arb.bord 600x800

# IfcFurnishingElement: Arbeidsbord_elektrisk_hevsenk:Arb.bord 800x1200 (3)
Type - Material: Metall, Plate
Pset_QuantityTakeOff - Reference: Arb.bord 800x1200
Name (Arbeidsbord_elektrisk_hevsenk:Arb.bord 800x1200:...) | In
2734127 | B4-403
2770767 | B4-406
2770772 | B4-404

# IfcFurnishingElement: Arbeidsbord_elektrisk_hevsenk:Arb.bord 800x1400 (7)
Type - Material: Metall, Plate
Pset_QuantityTakeOff - Reference: Arb.bord 800x1400
Name (Arbeidsbord_elektrisk_hevsenk:Arb.bord 800x1400:...) | In
1873776 | B5-403
1934769 | B5-409
2039118 | B5-406
2944021 | B5-408
4554639 | B5-403
4943748 | B5-403
4943754 | B5-403

# IfcFurnishingElement: Arbeidsbord_elektrisk_hevsenk:Arbbord 600x1000, Arbeidsbord_elektrisk_hevsenk:Arbbord 600x1000:2772225
In: B5-409
Type - Material: Metall, Plate
Pset_QuantityTakeOff - Reference: Arbbord 600x1000

# IfcFurnishingElement: Arbeidsbord_elektrisk_hevsenk:Arbbord 800x1600 (8)
Type - Material: Metall, Plate
Pset_QuantityTakeOff - Reference: Arbbord 800x1600
Name (Arbeidsbord_elektrisk_hevsenk:Arbbord 800x1600:...) | In
1939664 | PLAN U1
2420963 | B5-322
2420968 | B5-321
2420973 | PLAN U1
2710637 | Kontor:2708261
4172811 | B5-301
4173434 | B5-321
4452293 | B5-324

# IfcFurnishingElement: Arbeidsbord_hev-senk_elektrisk_hjørne:Arb.bord hjørne 600x2100x1600x800, Arbeidsbord_hev-senk_elektrisk_hjørne:Arb.bord hjørne 600x2100x1600x800:2776311
In: B4-425C
Type - Material: Metall, Ask
Pset_QuantityTakeOff - Reference: Arb.bord hjørne 600x2100x1600x800

# IfcFurnishingElement: Arbeidsbord_hev-senk_elektrisk_hjørne:Arb.bord hjørne 700x1300x1550x700 (2)
In: B4-425A
Type - Material: Metall, Ask
Pset_QuantityTakeOff - Reference: Arb.bord hjørne 700x1300x1550x700
Name (Arbeidsbord_hev-senk_elektrisk_hjørne:Arb.bord hjørne 700x1300x1550x700:...)
4939348
4939689

# IfcFurnishingElement: Arbeidsstol, rund polstret sete med fotring:Arbeidsstol, rund m/rygg, Arbeidsstol, rund polstret sete med fotring:Arbeidsstol, rund m/rygg:2739529
In: B4-407B
Type - Material: Metall, Stoff
Pset_QuantityTakeOff - Reference: Arbeidsstol, rund m/rygg

# IfcFurnishingElement: Arbstol_rund:Arb.stol med hjul (8)
Type - Material: Metall, Stoff
Type - Pset_ManufacturerTypeInformation - Manufacturer: Savo - joi studio 59-80 sitteh. m/intergralskum
Pset_QuantityTakeOff - Reference: Arb.stol med hjul
Name (Arbstol_rund:Arb.stol med hjul:...) | In
1759260 | B4-406
1759664 | B4-403
1760802 | B4-417A
1760871 | B4-417
1890698 | B5-409
2558418 | B4-408
2559112 | B4-407
2771372 | B4-404

# IfcFurnishingElement: Avfallsstativ, vegghengt lukket:Avfallsbøtte, vegghengt lukket (14)
Type - Material: <Unnamed>
Pset_QuantityTakeOff - Reference: Avfallsbøtte, vegghengt lukket
Name (Avfallsstativ, vegghengt lukket:Avfallsbøtte, vegghengt lukket:...) | In
2580036 | B5-302
2581127 | B5-409
2582824 | B5-406
2944030 | B5-408
3108363 | B5-421
3108687 | B5-420
3340788 | B5-420A
3340853 | B5-420A
3341070 | B5-311A
3341213 | B5-311B
4531033 | B5-412
4755155 | WC:4167080
4755347 | B5-303
4943271 | B5-405

# IfcFurnishingElement: Avfallsstativ, vegghengt:Avfallsstativ, vegghengt (22)
Type - Material: <Unnamed>
Pset_QuantityTakeOff - Reference: Avfallsstativ, vegghengt
Name (Avfallsstativ, vegghengt:Avfallsstativ, vegghengt:...) | In
3338985 | B4-417A
3339662 | B4-425A
3339768 | B4-425B
4645031 | B4-425C
4668840 | B4-412
4701998 | B4-407B
4708156 | B4-422
4714291 | B4-423
4714294 | B4-411
4714296 | B5-420
4714298 | B5-304
4720503 | B4-407
4869338 | B4-408
4869341 | B5-409
4869347 | B4-406
4869353 | B4-403
4869359 | B4-408A
4869362 | B5-409A
4869370 | B4-401
4869377 | B4-404
4875640 | B4-412
4875707 | B4-417

# IfcFurnishingElement: Benkeplate, variabel lengde:Benkeplate D350, Benkeplate, variabel lengde:Benkeplate D350:4531117
In: B5-412
Type - Material: Grå laminat
Pset_QuantityTakeOff - Reference: Benkeplate D350

# IfcFurnishingElement: Benkeplate, variabel lengde:Benkeplate D450, Benkeplate, variabel lengde:Benkeplate D450:2773784
In: B4-417
Type - Material: Grå laminat
Pset_QuantityTakeOff - Reference: Benkeplate D450

# IfcFurnishingElement: Benkeplate, variabel lengde:Benkeplate D500, Benkeplate, variabel lengde:Benkeplate D500:2988037
In: B5-419
Type - Material: <Unnamed>
Pset_QuantityTakeOff - Reference: Benkeplate D500

# IfcFurnishingElement: Benkeplate, variabel lengde:Benkeplate D600, Benkeplate, variabel lengde:Benkeplate D600:3484410
In: B5-419
Type - Material: <Unnamed>
Pset_QuantityTakeOff - Reference: Benkeplate D600

# IfcFurnishingElement: Benkeplate, variabel lengde:Benkeplate D600 (3)
Type - Material: Grå laminat
Pset_QuantityTakeOff - Reference: Benkeplate D600
Name (Benkeplate, variabel lengde:Benkeplate D600:...) | In
2813078 | B5-402
2848836 | B4-408A
3234910 | B4-424B

# IfcFurnishingElement: Benkeplate, variabel lengde:Benkeplate D650 (9)
Type - Material: Grå laminat
Pset_QuantityTakeOff - Reference: Benkeplate D650
Name (Benkeplate, variabel lengde:Benkeplate D650:...) | In
2748168 | B4-407B
2763386 | B4-407B
2764443 | B4-406
2764620 | B4-404
2764862 | B4-403
2765838 | B4-407
2770677 | B4-408
2771578 | B5-409
2772471 | B4-417A

# IfcFurnishingElement: Bokhylle-lav:Bokhylle, b800, d400, h1100 (2)
In: B5-421
Type - Material: Overflate-Hvit
Pset_QuantityTakeOff - Reference: Bokhylle, b800, d400, h1100
Name (Bokhylle-lav:Bokhylle, b800, d400, h1100:...)
2999397
2999398

# IfcFurnishingElement: Bokhylle-lav:Bokhylle, b800, d400, h900 (2)
In: B5-403
Type - Material: Overflate-Hvit
Pset_QuantityTakeOff - Reference: Bokhylle, b800, d400, h900
Name (Bokhylle-lav:Bokhylle, b800, d400, h900:...)
4945381
4945697

# IfcFurnishingElement: Bokhylle:Bokhylle, b800, d400, h1800 (8)
Type - Material: Overflate-Hvit
Pset_QuantityTakeOff - Reference: Bokhylle, b800, d400, h1800
Name (Bokhylle:Bokhylle, b800, d400, h1800:...) | In
2089135 | B5-409
2089136 | B5-409
2944026 | B5-408
2944027 | B5-408
4948310 | B5-403
4948330 | B5-403
4948406 | B5-403
4948407 | B5-403

# IfcFurnishingElement: Bokhylle:Bokhylle, b800, d400, h2100, Bokhylle:Bokhylle, b800, d400, h2100:2944009
In: B5-406
Type - Material: Overflate-Hvit
Pset_QuantityTakeOff - Reference: Bokhylle, b800, d400, h2100

# IfcFurnishingElement: Bord-rundt:Bord, Ø600 (14)
Type - Material: Plate, Metall
Type - Pset_ManufacturerTypeInformation - Manufacturer: Albin i Hyssna - Alex standardbeis m/laminatplate
Pset_QuantityTakeOff - Reference: Bord, Ø600
Name (Bord-rundt:Bord, Ø600:...) | In
1875839 | B5-422
1934771 | B5-409
1939666 | PLAN U1
2102430 | B4-425A
2420965 | B5-322
2420970 | B5-321
2420975 | PLAN U1
2710639 | B5-301
2725278 | B5-416
2944023 | B5-408
3042587 | B5-421
4173376 | Kontor:2708261
4452295 | B5-324
4948430 | B5-403

# IfcFurnishingElement: Bord:Møtebord lite 1200x600mm (6)
In: B5-412
Type - Material: Metall, Plate
Pset_QuantityTakeOff - Reference: Møtebord lite 1200x600mm
Name (Bord:Møtebord lite 1200x600mm:...)
4554251
4554252
4554253
4554254
4554255
4554256

# IfcFurnishingElement: Bord:Møteromsbord, 1600x900mm (2)
In: B5-422
Type - Material: Metall, Plate
Pset_QuantityTakeOff - Reference: Møteromsbord, 1600x900mm
Name (Bord:Møteromsbord, 1600x900mm:...)
1770361
2011986

# IfcFurnishingElement: Dispenser, papir:Dispenser, papir (26)
Type - Material: <Unnamed>
Pset_QuantityTakeOff - Reference: Dispenser, papir
Name (Dispenser, papir:Dispenser, papir:...) | In
3374975 | B5-420A
3374976 | B5-420A
4701994 | B4-425A
4701995 | B4-425B
4701997 | B4-407B
4702000 | B5-311A
4702002 | B5-311B
4708155 | B4-422
4714290 | B4-423
4714293 | B4-411
4714295 | B5-420
4714297 | B5-304
4720502 | B4-407
4755157 | WC:4167080
4755335 | B5-303
4869331 | B4-412
4869334 | B4-417A
4869337 | B4-408
4869340 | B5-409
4869343 | B4-417
4869346 | B4-406
4869349 | B4-404
4869352 | B4-403
4869355 | B4-401
4869358 | B4-408A
4869361 | B5-409A

# IfcFurnishingElement: Dispenser_såpe-sprit:Dispenser, Sprit, Dispenser_såpe-sprit:Dispenser, Sprit:4687267
In: B4-425C
Type - Material: <Unnamed>
Pset_QuantityTakeOff - Reference: Dispenser, Sprit

# IfcFurnishingElement: Firkantet bord kryssfot:Talerstol_600x 600, Firkantet bord kryssfot:Talerstol_600x 600:4531057
In: B5-412
Type - Material: <Unnamed>
Pset_QuantityTakeOff - Reference: Talerstol_600x 600

# IfcFurnishingElement: Forheng_med_skinne:Forheng, takmontert skinne (3)
In: B4-401
Type - Material: Stoff, Metall
Pset_QuantityTakeOff - Reference: Forheng, takmontert skinne
Name (Forheng_med_skinne:Forheng, takmontert skinne:...)
4553103
4557434
4608364

# IfcFurnishingElement: Foring:Foring (3)
Type - Material: <Unnamed>
Pset_QuantityTakeOff - Reference: Foring
Name (Foring:Foring:...) | In
4688700 | B4-419B
4689051 | B4-419B
4764004 | B4-408A

# IfcFurnishingElement: Foring:Foring, Ask (2)
In: B5-422
Type - Material: Ask
Pset_QuantityTakeOff - Reference: Foring, Ask
Name (Foring:Foring, Ask:...)
3173818
3175045

# IfcFurnishingElement: Garderobeskap_3 dører m. skohylle(Gulvstående):Garderobeskap 3 dører m skohylle 30x40 (17)
Type - Material: <Unnamed>
Pset_QuantityTakeOff - Reference: Garderobeskap 3 dører m skohylle 30x40
Name (Garderobeskap_3 dører m. skohylle(Gulvstående):Garderobeskap 3 dører m skohylle 30x40:...) | In
2713560 | B5-421
2713577 | B5-421
2713580 | B5-420
2713581 | B5-420
2713582 | B5-420
2724068 | B5-421
2724076 | B5-421
2724084 | B5-421
3033629 | B5-421
3033630 | B5-421
3033758 | B5-421
3033922 | B5-420
3033923 | B5-420
3033924 | B5-420
3033978 | B5-421
3034104 | B5-420
4849239 | B5-420

# IfcFurnishingElement: Garderobestang:Garderobestang (2)
Type - Material: <Unnamed>
Pset_QuantityTakeOff - Reference: Garderobestang
Name (Garderobestang:Garderobestang:...) | In
3098183 | B5-421
3098394 | B5-420

# IfcFurnishingElement: Glimakra_arrow-desk-screen:Skjermvegg (6)
In: B5-421
Type - Material: Aluminum, Tekstil beige
Type - Pset_ManufacturerTypeInformation - Manufacturer: Limbus deskup arrow 640x1038
Pset_QuantityTakeOff - Reference: Skjermvegg
Name (Glimakra_arrow-desk-screen:Skjermvegg:...) | Group
3041602 | Model Group:Klyngebord:3041162
3041846 | Model Group:Klyngebord:3041162
3041883 | Model Group:Klyngebord:3041162
3218301 | Model Group:Klyngebord:3218300
3218302 | Model Group:Klyngebord:3218300
3218303 | Model Group:Klyngebord:3218300

# IfcFurnishingElement: Hylle, 2 stk, ok=2100, justerbar lengde:Hylle, 2 stk , d200, Hylle, 2 stk, ok=2100, justerbar lengde:Hylle, 2 stk , d200:3466667
In: B5-422
Type - Material: Overflate-Hvit
Pset_QuantityTakeOff - Reference: Hylle, 2 stk , d200

# IfcFurnishingElement: Hylle, 2 stk, ok=2100, justerbar lengde:Hylle, 2 stk , d400, ok=2100, justerbar lengde (2)
In: B4-409
Type - Material: <Unnamed>
Pset_QuantityTakeOff - Reference: Hylle, 2 stk , d400, ok=2100, justerbar lengde
Name (Hylle, 2 stk, ok=2100, justerbar lengde:Hylle, 2 stk , d400, ok=2100, justerbar lengde:...)
2798186
3091711

# IfcFurnishingElement: Hylle, 3 stk ,skråstiltehyller, h=1200, ok=2100, justerbar lengde:Hylle, Skråstilte hyller_medisin ok=2100, justerbar lengde, Hylle, 3 stk ,skråstiltehyller, h=1200, ok=2100, justerbar lengde:Hylle, Skråstilte hyller_medisin ok=2100, justerbar lengde:2669223
In: B4-407B
Type - Material: Overflate-Hvit
Pset_QuantityTakeOff - Reference: Hylle, Skråstilte hyller_medisin ok=2100, justerbar lengde

# IfcFurnishingElement: Hylle-Disk:Infodisk, Hylle-Disk:Infodisk:2670196
In: PLAN 01
Type - Material: Ask
Pset_QuantityTakeOff - Reference: Infodisk

# IfcFurnishingElement: Hylle-Disk_2:Infodisk, Hylle-Disk_2:Infodisk:3597307
In: B4-425
Type - Material: Ask
Pset_QuantityTakeOff - Reference: Infodisk

# IfcFurnishingElement: Hylle_enkel-Justerbar_bredde:Hylle enkel, d200 (3)
Type - Material: <Unnamed>
Pset_QuantityTakeOff - Reference: Hylle enkel, d200
Name (Hylle_enkel-Justerbar_bredde:Hylle enkel, d200:...) | In
2627289 | B4-423
2627741 | B4-417
2628173 | B4-425B

# IfcFurnishingElement: Hylle_enkel-Justerbar_bredde:Hylle enkel, d300 (2)
Type - Material: <Unnamed>
Pset_QuantityTakeOff - Reference: Hylle enkel, d300
Name (Hylle_enkel-Justerbar_bredde:Hylle enkel, d300:...) | In
3397017 | B4-425C
4869198 | 409

# IfcFurnishingElement: Hylle_enkel-Justerbar_bredde:Hylle enkel, d400, Hylle_enkel-Justerbar_bredde:Hylle enkel, d400:4080183
In: B4-425A
Type - Material: <Unnamed>
Pset_QuantityTakeOff - Reference: Hylle enkel, d400

# IfcFurnishingElement: Hylle_enkel-Justerbar_bredde:Rustfri hylle, d300, Hylle_enkel-Justerbar_bredde:Rustfri hylle, d300:3035728
In: B5-419
Type - Material: <Unnamed>
Pset_QuantityTakeOff - Reference: Rustfri hylle, d300

# IfcFurnishingElement: Hyller, ok=2100, justerbar lengde:Hylle, 2 stk , d300, ok=2100, justerbar lengde (3)
Type - Material: _Maling hvit
Pset_QuantityTakeOff - Reference: Hylle, 2 stk , d300, ok=2100, justerbar lengde
Name (Hyller, ok=2100, justerbar lengde:Hylle, 2 stk , d300, ok=2100, justerbar lengde:...) | In
2770760 | B4-403
2770770 | B4-406
2770775 | B4-404

# IfcFurnishingElement: Hyller, ok=2100, justerbar lengde:Hylle, 3 stk , d300, ok=2100, justerbar lengde (2)
Type - Material: _Maling Hvid
Pset_QuantityTakeOff - Reference: Hylle, 3 stk , d300, ok=2100, justerbar lengde
Name (Hyller, ok=2100, justerbar lengde:Hylle, 3 stk , d300, ok=2100, justerbar lengde:...) | In
3643755 | B4-412
4081676 | B4-417

# IfcFurnishingElement: Hyller, ok=2100, justerbar lengde:Hylle, 3 stk , d600, ok=2100, justerbar lengde (2)
Type - Material: <Unnamed>
Pset_QuantityTakeOff - Reference: Hylle, 3 stk , d600, ok=2100, justerbar lengde
Name (Hyller, ok=2100, justerbar lengde:Hylle, 3 stk , d600, ok=2100, justerbar lengde:...) | In
2775279 | B4-422B
2812403 | Oppbevaring O2:2806572

# IfcFurnishingElement: Hyller, ok=2100, justerbar lengde:Hylle, 6 stk , d600, ok=2100, justerbar lengde (2)
Type - Material: _Maling Hvid
Pset_QuantityTakeOff - Reference: Hylle, 6 stk , d600, ok=2100, justerbar lengde
Name (Hyller, ok=2100, justerbar lengde:Hylle, 6 stk , d600, ok=2100, justerbar lengde:...) | In
2771373 | B4-404B
2771375 | B4-403B

# IfcFurnishingElement: Håndløper og fendring:Bakplate (2)
Type - Material: Fender
Pset_QuantityTakeOff - Reference: Bakplate
Name (Håndløper og fendring:Bakplate:...) | In
4537720 | B5-422
4538221 | B4-425A

# IfcFurnishingElement: KJK-Micro:Micro i overskap, KJK-Micro:Micro i overskap:3462648
In: B5-422
Type - Material: ARK_73_UTRL_Glas_Tonat_Microvågsugn, ARK_73_UTRL_Metall_Generell borstad_Microvågsugn
Pset_QuantityTakeOff - Reference: Micro i overskap

# IfcFurnishingElement: KK-Kombiskap:Kombiskap, kjøl og frys, h1800, KK-Kombiskap:Kombiskap, kjøl og frys, h1800:3157943
In: B5-422
Type - Material: _Maling Hvid
Pset_QuantityTakeOff - Reference: Kombiskap, kjøl og frys, h1800

# IfcFurnishingElement: Komfyr:Komfyr, Komfyr:Komfyr:3457283
In: B5-422
Type - Material: _Metal, Aluminium, _Glas, sort, _Maling Hvid, _Maling hvid, glossy
Pset_QuantityTakeOff - Reference: Komfyr

# IfcFurnishingElement: Kontorstol_uten_arml:Kontorstol (29)
Type - Material: Metall, Stoff
Type - Pset_ManufacturerTypeInformation - Manufacturer: Savo soul mesh - Sete Fame rygg runner
Pset_QuantityTakeOff - Reference: Kontorstol
Name (Kontorstol_uten_arml:Kontorstol:...) | In
1722672 | B4-425A
1722725 | B4-425A
1873777 | B5-403
1934770 | B5-409
1939665 | PLAN U1
2039119 | B5-406
2420964 | B5-322
2420969 | B5-321
2420974 | PLAN U1
2558158 | B4-425B
2710638 | Kontor:2708261
2735417 | B4-403
2770769 | B4-406
2770774 | B4-404
2772227 | B5-409
2944022 | B5-408
3041150 | B5-421 | Group: Model Group:Klyngebord:3041162
3041154 | B5-421 | Group: Model Group:Klyngebord:3041162
3041158 | B5-421 | Group: Model Group:Klyngebord:3041162
3218297 | B5-421 | Group: Model Group:Klyngebord:3218300
3218298 | B5-421 | Group: Model Group:Klyngebord:3218300
3218299 | B5-421 | Group: Model Group:Klyngebord:3218300
4138811 | B4-425C
4172812 | B5-301
4173435 | B5-321
4452294 | B5-324
4554640 | B5-403
4943749 | B5-403
4943755 | B5-403

# IfcFurnishingElement: Kopimaskin:Kopimaskin, Kopimaskin:Kopimaskin:3822400
In: B5-402
Type - Material: _Maling Hvid, <Unnamed>
Type - Pset_FurnitureTypeCommon - Description: Printer, lille
Pset_QuantityTakeOff - Reference: Kopimaskin

# IfcFurnishingElement: Lenestol, hvile:Lenestol, hvile (2)
In: B5-421
Type - Material: <Unnamed>, Stoff, Metall
Pset_QuantityTakeOff - Reference: Lenestol, hvile
Name (Lenestol, hvile:Lenestol, hvile:...)
3042512
3042530

# IfcFurnishingElement: Lenestol:Lenestol (5)
Type - Material: Metall, Stoff
Pset_QuantityTakeOff - Reference: Lenestol
Name (Lenestol:Lenestol:...) | In
2014712 | B5-422
2664329 | B4-010
2813526 | B5-416
2813575 | B5-416
2813658 | B5-416

# IfcFurnishingElement: Oppkastpose:Oppkastposer (7)
Type - Material: <Unnamed>
Pset_QuantityTakeOff - Reference: Oppkastposer
Name (Oppkastpose:Oppkastposer:...) | In
4595717 | B4-406
4596025 | B4-404
4596035 | B4-403
4627074 | B4-408
4631205 | B4-401
4687411 | PLAN 01
4864347 | B4-407

# IfcFurnishingElement: Puff Spesial_ barn_ MED RYGG:Puff Spesial_ barn RADIUS 1700, Puff Spesial_ barn_ MED RYGG:Puff Spesial_ barn RADIUS 1700:4494520
In: B4-424B
Type - Material: Lys blå puff
Pset_QuantityTakeOff - Reference: Puff Spesial_ barn RADIUS 1700

# IfcFurnishingElement: Seng:Seng 900x2100, Seng:Seng 900x2100:4943269
In: B5-405
Type - Material: <Unnamed>
Pset_QuantityTakeOff - Reference: Seng 900x2100

# IfcFurnishingElement: Servantdispenser:Servantdispenser (45)
Type - Material: <Unnamed>
Pset_QuantityTakeOff - Reference: Servantdispenser
Name (Servantdispenser:Servantdispenser:...) | In
3303248 | B4-422
3321587 | B4-423
3337173 | B4-412
3337174 | B4-412
3337251 | B4-417A
3337252 | B4-417A
3337401 | B4-408
3337478 | B5-409
3337479 | B5-409
3337643 | B4-411
3337718 | B4-417
3337719 | B4-417
3339217 | B4-406
3339218 | B4-406
3339312 | B4-404
3339313 | B4-404
3339348 | B4-403
3339349 | B4-403
3339363 | B4-401
3339364 | B4-401
3339558 | B4-425A
3339559 | B4-425A
3339623 | B4-425B
3339624 | B4-425B
3339913 | B4-407B
3339914 | B4-407B
3340020 | B4-408A
3340021 | B4-408A
3340256 | B5-409A
3340257 | B5-409A
3340461 | B5-420
3340618 | B5-420A
3340716 | B5-420A
3341068 | B5-311A
3341069 | B5-311A
3341192 | B5-311B
3341193 | B5-311B
3341336 | B5-304
4081110 | B4-413
4081111 | B4-413
4755153 | WC:4167080
4755154 | WC:4167080
4755331 | B5-303
4755332 | B5-303
4864051 | B4-408

# IfcFurnishingElement: Servantdispenser:Spritdispenser, Servantdispenser:Spritdispenser:4885486
In: B4-407
Type - Material: <Unnamed>
Pset_QuantityTakeOff - Reference: Spritdispenser

# IfcFurnishingElement: Servantdispenser:Såpedispenser, Servantdispenser:Såpedispenser:3337312
In: B4-407
Type - Material: <Unnamed>
Pset_QuantityTakeOff - Reference: Såpedispenser

# IfcFurnishingElement: Sittebenk med rygg, D600:Sittebenk, L1655, Sittebenk med rygg, D600:Sittebenk, L1655:3205547
In: B4-401A
Type - Material: Ask, Nevotex- kunstlær Cognac, <Unnamed>, Aluminium Lakkert RAL 7021
Pset_QuantityTakeOff - Reference: Sittebenk, L1655

# IfcFurnishingElement: Sittebenk med rygg, D600:Sittebenk, L2185, Sittebenk med rygg, D600:Sittebenk, L2185:3205794
In: B4-010
Type - Material: Ask, Nevotex- kunstlær Cognac, <Unnamed>, Aluminium Lakkert RAL 7021
Pset_QuantityTakeOff - Reference: Sittebenk, L2185

# IfcFurnishingElement: Sittebenk med rygg_til spilevegg, D600:Sittebenk, L1900, Sittebenk med rygg_til spilevegg, D600:Sittebenk, L1900:2850381
In: B4-424B
Type - Material: <Unnamed>, Aluminium Lakkert RAL 7021, Wood, finér, Nevotex- kunstlær Cognac
Pset_QuantityTakeOff - Reference: Sittebenk, L1900

# IfcFurnishingElement: Sittebenk med rygg_til spilevegg, D600:Sittebenk, L4250, Sittebenk med rygg_til spilevegg, D600:Sittebenk, L4250:3128342
In: B4-424B
Type - Material: <Unnamed>, Aluminium Lakkert RAL 7021, Wood, finér, Nevotex- kunstlær Cognac
Pset_QuantityTakeOff - Reference: Sittebenk, L4250

# IfcFurnishingElement: Skap_topp_skrå:Skråtopp 350x200 (9)
Type - Material: Overflate-Hvit
Pset_QuantityTakeOff - Reference: Skråtopp 350x200
Name (Skap_topp_skrå:Skråtopp 350x200:...) | In
3654559 | B4-417A
3661433 | B4-412
3662489 | B4-417
3662621 | B4-407B
3662866 | B4-408
3663080 | B4-406
3663223 | B4-404
3663327 | B4-403
4079864 | B5-409

# IfcFurnishingElement: Skap_topp_skrå:Skråtopp 650x200 (2)
Type - Material: Overflate-Hvit
Pset_QuantityTakeOff - Reference: Skråtopp 650x200
Name (Skap_topp_skrå:Skråtopp 650x200:...) | In
4297167 | B4-408
4319316 | B4-419B

# IfcFurnishingElement: Skjermvegg:Skjermvegg, fast (6)
Type - Material: <Unnamed>
Pset_QuantityTakeOff - Reference: Skjermvegg, fast
Name (Skjermvegg:Skjermvegg, fast:...) | In
2555616 | B4-408
2801697 | B4-407
4878079 | B4-404
4914440 | B4-403
4914467 | B4-406
4920164 | B5-409

# IfcFurnishingElement: Skohylle vegghengt, h=1600_ justerbar lengde:Skohylle vegghengt (2)
Type - Material: <Unnamed>
Pset_QuantityTakeOff - Reference: Skohylle vegghengt
Name (Skohylle vegghengt, h=1600_ justerbar lengde:Skohylle vegghengt:...) | In
3044825 | B5-421
3045043 | B5-420

# IfcFurnishingElement: Skuffeseksjon på hjul:Tower, b430, d800, h1200 (6)
Type - Material: <Unnamed>
Pset_QuantityTakeOff - Reference: Tower, b430, d800, h1200
Name (Skuffeseksjon på hjul:Tower, b430, d800, h1200:...) | In
2582943 | B5-409
2582985 | B5-403
2944031 | B5-408
4554643 | B5-403
4943751 | B5-403
4943756 | B5-403

# IfcFurnishingElement: Sofa 3-seter:Sofa 850x2200 (2)
Type - Material: <Unnamed>
Pset_QuantityTakeOff - Reference: Sofa 850x2200
Name (Sofa 3-seter:Sofa 850x2200:...) | In
2012668 | B5-422
2736817 | B4-425A

# IfcFurnishingElement: Sofa 3-seter:Sofa/dagseng 850x2200, Sofa 3-seter:Sofa/dagseng 850x2200:2987732
In: B5-406
Type - Material: <Unnamed>
Pset_QuantityTakeOff - Reference: Sofa/dagseng 850x2200

# IfcFurnishingElement: Spilevegg_Skrå, vente 1900:Spilevegg 2, Spilevegg_Skrå, vente 1900:Spilevegg 2:4083757
In: B4-424B
Type - Material: Ask
Pset_QuantityTakeOff - Reference: Spilevegg 2

# IfcFurnishingElement: Spilevegg_Skrå, vente 4225:Spilevegg 1, Spilevegg_Skrå, vente 4225:Spilevegg 1:2493454
In: B4-424B
Type - Material: <Unnamed>, Ask
Pset_QuantityTakeOff - Reference: Spilevegg 1

# IfcFurnishingElement: Stablestol:Besøksstol (17)
Type - Material: Metall, Stoff
Pset_QuantityTakeOff - Reference: Besøksstol
Name (Stablestol:Besøksstol:...) | In
1939667 | PLAN U1
1939668 | PLAN U1
2420966 | B5-322
2420967 | B5-322
2420971 | B5-321
2420972 | B5-321
2420976 | PLAN U1
2420977 | PLAN U1
2586961 | B5-406
2710640 | B5-301
2710641 | B5-301
4173377 | Kontor:2708261
4173378 | Kontor:2708261
4452296 | B5-324
4452297 | B5-324
4554242 | B5-412
4943270 | B5-405

# IfcFurnishingElement: Stablestol:Møteromsstol (31)
Type - Material: Metall, Stoff
Pset_QuantityTakeOff - Reference: Møteromsstol
Name (Stablestol:Møteromsstol:...) | In
1770363 | B5-422
1770364 | B5-422
1770365 | B5-422
1770369 | B5-422
1770370 | B5-422
1770371 | B5-422
1934772 | B5-409
1934773 | B5-409
2012591 | B5-422
2012592 | B5-422
2012593 | B5-422
2012594 | B5-422
2012595 | B5-422
2012596 | B5-422
2944024 | B5-408
2944025 | B5-408
4554239 | B5-412
4554240 | B5-412
4554241 | B5-412
4554243 | B5-412
4554244 | B5-412
4554245 | B5-412
4554246 | B5-412
4554247 | B5-412
4554248 | B5-412
4554249 | B5-412
4554250 | B5-412
4554265 | B5-412
4554266 | B5-412
4948431 | B5-403
4948432 | B5-403

# IfcFurnishingElement: Stativ engangskopper:Stativ engangsbeger (7)
Type - Material: <Unnamed>
Pset_QuantityTakeOff - Reference: Stativ engangsbeger
Name (Stativ engangskopper:Stativ engangsbeger:...) | In
4596138 | B4-403
4612176 | B4-404
4612186 | B4-406
4627151 | B4-408
4631255 | B4-401
4687412 | B5-409
4829020 | B4-407

# IfcFurnishingElement: Stativ, hansker:Hanskestativ (11)
Type - Material: <Unnamed>
Pset_QuantityTakeOff - Reference: Hanskestativ
Name (Stativ, hansker:Hanskestativ:...) | In
4584233 | B4-404
4584323 | B4-407
4586142 | B4-406
4586306 | B4-403
4586426 | B4-401
4626739 | B4-408
4631145 | B4-407B
4645033 | B4-425B
4650813 | B4-411
4687269 | B5-409A
4687358 | B5-409

# IfcFurnishingElement: Sterilisator:Sterilisator, Sterilisator:Sterilisator:2641957
In: B4-417A
Type - Material: <Unnamed>
Pset_QuantityTakeOff - Reference: Sterilisator

# IfcFurnishingElement: Stol-enkel:Besøksstol uten armlene (14)
Type - Material: Metall, Stoff
Type - Pset_ManufacturerTypeInformation - Manufacturer: Noor - plast u/polstring meier 660
Pset_QuantityTakeOff - Reference: Besøksstol uten armlene
Name (Stol-enkel:Besøksstol uten armlene:...) | In
2554740 | B4-408
2554741 | B4-407
2770758 | B4-404
2770759 | B4-404
2770783 | B4-406
2770784 | B4-406
4098788 | B4-403
4098789 | B4-403
4098840 | B5-409
4098841 | B5-409
4098889 | B4-425
4098907 | B4-425B
4630857 | B4-401
4630858 | B4-401

# IfcFurnishingElement: Takskinne for Infusjonsoppheng:Takskinne for Infusjonsoppheng (5)
Type - Material: <Unnamed>
Pset_QuantityTakeOff - Reference: Takskinne for Infusjonsoppheng
Name (Takskinne for Infusjonsoppheng:Takskinne for Infusjonsoppheng:...) | In
4626239 | B4-408
4770198 | B4-407
4878067 | B4-401
4878069 | B4-401
4941960 | B5-409

# IfcFurnishingElement: Tavle_whiteboard:Oppslagstavle, 120x120 (2)
Type - Material: <Unnamed>
Pset_QuantityTakeOff - Reference: Oppslagstavle, 120x120
Name (Tavle_whiteboard:Oppslagstavle, 120x120:...) | In
2586441 | B5-421
2809935 | B5-422

# IfcFurnishingElement: Tavle_whiteboard:Synstavle 400x600 (6)
Type - Material: <Unnamed>
Pset_QuantityTakeOff - Reference: Synstavle 400x600
Name (Tavle_whiteboard:Synstavle 400x600:...) | In
2557302 | B4-408
2557630 | B5-409
2806719 | B4-406
2813841 | B4-407
2813846 | B4-403
2813847 | B4-404

# IfcFurnishingElement: Tavle_whiteboard:Whiteboard, b1200xh900, Tavle_whiteboard:Whiteboard, b1200xh900:2807105
In: B4-408
Type - Material: <Unnamed>
Pset_QuantityTakeOff - Reference: Whiteboard, b1200xh900

# IfcFurnishingElement: Tavle_whiteboard:Whiteboard, b600xh1200, Tavle_whiteboard:Whiteboard, b600xh1200:2987758
In: B4-412
Type - Material: <Unnamed>
Pset_QuantityTakeOff - Reference: Whiteboard, b600xh1200

# IfcFurnishingElement: Tavle_whiteboard:Whiteboard, b900xh900, magnet (2)
Type - Material: <Unnamed>
Pset_QuantityTakeOff - Reference: Whiteboard, b900xh900, magnet
Name (Tavle_whiteboard:Whiteboard, b900xh900, magnet:...) | In
2425231 | B4-407
3451733 | B4-425A

# IfcFurnishingElement: V2 - Håndvaskgarnityr type 2, bakplate:Håndvaskgarnityr type 2 (18)
Type - Material: <Unnamed>
Pset_QuantityTakeOff - Reference: Håndvaskgarnityr type 2
Name (V2 - Håndvaskgarnityr type 2, bakplate:Håndvaskgarnityr type 2:...) | In
3337172 | B4-412
3337250 | B4-417A
3337400 | B4-408
3337477 | B5-409
3337717 | B4-417
3339216 | B4-406
3339311 | B4-404
3339347 | B4-403
3339362 | B4-401
3339557 | B4-425A
3339622 | B4-425B
3339912 | B4-407B
3340019 | B4-408A
3340255 | B5-409A
3341067 | B5-311A
3341191 | B5-311B
4755152 | WC:4167080
4755330 | B5-303

# IfcFurnishingElement: V3 - Håndvaskgarnityr type 3, veggarmatur, bakplate:Håndvaskgarnityr type 3, veggarmatur, V3 - Håndvaskgarnityr type 3, veggarmatur, bakplate:Håndvaskgarnityr type 3, veggarmatur:4081109
In: B4-413
Type - Material: <Unnamed>
Pset_QuantityTakeOff - Reference: Håndvaskgarnityr type 3, veggarmatur

# IfcFurnishingElement: Vegg absorbent_Wall-it_kardemomme:Vegg absorbent_Wall-it_kardemomme b900 (2)
In: B4-425A
Type - Material: Kardemomme_wall-it
Type - Pset_FurnitureTypeCommon - Description: Veggabsorbent
Pset_QuantityTakeOff - Reference: Vegg absorbent_Wall-it_kardemomme b900
Name (Vegg absorbent_Wall-it_kardemomme:Vegg absorbent_Wall-it_kardemomme b900:...)
4321299
4321396

# IfcFurnishingElement: Vegg absorbent_Wall-it_kardemomme:Veggabsorbent (6)
Type - Material: Kardemomme_wall-it
Pset_QuantityTakeOff - Reference: Veggabsorbent
Name (Vegg absorbent_Wall-it_kardemomme:Veggabsorbent:...) | In
4002329 | PLAN 02
4002406 | PLAN 02
4002770 | PLAN 02
4003453 | B5-422
4003454 | B5-422
4003455 | B5-422

# IfcFurnishingElement: Veggfast speil:Veggfast speil (400x1600) (2)
Type - Material: <Unnamed>
Pset_QuantityTakeOff - Reference: Veggfast speil (400x1600)
Name (Veggfast speil:Veggfast speil (400x1600):...) | In
3107733 | B5-421
3107985 | B5-420

# IfcFurnishingElement: Ventestoler - 2+4 seter:2+4 seter, Ventestoler - 2+4 seter:2+4 seter:4093452
In: B4-424B
Type - Material: Sort metall, Nevotex_ cognac, sort lakkert
Pset_QuantityTakeOff - Reference: 2+4 seter

# IfcFurnishingElement: Ventestoler - 7 seter:7 seter, Ventestoler - 7 seter:7 seter:4088934
In: B4-424B
Type - Material: Sort metall, Nevotex_ cognac, sort lakkert
Pset_QuantityTakeOff - Reference: 7 seter

# IfcFurnishingElement: Vestre - April Bench - 716:Utebenk (2)
In: Uteplass:2806164
Type - Material: A_Finish_Metal_Steel_Brushed, A_Finish_Wood_Generic_Light
Type - Pset_FurnitureTypeCommon - Description: Bench with back, freestanding, RAL1001 Beige
Type - Pset_ManufacturerTypeInformation - Manufacturer: Vestre
Classification: 716 (Uniformat)
Pset_QuantityTakeOff - Reference: Utebenk
Name (Vestre - April Bench - 716:Utebenk:...)
3104642
3105381

# IfcFurnishingElement: posthylle:Posthylle, posthylle:Posthylle:3825648
In: B5-402
Type - Material: Overflate-Hvit
Pset_QuantityTakeOff - Reference: Posthylle

# IfcFurnishingElement: veggdekor tre med lekevegg_hjørne:Veggdekor tre med lekevegg_hjørne, veggdekor tre med lekevegg_hjørne:Veggdekor tre med lekevegg_hjørne:2083980
In: B4-424B
Type - Material: Ask, Lys blå, <Unnamed>
Pset_QuantityTakeOff - Reference: Veggdekor tre med lekevegg_hjørne

# IfcOpeningElement: Opening (265)
Name | In
Floor:250 Generisk dekke 300 mm:1418866 | PLAN 01 | Pset_OpeningElementCommon - Reference: Gulvsluk (200x200); sets with these values: 2
Floor:250 Generisk dekke 300 mm:1418866 | PLAN 01 | Pset_OpeningElementCommon - Reference: Lokasse; sets with these values: 2
Floor:250 Generisk dekke 300 mm:1418866 | PLAN 01 | Pset_OpeningElementCommon - Reference: Gulvbrønn; sets with these values: 2
Basic Wall:230 Betong yttervegg 360 mm:1561653 | PLAN 01 | Pset_OpeningElementCommon - Reference: 2441 Innvendig 18x21M; sets with these values: 2
Basic Wall:230 Betong yttervegg 200 mm:1561823 | PLAN 01 | Pset_OpeningElementCommon - Reference: 2441 Innvendig 18x21M; sets with these values: 2
Basic Wall:230 Generisk yttervegg 360 mm:1567579 | PLAN 01 | Pset_OpeningElementCommon - Reference: 2441 Innvendig 18x21M; sets with these values: 2
Basic Wall:240 Eksist. Innervegg 150 mm:1664150 | PLAN U1 | Pset_OpeningElementCommon - Reference: 244 Innvendig, FOLDE 5400x2100; sets with these values: 2
Basic Wall:240 Eksist. innervegg 200 mm:1671288 | PLAN U1 | Pset_OpeningElementCommon - Reference: 244 Innvendig AAa 11x21M - Tett; sets with these values: 2
Basic Wall:242 IV01 Innervegg 150 mm:1694109 | PLAN 01 | Pset_OpeningElementCommon - Reference: 244 Innvendig, SL (5+17)x13M - Hjørne 2 sider; sets with these values: 2
Basic Wall:232 Sokkel Garasje 300 mm:3431259 | PLAN 01 | Pset_OpeningElementCommon - Reference: 232 Sokkel Garasje 300 mm; sets with these values: 2
Basic Wall:242 IV01 Innervegg 150 mm:1749680 | PLAN 01 | Pset_OpeningElementCommon - Reference: 244 Innvendig ABa 16x21M - Tett; sets with these values: 2
Basic Wall:242 IV01 Innervegg 150 mm:1750825 | PLAN 01 | Pset_OpeningElementCommon - Reference: 244 Innvendig ABa 16x21M - Tett; sets with these values: 2
Basic Wall:242 IV01 Innervegg 150 mm:1909955 | PLAN 01 | Pset_OpeningElementCommon - Reference: 244 Innvendig ABa 11x21M - Tett; sets with these values: 2
Basic Wall:240 Eksist. Innervegg 120 mm:2015444 | PLAN 02 | Pset_OpeningElementCommon - Reference: 244 Innvendig GJb 20x21M (10x21M) - Glass - Heltre Ask; sets with these values: 2
Basic Wall:240 Eksist. Innervegg 150 mm:2254909 | PLAN U1 | Pset_OpeningElementCommon - Reference: 2441 Innvendig 10x21M; sets with these values: 2
Basic Wall:240 Eksist. Innervegg 120 mm:2277897 | PLAN 02 | Pset_OpeningElementCommon - Reference: 244 Innvendig GJb 20x21M (10x21M) - Glass - Heltre Ask; sets with these values: 2
Basic Wall:240 Eksist. Innervegg 120 mm:2277899 | PLAN 02 | Pset_OpeningElementCommon - Reference: 244 Innvendig GJb 20x21M (10x21M) - Glass - Heltre Ask; sets with these values: 2
Basic Wall:230 Generisk yttervegg 200 mm, Gjentetting 2:2428639 | PLAN 01 | Pset_OpeningElementCommon - Reference: 234 Utvendig YBc 18x21M - Firkantede vinduer; sets with these values: 2
Basic Wall:VEGGPANEL TRE:2646438 | PLAN 01 | Pset_OpeningElementCommon - Reference: 244 Innvendig, SL (5+17)x13M - Hjørne 2 sider; sets with these values: 2
2 x Basic Wall:VEGGPANEL TRE:3598177 | PLAN 01 | Pset_OpeningElementCommon - Reference: VEGGPANEL TRE; sets with these values: 2
Basic Wall:242 IV01 Innervegg 150 mm:2669828 | PLAN 01 | Pset_OpeningElementCommon - Reference: 244 Innvendig, SL (5+17)x13M - Hjørne 2 sider; sets with these values: 2
Basic Wall:242 IV01 Innervegg 150 mm:2713492 | PLAN 02 | Pset_OpeningElementCommon - Reference: 244 Innvendig AAa 9x21M - Tett Tre; sets with these values: 2
Basic Wall:240 Eksist. Innervegg 150 mm:2716671:1 | PLAN U1 | Pset_OpeningElementCommon - Reference: 240 Eksist. Innervegg 150 mm; sets with these values: 2
Basic Wall:230 Generisk yttervegg 200 mm Med fasadeplater:3288988 | PLAN 01 | Pset_OpeningElementCommon - Reference: 230 Generisk yttervegg 200 mm Med fasadeplater; sets with these values: 2
Basic Wall:230 Eksist. yttervegg 200 mm:1559387 | PLAN 02 | Pset_OpeningElementCommon - Reference: 230 Eksist. yttervegg 200 mm; sets with these values: 2
Basic Wall:232 Yttervegg Garasje 300 mm:3667618 | PLAN 01 | Pset_OpeningElementCommon - Reference: 232 Yttervegg Garasje 300 mm; sets with these values: 2
Basic Wall:232 Yttervegg Garasje 300 mm:3431542 | PLAN 01 | Pset_OpeningElementCommon - Reference: 234 Utvendig, Port 6100x3500; sets with these values: 2
Basic Wall:230 Eksist. Yttervegg 260 mm:3621114:1 | PLAN 01 | Pset_OpeningElementCommon - Reference: 230 Eksist. Yttervegg 260 mm; sets with these values: 2
Basic Wall:230 Generisk yttervegg 300 mm, Ny:3684368 | PLAN 01 | Pset_OpeningElementCommon - Reference: 10x16M Tre; sets with these values: 2
Basic Wall:VEGG Garasje:3945863 | PLAN 01 | Pset_OpeningElementCommon - Reference: 234 Utvendig YBc 18x21M - Firkantede vinduer; sets with these values: 2
Basic Wall:242 Baderomsplater grønn:4006138 | PLAN 02 | Pset_OpeningElementCommon - Reference: 244 Innvendig BAa 8x21M - Tett; sets with these values: 2
Basic Wall:242 Baderomsplater grønn:4007394 | PLAN 02 | Pset_OpeningElementCommon - Reference: 244 Innvendig BAa 10x21M - Tett Tre; sets with these values: 2
Basic Wall:242 Baderomsplater grønn:4007853 | PLAN 02 | Pset_OpeningElementCommon - Reference: 244 Innvendig BAa 8x21M - Tett; sets with these values: 2
5 x Floor:250 Generisk dekke 300 mm grønn vinyl:4073349 | PLAN 02 | Pset_OpeningElementCommon - Reference: Gulvsluk (200x200); sets with these values: 2
Floor:250 Generisk dekke 300 mm grønn vinyl:4024866 | PLAN 02 | Pset_OpeningElementCommon - Reference: 250 Generisk dekke 300 mm grønn vinyl; sets with these values: 2
Basic Wall:242 IV01 Innervegg 150 mm:4263263 | PLAN 01 | Pset_OpeningElementCommon - Reference: 244 Innvendig AFb 10x21M - Glass-tre; sets with these values: 2
Basic Wall:242 Baderomsplater beige:4909293 | PLAN 01 | Pset_OpeningElementCommon - Reference: 244 Innvendig BAa 10x21M - Tett Grå; sets with these values: 2
Basic Wall:242 Baderomsplater beige:4909493 | PLAN 01 | Pset_OpeningElementCommon - Reference: 244 Innvendig BAa 10x21M - Tett; sets with these values: 2
5 x Basic Wall:230 Eksist. yttervegg 200 mm:1559632 | PLAN 01
234-Åpningsbart - Hor:10x16M:3637888:1 | PLAN 01
234-Åpningsbart - Hor:10x16M:3638022:1 | PLAN 01
234-Åpningsbart - Hor:10x16M:3638120:1 | PLAN 01
234-Åpningsbart - Hor:10x16M:3638121:1 | PLAN 01
234-Åpningsbart - Hor:10x16M:3638387:1 | PLAN 01
2 x Basic Wall:230 Betong yttervegg 200 mm:1561823 | PLAN 01
Likefløyet:234 Utvendig YBc 18x21M - Firkantede vinduer:1756957:1 | PLAN 01
Basic Wall:240 Eksist. Innervegg 150 mm:1563100 | PLAN 01
Enfløyet:244 Innvendig AAa 11x21M - Tett:4478673:1 | PLAN 01
Basic Wall:240 Eksist. Innervegg 120 mm:1565001 | PLAN 02
Basic Wall:240 Eksist. Innervegg 150 mm:1565698 | PLAN 02
Enfløyet:244 Innvendig CAb 11x21M - Glass - Heltre Ask:2278295:1 | PLAN 02
Basic Wall:240 Eksist. Innervegg 120 mm:1565828 | PLAN 02
Glassfelt-m_dør:244 Innvendig GJb 16x21M (10x21M) - Glass - Heltre Ask:2774136:1 | PLAN 02
Enfløyet:244 Innvendig BAa 10x21M - Tett:2016581:1 | PLAN 01
Enfløyet:2441 Innvendig 10x21M:1574782:1 | PLAN 01
Enfløyet:2441 Innvendig 8x21M:1574822:1 | PLAN 01
Basic Wall:240 Eksist. Innervegg 120 mm:1569532 | PLAN 02
8 x Basic Wall:230 Eksist. yttervegg 200 mm:1660288 | PLAN 02
234-Åpningsbart:10x12M:3659510:1 | PLAN 02
234-Åpningsbart:10x12M:3659552:1 | PLAN 02
234-Åpningsbart:10x12M:3659531:1 | PLAN 02
234-Åpningsbart:10x12M:3659636:1 | PLAN 02
234-Åpningsbart:10x12M:3659615:1 | PLAN 02
234-Åpningsbart:10x12M:3659594:1 | PLAN 02
234-Åpningsbart:10x12M:3659323:1 | PLAN 02
234-Åpningsbart:10x12M:3659573:1 | PLAN 02
Enfløyet:2441 Innvendig 10x21M:1667445:1 | PLAN U1
234-Åpningsbart:10x12M Eks.:1661948:1 | PLAN U1
234-Åpningsbart:10x12M Eks.:1661949:1 | PLAN U1
234-Åpningsbart:10x12M Eks.:1661950:1 | PLAN U1
234-Åpningsbart:10x12M Eks.:1661951:1 | PLAN U1
234-Åpningsbart:10x12M Eks.:1661952:1 | PLAN U1
234-Åpningsbart:10x12M Eks.:1661953:1 | PLAN U1
234-Åpningsbart:10x12M Eks.:1661954:1 | PLAN U1
234-Åpningsbart:10x12M Eks.:1661955:1 | PLAN U1
234-Åpningsbart:10x12M Eks.:1661956:1 | PLAN U1
234-Åpningsbart:10x12M Eks.:1661957:1 | PLAN U1
234-Åpningsbart:10x12M Eks.:1661958:1 | PLAN U1
234-Åpningsbart:10x12M Eks.:1661959:1 | PLAN U1
Basic Wall:230 Eksist. yttervegg 200 mm:1661965 | PLAN U1
234-Åpningsbart:10x12M Eks.:1661961:1 | PLAN U1
2 x Basic Wall:230 Eksist. yttervegg 200 mm:1663154 | PLAN U1
234-Åpningsbart:10x12M Eks.:1661962:1 | PLAN U1
Likefløyet:234 Utvendig 18x21M - Glass:1666379:1 | PLAN U1
Enfløyet:2441 Innvendig 10x21M:1666559:1 | PLAN U1
Enfløyet:2441 Innvendig 10x21M:1666729:1 | PLAN U1
Enfløyet:2441 Innvendig 10x21M:1667076:1 | PLAN U1
Enfløyet:2441 Innvendig 10x21M:1667317:1 | PLAN U1
Enfløyet:2441 Innvendig 10x21M:1667380:1 | PLAN U1
Enfløyet:2441 Innvendig 10x21M:1667631:1 | PLAN U1
Enfløyet:2441 Innvendig 10x21M:4348157:1 | PLAN U1
FOLDEVEGG:244 Innvendig, FOLDE 5400x2100:4348271:1 | PLAN U1
Likefløyet:2441 Innvendig 18x21M - Glass:1666482:1 | PLAN U1
Enfløyet:2441 Innvendig 10x21M:1668074:1 | PLAN U1
Enfløyet:2441 Innvendig 10x21M:1667718:1 | PLAN U1
Enfløyet:2441 Innvendig 10x21M:1666929:1 | PLAN U1
Basic Wall:240 Eksist. Innervegg 150 mm:1665728 | PLAN U1
Enfløyet:244 Innvendig AAa 8x21M - Tett:4166287:1 | PLAN U1
Enfløyet:2441 Innvendig 10x21M:1667819:1 | PLAN U1
Basic Wall:240 Eksist. Innervegg 150 mm:2110444 | PLAN U1
Enfløyet:2441 Innvendig 10x21M:1667908:1 | PLAN U1
Basic Wall:240 Eksist. Innervegg 150 mm:4401130 | PLAN U1
Enfløyet:2441 Innvendig 10x21M:1668133:1 | PLAN U1
Basic Wall:240 Eksist. Innervegg 150 mm:1937690 | PLAN U1
Enfløyet:2441 Innvendig 8x21M:2708834:1 | PLAN U1
Enfløyet:2441 Innvendig 8x21M:1669708:1 | PLAN U1
Basic Wall:240 Eksist. Innervegg 150 mm:1669362 | PLAN U1
Enfløyet:244 Innvendig AAa 10x21M - Tett Grå:1779586:1 | PLAN 01
Skyvedør (Innfelt):244 Innvendig AFb 10x21M - Glass-tre:1833604:1 | PLAN 01
Basic Wall:240 Eksist. Innervegg 120 mm:1680985 | PLAN 02
Glassfelt-m_dør:244 Innvendig GJb 20x21M (10x21M) - Glass - Heltre Ask:4554475:1 | PLAN 02
Enfløyet:244 Innvendig AAc 10x21M - Firkantet vindu:1899735:1 | PLAN 01
Enfløyet:244 Innvendig AAc 10x21M - Firkantet vindu:1920354:1 | PLAN 01
Likefløyet:244 Innvendig ABa 11x21M - Tett:2093468:1 | PLAN 01
Skyvedør (Utenpå):244 Innvendig, ADa 9x21M:1695923:1 | PLAN 01
Enfløyet:244 Innvendig AAb 10x21M - Frostet Glass - trelaminat:1695085:1 | PLAN 01
Enfløyet:244 Innvendig AAb 10x21M - Frostet Glass - trelaminat:1695227:1 | PLAN 01
Enfløyet:244 Innvendig AAb 10x21M - Glass - Trelaminat:2737193:1 | PLAN 01
Skyvedør (Utenpå):244 Innvendig, ADa 10x21M:1695699:1 | PLAN 01
Ulikefløyet:244 Innvendig ACa 13x21M - Tett Grå:1699249:1 | PLAN 01
Enfløyet:244 Innvendig AAa 10x21M - Tett:1707733:1 | PLAN 02
Enfløyet:244 Innvendig AAa 11x21M - Tett:1705576:1 | PLAN U1
Basic Wall:240 Innervegg betong 150 mm:2265175 | PLAN U1
Enfløyet:244 Innvendig AAa 11x21M - Tett:1705617:1 | PLAN 01
Garasjeport:234 Utvendig, Port 6100x3500:1773965:1 | PLAN 01
Enfløyet:244 Innvendig AAa 8x21M - Tett - Trelaminat:1712446:1 | PLAN 01
Enfløyet:244 Innvendig AAb 11x21M - Glass:1716198:1 | PLAN 01
Enfløyet:244 Innvendig AAa 11x21M - Tett - Trelaminat:1744954:1 | PLAN 01
Basic Wall:242 IV01 Innervegg 150 mm:3486303 | PLAN 01
Enfløyet:244 Innvendig AAa 11x21M - Tett Grå:1753103:1 | PLAN 01
Basic Wall:242 IV01 Innervegg 150 mm:1817889 | PLAN 01
Enfløyet:244 Innvendig AAa 11x21M - Tett Grå:1753159:1 | PLAN 01
2 x Basic Wall:242 IV01 Innervegg 150 mm:4263197 | PLAN 01
Enfløyet:244 Innvendig AAa 11x21M - Tett Grå:1753666:1 | PLAN 01
Enfløyet:244 Innvendig AAc 10x21M - Firkantet vindu:1817336:1 | PLAN 01
Heis:Heis 2 Sengeheis:1757178:1 | PLAN 01
Enfløyet:244 Innvendig AAb 10x21M - Glass - Trelaminat:1790154:1 | PLAN 01
Enfløyet:244 Innvendig AAa 12x21M - Tett Grå:1917865:1 | PLAN 01
Enfløyet:244 Innvendig AAa 10x21M - Tett:1869859:1 | PLAN 01
Likefløyet:234 Utvendig YBc 18x21M - Firkantede vinduer:1879763:1 | PLAN 01
Skyvedør (Utenpå):244 Innvendig, ADa 9x21M:1920051:1 | PLAN 01
Enfløyet:244 Innvendig AAa 10x21M - Tett - Trelaminat:1892404:1 | PLAN 01
Luke-Lab:244 Luke, Lab, 4x4M:1920811:1 | PLAN 01
Skyvedør (Utenpå):244 Innvendig, ADa 10x21M:1900430:1 | PLAN 01
Skyvedør (Innfelt):244 Innvendig AFb 10x21M - Glass-tre:1917043:1 | PLAN 01
Enfløyet:244 Innvendig AAa 10x21M - Tett:1910230:1 | PLAN 01
Enfløyet:244 Innvendig AAa 10x21M - Tett:1915015:1 | PLAN 02
Enfløyet:2441 Innvendig 10x21M:1948191:1 | PLAN U1
Enfløyet:244 Innvendig AAb 10x21M - Glass - Trelaminat:2267271:1 | PLAN 01
Skyveluke:244 Innvendig Skyveluke, SL 12x13M:2043682:1 | PLAN 01
Likefløyet:244 Innvendig ABa 16x21M - Tett:2091980:1 | PLAN 01
Likefløyet:244 Innvendig ABa 16x21M - Tett:2092200:1 | PLAN 01
Enfløyet:244 Innvendig AAa 10x21M - Tett:2093668:1 | PLAN 02
Basic Wall:242 IV01 Innervegg 150 mm:2713878 | PLAN 02
Enfløyet:244 Innvendig AAa 11x21M - Tett - Trelaminat:2100672:1 | PLAN 01
Basic Wall:242 IV01 Innervegg 150 mm:3486516 | PLAN 01
Enfløyet:244 Innvendig AAa 10x21M - Tett:2252644:1 | PLAN U1
Likefløyet:2441 Innvendig ABc 16x21M - Firkantete vinduer - Grå:2255655:1 | PLAN 01
Enfløyet:244 Innvendig AAa 13x21M - Tett:2256147:1 | PLAN 01
Enfløyet:244 Innvendig AAa 10x21M - Tett:2257676:1 | PLAN 01
Enfløyet:244 Innvendig AAa 11x21M - Tett:2813751:1 | PLAN U1
Glassfelt-m_dør:244 Innvendig GJb 20x21M (10x21M) - Glass - Heltre Ask:2278041:1 | PLAN 02
8 x Basic Wall:240 Eksist. Innervegg 120 mm:4530160 | PLAN 02
Glassfelt-m_dør:244 Innvendig GJb 20x21M (10x21M) - Glass - Heltre Ask:2278128:1 | PLAN 02
234-Fast:4,5x21M:3363459:1 | PLAN 02
Likefløyet:244 Innvendig ABa 14x21M - Tett:2288382:1 | PLAN 01
Likefløyet:2441 Innvendig ABc 16x21M - Firkantete vinduer - Grå:2353663:1 | PLAN 01
Basic Wall:242 IV01 Innervegg 150 mm:4263093 | PLAN 01
Enfløyet:2441 Innvendig 10x21M:2427704:1 | PLAN U1
Enfløyet:244 Innvendig AAa 10x21M - Tett:2519549:1 | PLAN 01
Enfløyet:244 Innvendig AAa 11x21M - Tett:2521165:1 | PLAN 01
Enfløyet:244 Innvendig AAa 11x21M - Tett Grå:2519552:1 | PLAN 01
Skyvedør (Utenpå):244 Innvendig, ADa 9x21M:2522133:1 | PLAN 01
Enfløyet:244 Innvendig BAa 10x21M - Tett Grå:2520851:1 | PLAN 01
Basic Wall:240 Eksist. Innervegg 150 mm:2520849 | PLAN 01
Enfløyet:244 Innvendig AAa 10x21M - Tett Grå:2526005:1 | PLAN 01
Basic Wall:242 IV01 Innervegg 150 mm:4263026 | PLAN 01
Basic Wall:242 IV01 Innervegg 150 mm:2669805 | PLAN 01
Enfløyet:244 Innvendig AAa 8x21M - Tett:4166522:1 | PLAN U1
Enfløyet:244 Innvendig AAa 10x21M - Tett:2708142:1 | PLAN U1
Enfløyet:244 Innvendig AAa 11x21M - Tett:4167103:1 | PLAN U1
Enfløyet:244 Innvendig AAa 10x21M - Tett:2712880:1 | PLAN 02
Enfløyet:244 Innvendig AAa 10x21M - Tett:2713496:1 | PLAN 02
Enfløyet:244 Innvendig BAa 10x21M - Tett Tre:2713491:1 | PLAN 02
Enfløyet:244 Innvendig BAa 8x21M - Tett:2713508:1 | PLAN 02
Enfløyet:244 Innvendig AAa 8x21M - Tett:2713509:1 | PLAN 02
Enfløyet:2441 Innvendig 9x21M:2716240:1 | PLAN U1
Basic Wall:240 Eksist. Innervegg 150 mm:4268944 | PLAN U1
Enfløyet:244 Innvendig AAa 9x21M - Tett Tre:2721720:1 | PLAN 02
2 x Basic Wall:242 IV01 Innervegg 150 mm:2722191 | PLAN 02
Enfløyet:244 Innvendig AAa 9x21M - Tett Tre:2721818:1 | PLAN 02
Enfløyet:244 Innvendig AAa 8x21M - Tett:2722994:1 | PLAN 02
Enfløyet:244 Innvendig BAa 8x21M - Tett:2722993:1 | PLAN 02
Glassfelt-m_dør:244 Innvendig GJb 20x21M (10x21M) - Glass - Heltre Ask:2774098:1 | PLAN 02
Glassfelt-m_dør:244 Innvendig GJb 20x21M (10x21M) - Glass - Heltre Ask:2774102:1 | PLAN 02
Enfløyet:244 Innvendig AAb 10x21M - Glass - Trelaminat:2791614:1 | PLAN 01
Inv-Glassfelt:244 Innvendig GH 20x12M:2854204:1 | PLAN 01
2 x Basic Wall:230 Generisk yttervegg 200 mm Med fasadeplater:3291978 | PLAN 01
234-Åpningsbart - Hor:10x16M:3638500:1 | PLAN 01
234-Åpningsbart - Hor:10x16M:3638519:1 | PLAN 01
234-Åpningsbart - Hor:10x16M Tre:3293653:1 | PLAN 01
234-Åpningsbart - Hor:10x16M Tre:3293654:1 | PLAN 01
234-Åpningsbart - Hor:10x16M Tre:3687906:1 | PLAN 01
234-Åpningsbart - Hor:10x16M Tre:3687907:1 | PLAN 01
Ulikefløyet-m_overfelt:244 Innvendig LCb14x25M - Glass:3293013:1 | PLAN 01
Basic Wall:242 IV01 Innervegg 150 mm:3795245 | PLAN 01
234-Fast:4,5x21M:3362830:1 | PLAN 02
Basic Wall:230 Eksist. yttervegg 200 mm:3364316 | PLAN 02
Enfløyet:234 Utvendig WAa 13x21M - Tett:3634529:1 | PLAN 01
234-Åpningsbart:10x12M:3659734:1 | PLAN 02
234-Åpningsbart:10x12M:3660056:1 | PLAN 02
234-Åpningsbart:10x12M:3660089:1 | PLAN 02
234-Åpningsbart:10x12M:3660118:1 | PLAN 02
234-Åpningsbart:10x12M:3660149:1 | PLAN 02
234-Åpningsbart:10x12M:3660180:1 | PLAN 02
234-Åpningsbart:10x12M:3660211:1 | PLAN 02
234-Åpningsbart:10x12M:3660242:1 | PLAN 02
Likefløyet:2441 Innvendig ABc 18x21M - Firkantete vinduer:3670602:1 | PLAN 01
234-Åpningsbart:10x12M:3673071:1 | PLAN 01
234-Åpningsbart:10x12M:3673072:1 | PLAN 01
234-Åpningsbart - Hor:10x16M Tre:3684370:1 | PLAN 01
234-Åpningsbart - Hor:10x16M Tre:3684375:1 | PLAN 01
Enfløyet:244 Innvendig AAa 10x21M - Tett - Trelaminat:3809020:1 | PLAN 02
Basic Wall:240 Eksist. Innervegg 150 mm:4083603 | PLAN 01
Enfløyet:244 Innvendig AAa 8x21M - Tett:4166401:1 | PLAN U1
Enfløyet:244 Innvendig AAa 11x21M - Tett:4167611:1 | PLAN U1
Ulikefløyet-m_overfelt:234 Utvendig ZCb 14x25M - Glass:4285019:1 | PLAN 01
Enfløyet:244 Innvendig AAa 10x21M - Tett:4347422:1 | PLAN U1
Enfløyet:244 Innvendig AAa 11x21M - Tett:4347792:1 | PLAN U1
234-Åpningsbart:10x12M Eks.:4452277:1 | PLAN U1
Basic Wall:230 Eksist. yttervegg 200 mm:4452278 | PLAN U1
Enfløyet:2441 Innvendig 10x21M:4452298:1 | PLAN U1
Basic Wall:240 Eksist. Innervegg 150 mm:4452299 | PLAN U1
Enfløyet:244 Innvendig AAa 11x21M - Tett:4477625:1 | PLAN 01
Enfløyet:244 Innvendig CAb 10x21M - Glass - Heltre Ask:4530625:1 | PLAN 02
Basic Wall:242 Innervegg 120 mm:4943380 | PLAN 02
Ulikefløyet:244 Innvendig ACa 13x21M - Tett Grå:4929241:1 | PLAN 01

# IfcRailing: Railing:280 Håndløper - Rund 40mm - H=800mm (5)
Material: <Unnamed>, Ask
Pset_QuantityTakeOff - Reference: 280 Håndløper - Rund 40mm - H=800mm
Pset_RailingCommon - IsExternal: no; Reference: 280 Håndløper - Rund 40mm - H=800mm; Height: 1219.2 mm
Name (Railing:280 Håndløper - Rund 40mm - H=800mm:...) | In
1934382 | PLAN 01
1934386 | PLAN 01
4305156 | PLAN U1
4305195 | PLAN U1
4769919 | PLAN 02

# IfcRailing: Railing:280 Rekkverk - Loddrett - Runde profiler - H=900mm (2)
In: PLAN U1
Material: <Unnamed>
Pset_QuantityTakeOff - Reference: 280 Rekkverk - Loddrett - Runde profiler - H=900mm
Pset_RailingCommon - IsExternal: no; Reference: 280 Rekkverk - Loddrett - Runde profiler - H=900mm; Height: 1219.2 mm
Name (Railing:280 Rekkverk - Loddrett - Runde profiler - H=900mm:...)
4304348
4306354

# IfcRailing: Railing:280 Rekkverk - Vannrett - Runde profiler - H=1000mm, Railing:280 Rekkverk - Vannrett - Runde profiler - H=1000mm:3633631
In: PLAN 03 (EKS. TAK)
Material: <Unnamed>
Pset_QuantityTakeOff - Reference: 280 Rekkverk - Vannrett - Runde profiler - H=1000mm
Pset_RailingCommon - IsExternal: no; Reference: 280 Rekkverk - Vannrett - Runde profiler - H=1000mm; Height: 1219.2 mm

# IfcRoof: Basic Roof:260 Eksisterende yttertak, Basic Roof:260 Eksisterende yttertak:1419235
In: PLAN 03 (EKS. TAK)
Material: A_Material_Concrete_Insitu_Beam_Semi-Rough_Grey 900 mm
Pset_QuantityTakeOff - Reference: 260 Eksisterende yttertak
Pset_RoofCommon - Reference: 260 Eksisterende yttertak; IsExternal: yes; ProjectedArea: 1397.34 m2; TotalArea: 1397.82 m2

# IfcRoof: Basic Roof:260 Generisk yttertak 200 mm (4)
Material: Eksist. tak 200 mm
Pset_QuantityTakeOff - Reference: 260 Generisk yttertak 200 mm
Pset_RoofCommon - IsExternal: yes; Reference: 260 Generisk yttertak 200 mm
Name (Basic Roof:260 Generisk yttertak 200 mm:...) | In | ProjectedArea (m2) | TotalArea (m2)
2285983 | PLAN 03 (EKS. TAK) | 14.5092 | 16.7538
2286469 | PLAN 03 (EKS. TAK) | 24.6871 | 28.5062
3614461 | PLAN 03 (EKS. TAK) | 57.2005 | 66.0495
3627429 | TEKNISK SKILLE | 0.664 | 0.664228

# IfcRoof: Basic Roof:260 Generisk yttertak 300 mm, Basic Roof:260 Generisk yttertak 300 mm:3620649
In: PLAN 03 (EKS. TAK)
Material: Eksist. tak 300 mm
Pset_QuantityTakeOff - Reference: 260 Generisk yttertak 300 mm
Pset_RoofCommon - IsExternal: yes; Reference: 260 Generisk yttertak 300 mm; ProjectedArea: 9.2296 m2; TotalArea: 9.23276 m2

# IfcRoof: Basic Roof:260 Generisk yttertak 400 mm, Basic Roof:260 Generisk yttertak 400 mm:2285324
In: PLAN 03 (EKS. TAK)
Material: <Unnamed> 400 mm
Pset_QuantityTakeOff - Reference: 260 Generisk yttertak 400 mm
Pset_RoofCommon - IsExternal: yes; Reference: 260 Generisk yttertak 400 mm; ProjectedArea: 65.781 m2; TotalArea: 65.781 m2

# IfcRoof: Basic Roof:260 Generisk yttertak 700 mm, Basic Roof:260 Generisk yttertak 700 mm:2284721
In: PLAN 03 (EKS. TAK)
Material: <Unnamed> 700 mm
Pset_QuantityTakeOff - Reference: 260 Generisk yttertak 700 mm
Pset_RoofCommon - IsExternal: yes; Reference: 260 Generisk yttertak 700 mm; ProjectedArea: 56.52 m2; TotalArea: 56.52 m2

# IfcRoof: Basic Roof:260 Gitter 10mm (3)
In: PLAN 03 (EKS. TAK)
Material: Gitter 10 mm
Pset_QuantityTakeOff - Reference: 260 Gitter 10mm
Pset_RoofCommon - IsExternal: yes; Reference: 260 Gitter 10mm
Name (Basic Roof:260 Gitter 10mm:...) | ProjectedArea (m2) | TotalArea (m2)
3473935 | 74.7 | 79.4941
3478574 | 19.3123 | 20.4804
3479717 | 51.3121 | 54.4193

# IfcSlab: Basic Roof:260 Eksisterende yttertak, Basic Roof:260 Eksisterende yttertak:1419235
In: PLAN 03 (EKS. TAK)
PredefinedType: ROOF; Material: A_Material_Concrete_Insitu_Beam_Semi-Rough_Grey 900 mm
Pset_QuantityTakeOff - Reference: 260 Eksisterende yttertak; sets with these values: 2
Pset_SlabCommon - Reference: 260 Eksisterende yttertak; IsExternal: yes; PitchAngle: 1.5 deg

# IfcSlab: Basic Roof:260 Generisk yttertak 200 mm (7)
PredefinedType: ROOF; Material: Eksist. tak 200 mm
Pset_QuantityTakeOff - Reference: 260 Generisk yttertak 200 mm; sets with these values: 2
Pset_SlabCommon - IsExternal: yes; Reference: 260 Generisk yttertak 200 mm
Name (Basic Roof:260 Generisk yttertak 200 mm:...) | In | PitchAngle (deg)
2 x 2285983 | PLAN 03 (EKS. TAK) | 30
2 x 2286469 | PLAN 03 (EKS. TAK) | 30
2 x 3614461 | PLAN 03 (EKS. TAK) | 30
3627429 | TEKNISK SKILLE | 1.5

# IfcSlab: Basic Roof:260 Generisk yttertak 300 mm, Basic Roof:260 Generisk yttertak 300 mm:3620649
In: PLAN 03 (EKS. TAK)
PredefinedType: ROOF; Material: Eksist. tak 300 mm
Pset_QuantityTakeOff - Reference: 260 Generisk yttertak 300 mm; sets with these values: 2
Pset_SlabCommon - IsExternal: yes; PitchAngle: 1.5 deg; Reference: 260 Generisk yttertak 300 mm

# IfcSlab: Basic Roof:260 Generisk yttertak 400 mm, Basic Roof:260 Generisk yttertak 400 mm:2285324
In: PLAN 03 (EKS. TAK)
PredefinedType: ROOF; Material: <Unnamed> 400 mm
Pset_QuantityTakeOff - Reference: 260 Generisk yttertak 400 mm; sets with these values: 2
Pset_SlabCommon - PitchAngle: 0 deg; IsExternal: yes; Reference: 260 Generisk yttertak 400 mm

# IfcSlab: Basic Roof:260 Generisk yttertak 700 mm, Basic Roof:260 Generisk yttertak 700 mm:2284721
In: PLAN 03 (EKS. TAK)
PredefinedType: ROOF; Material: <Unnamed> 700 mm
Pset_QuantityTakeOff - Reference: 260 Generisk yttertak 700 mm; sets with these values: 2
Pset_SlabCommon - PitchAngle: 0 deg; IsExternal: yes; Reference: 260 Generisk yttertak 700 mm

# IfcSlab: Basic Roof:260 Gitter 10mm, Basic Roof:260 Gitter 10mm:3473935
In: PLAN 03 (EKS. TAK)
PredefinedType: ROOF; Material: Gitter 10 mm
Pset_QuantityTakeOff - Reference: 260 Gitter 10mm; sets with these values: 2
Pset_SlabCommon - IsExternal: yes; Reference: 260 Gitter 10mm; PitchAngle: 20 deg

# IfcSlab: Floor:250 Generisk dekke 200 mm, Floor:250 Generisk dekke 200 mm:3364953
In: PLAN 03 (EKS. TAK)
Type - PredefinedType: FLOOR; Material: VINYL LYS 200 mm
Pset_QuantityTakeOff - Reference: 250 Generisk dekke 200 mm; sets with these values: 2
Pset_SlabCommon - IsExternal: no; LoadBearing: no; PitchAngle: 0 deg; Reference: 250 Generisk dekke 200 mm

# IfcSlab: Floor:250 Generisk dekke 300 mm (4)
Type - PredefinedType: FLOOR; Material: VINYL EMINENT UNISENSE 928 5 mm, Generell Gulv 295 mm
Pset_QuantityTakeOff - Reference: 250 Generisk dekke 300 mm; sets with these values: 2
Pset_SlabCommon - Reference: 250 Generisk dekke 300 mm; IsExternal: no; LoadBearing: no; PitchAngle: 0 deg
Name (Floor:250 Generisk dekke 300 mm:...) | In
1418866 | PLAN 01
1662810 | PLAN U1
2265594 | PLAN 01
4098144 | PLAN U1

# IfcSlab: Floor:250 Generisk dekke 300 mm grønn vinyl, Floor:250 Generisk dekke 300 mm grønn vinyl:4073349
In: PLAN 02
Type - PredefinedType: FLOOR; Material: VINYL EMINENT UNISENSE dusty green 300 mm
Pset_QuantityTakeOff - Reference: 250 Generisk dekke 300 mm grønn vinyl; sets with these values: 2
Pset_SlabCommon - IsExternal: no; LoadBearing: no; PitchAngle: 0 deg; Reference: 250 Generisk dekke 300 mm grønn vinyl

# IfcSlab: Floor:250 Ny Generisk dekke 300 mm (3)
In: PLAN 01
Type - PredefinedType: FLOOR; Material: Generell Gulv 300 mm
Pset_QuantityTakeOff - Reference: 250 Ny Generisk dekke 300 mm; sets with these values: 2
Pset_SlabCommon - IsExternal: no; LoadBearing: no; PitchAngle: 0 deg; Reference: 250 Ny Generisk dekke 300 mm
Name (Floor:250 Ny Generisk dekke 300 mm:...)
4212801
4258659
4286164

# IfcSlab: Floor:TEKNISK SKILLE, Floor:TEKNISK SKILLE:2542473
In: TEKNISK SKILLE
Type - PredefinedType: FLOOR; Material: Gips 12.5 mm, Gips 12.5 mm, Isolasjon bløt 200 mm, Gips 12.5 mm, Gips 12.5 mm
Pset_QuantityTakeOff - Reference: TEKNISK SKILLE; sets with these values: 2
Pset_SlabCommon - IsExternal: no; LoadBearing: no; PitchAngle: 0 deg; Reference: TEKNISK SKILLE

# IfcSlab: Monolithic Landing:300 mm Thickness, Cast-In-Place Stair:Stair:4303045 Landing 1
In: PLAN U1
Type - PredefinedType: LANDING
Material: <Unnamed>
Pset_QuantityTakeOff - Reference: 300 mm Thickness; sets with these values: 2
Pset_SlabCommon - IsExternal: no; PitchAngle: 0 deg; Reference: 300 mm Thickness

# IfcStair: Cast-In-Place Stair:Cast-In-Place Stair, Cast-In-Place Stair:Stair:4303045
In: PLAN U1
ShapeType: HALF_TURN_STAIR
Pset_QuantityTakeOff - Reference: Cast-In-Place Stair
Pset_StairCommon - IsExternal: no; Reference: Cast-In-Place Stair; NumberOfRiser: 19; NumberOfTreads: 17; RiserHeight: 173.684 mm; TreadLength: 270 mm

# IfcStair: Precast Stair:Precast Stair, Precast Stair:Stair:1934253
In: PLAN 01
ShapeType: STRAIGHT_RUN_STAIR
Pset_QuantityTakeOff - Reference: Precast Stair
Pset_StairCommon - IsExternal: no; Reference: Precast Stair; NumberOfRiser: 8; NumberOfTreads: 7; RiserHeight: 167.5 mm; TreadLength: 250 mm

# IfcStairFlight: Monolithic Run:Monolithic Run (3)
Type - PredefinedType: STRAIGHT
Type - Pset_StairFlightCommon - NosingLength: 0 mm
Material: <Unnamed>
Pset_QuantityTakeOff - Reference: Monolithic Run
Pset_StairFlightCommon - Reference: Monolithic Run; WalkingLineOffset: 1.9685 mm
Name | In | NumberOfRiser = Pset_StairFlightCommon, NumberOfRiser | NumberOfTreads = Pset_StairFlightCommon, NumberOfTreads | RiserHeight (mm) | TreadLength (mm) | Pset_StairFlightCommon, RiserHeight (mm) | Pset_StairFlightCommon, TreadLength (mm) = TreadLengthAtOffset (mm) = TreadLengthAtInnerSide (mm)
Precast Stair:Stair:1934253 Run 1 | PLAN 01 | 8 | 7 | 0.549541 | 0.82021 | 167.5 | 250
Cast-In-Place Stair:Stair:4303045 Run 1 | PLAN U1 | 9 | 8 | 0.56983 | 0.885827 | 173.684 | 270
Cast-In-Place Stair:Stair:4303045 Run 2 | PLAN U1 | 10 | 9 | 0.56983 | 0.885827 | 173.684 | 270

# IfcWall: Basic Wall:230 Eksist. Yttervegg 260 mm, Basic Wall:230 Eksist. Yttervegg 260 mm:3616023
In: PLAN 03 (EKS. TAK)
Type - PredefinedType: STANDARD; Material: Beige Fasadeplater 10 mm, _Maling hvit 250 mm
Pset_QuantityTakeOff - Reference: 230 Eksist. Yttervegg 260 mm; sets with these values: 2
Pset_WallCommon - LoadBearing: no; IsExternal: yes; ExtendToStructure: yes; Reference: 230 Eksist. Yttervegg 260 mm

# IfcWall: Basic Wall:230 Eksist. yttervegg 160 mm (2)
Type - PredefinedType: STANDARD; Material: Beige Fasadeplater 160 mm
Pset_QuantityTakeOff - Reference: 230 Eksist. yttervegg 160 mm; sets with these values: 2
Pset_WallCommon - LoadBearing: no; IsExternal: yes; Reference: 230 Eksist. yttervegg 160 mm
Name (Basic Wall:230 Eksist. yttervegg 160 mm:...) | In | ExtendToStructure
1560120 | PLAN 02 | yes
1661942 | PLAN U1 | no

# IfcWall: Basic Wall:230 Eksist. yttervegg 200 mm (2)
Type - PredefinedType: STANDARD; Material: Beige Fasadeplater 10 mm, Eksist. vegg 190 mm, Gips 12 mm
Pset_QuantityTakeOff - Reference: 230 Eksist. yttervegg 200 mm; sets with these values: 2
Pset_WallCommon - LoadBearing: no; IsExternal: yes; ExtendToStructure: yes; Reference: 230 Eksist. yttervegg 200 mm
Name (Basic Wall:230 Eksist. yttervegg 200 mm:...) | In
1561549 | PLAN 01
3232485 | PLAN U1

# IfcWall: Basic Wall:230 Eksist. yttervegg 270 mm (3)
Type - PredefinedType: STANDARD; Material: Beige Fasadeplater 10 mm, Eksist. vegg 260 mm
Pset_QuantityTakeOff - Reference: 230 Eksist. yttervegg 270 mm; sets with these values: 2
Pset_WallCommon - LoadBearing: no; IsExternal: yes; Reference: 230 Eksist. yttervegg 270 mm
Name (Basic Wall:230 Eksist. yttervegg 270 mm:...) | In | ExtendToStructure
2286684 | PLAN 01 | no
2287371 | PLAN 01 | no
3620186 | PLAN 03 (EKS. TAK) | yes

# IfcWall: Basic Wall:230 Eksist. yttervegg 400 mm (3)
Type - PredefinedType: STANDARD; Material: Eksist. yttervegg 400 mm
Pset_QuantityTakeOff - Reference: 230 Eksist. yttervegg 400 mm; sets with these values: 2
Pset_WallCommon - LoadBearing: no; IsExternal: yes; Reference: 230 Eksist. yttervegg 400 mm
Name (Basic Wall:230 Eksist. yttervegg 400 mm:...) | In | ExtendToStructure
1611863 | PLAN 02 | yes
1662600 | PLAN U1 | yes
1662603 | PLAN U1 | no
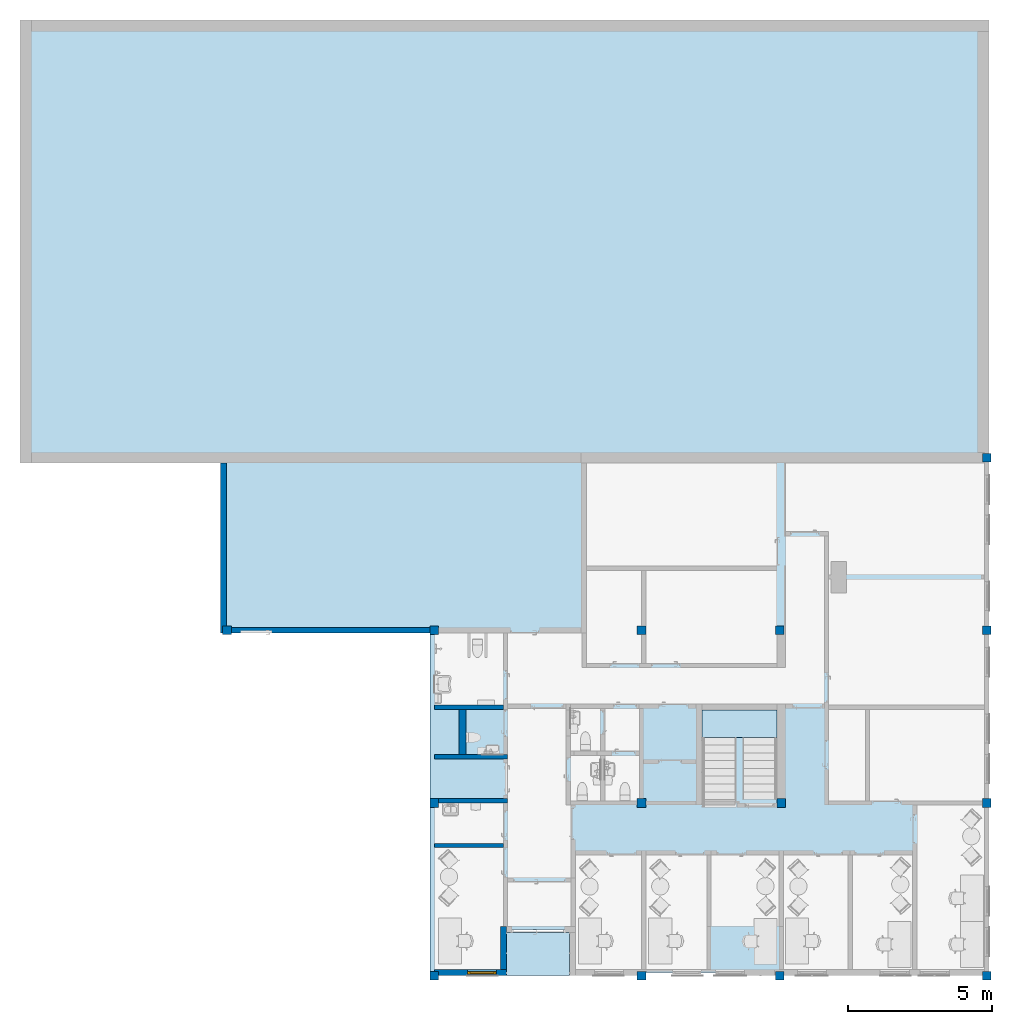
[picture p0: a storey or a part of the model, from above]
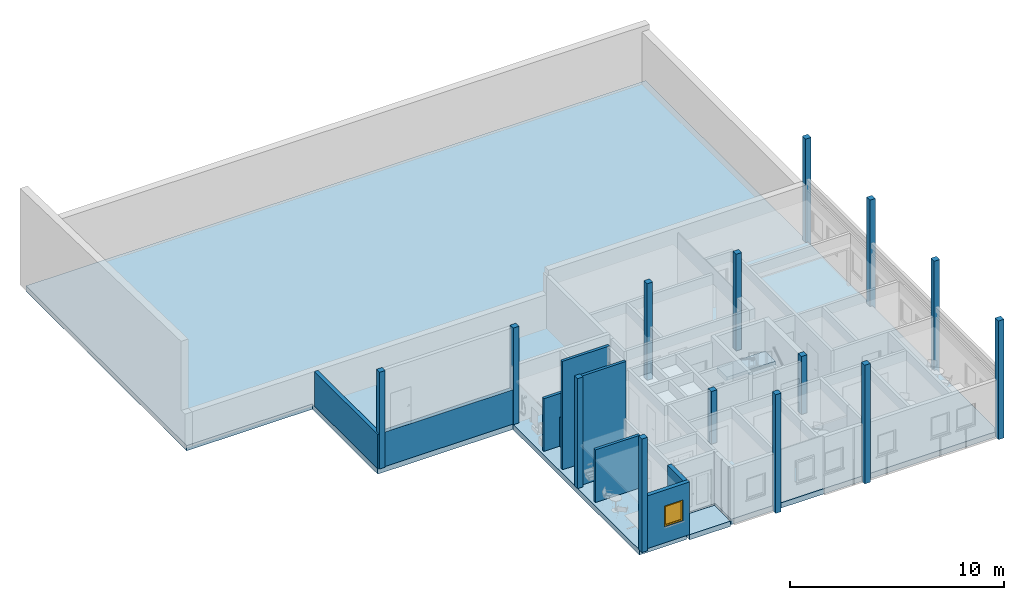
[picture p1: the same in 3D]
Properties of the parts of a building model (IFC2X3), part 4 of 4

# IfcWall: Basic Wall:230 Generisk yttervegg 360 mm (2)
Type - PredefinedType: STANDARD; Material: Eksist. yttervegg 360 mm
Pset_QuantityTakeOff - Reference: 230 Generisk yttervegg 360 mm; sets with these values: 2
Pset_WallCommon - LoadBearing: no; IsExternal: yes; Reference: 230 Generisk yttervegg 360 mm
Name (Basic Wall:230 Generisk yttervegg 360 mm:...) | In | ExtendToStructure
1660493 | PLAN 01 | yes
1662602 | PLAN U1 | no

# IfcWall: Basic Wall:240 Eksist. Innervegg 120 mm (2)
In: PLAN 02
Type - PredefinedType: STANDARD; Material: Eksist. vegg 120 mm
Pset_QuantityTakeOff - Reference: 240 Eksist. Innervegg 120 mm; sets with these values: 2
Pset_WallCommon - LoadBearing: no; IsExternal: yes; Reference: 240 Eksist. Innervegg 120 mm
Name (Basic Wall:240 Eksist. Innervegg 120 mm:...) | ExtendToStructure
1569810 | no
1931654 | yes

# IfcWall: Basic Wall:240 Eksist. Innervegg 150 mm (3)
Type - PredefinedType: STANDARD; Material: Eksist. vegg 150 mm
Pset_QuantityTakeOff - Reference: 240 Eksist. Innervegg 150 mm; sets with these values: 2
Pset_WallCommon - LoadBearing: no; IsExternal: yes; ExtendToStructure: yes; Reference: 240 Eksist. Innervegg 150 mm
Name (Basic Wall:240 Eksist. Innervegg 150 mm:...) | In
1568619 | PLAN 01
1665812 | PLAN U1
3629152 | TEKNISK SKILLE

# IfcWall: Basic Wall:240 Eksist. Innervegg 260 mm (3)
Type - PredefinedType: STANDARD; Material: Default Wall 260 mm
Pset_QuantityTakeOff - Reference: 240 Eksist. Innervegg 260 mm; sets with these values: 2
Pset_WallCommon - LoadBearing: no; IsExternal: yes; Reference: 240 Eksist. Innervegg 260 mm; ExtendToStructure: no
Name (Basic Wall:240 Eksist. Innervegg 260 mm:...) | In
1561262 | PLAN 01
3614905 | PLAN 01
3615704 | PLAN 03 (EKS. TAK)

# IfcWall: Basic Wall:240 Eksist. innervegg 200 mm (4)
Type - PredefinedType: STANDARD; Material: Eksist. vegg 200 mm
Pset_QuantityTakeOff - Reference: 240 Eksist. innervegg 200 mm; sets with these values: 2
Pset_WallCommon - IsExternal: no; LoadBearing: no; Reference: 240 Eksist. innervegg 200 mm
Name (Basic Wall:240 Eksist. innervegg 200 mm:...) | In | ExtendToStructure
1565979 | PLAN 02 | yes
1568726 | PLAN 01 | yes
1662727 | PLAN U1 | no
1662728 | PLAN 01 | yes

# IfcWall: Basic Wall:242 IV01 Innervegg 150 mm (10)
Type - PredefinedType: STANDARD; Material: Gips 12.5 mm, Gips 12.5 mm, Stender isolert 100 mm, Gips 12.5 mm, Gips 12.5 mm
Pset_QuantityTakeOff - Reference: 242 IV01 Innervegg 150 mm; sets with these values: 2
Pset_WallCommon - LoadBearing: no; IsExternal: yes; Reference: 242 IV01 Innervegg 150 mm
Name (Basic Wall:242 IV01 Innervegg 150 mm:...) | In | ExtendToStructure
1693446 | PLAN 01 | no
1694233 | PLAN 01 | yes
1694392 | PLAN 01 | yes
1779208 | PLAN 01 | yes
1909899 | PLAN 01 | no
2091934 | PLAN 01 | yes
2713464 | PLAN 02 | yes
2774076 | PLAN 02 | no
4310818 | PLAN 01 | yes
4929240 | PLAN 01 | no

# IfcWall: Basic Wall:242 IV01 påforingsvegg bad 50 mm, Basic Wall:242 IV01 påforingsvegg bad 50 mm:4006862
In: PLAN 02
Type - PredefinedType: STANDARD; Material: FIBO TRESPO BADEROMSPANELER GRØNN 10 mm, Våtromspanel 40 mm
Pset_QuantityTakeOff - Reference: 242 IV01 påforingsvegg bad 50 mm; sets with these values: 2
Pset_WallCommon - LoadBearing: no; IsExternal: yes; ExtendToStructure: yes; Reference: 242 IV01 påforingsvegg bad 50 mm

# IfcWall: Basic Wall:242 IV0X Innervegg 250 mm, Basic Wall:242 IV0X Innervegg 250 mm:1693832
In: PLAN 01
Type - PredefinedType: STANDARD; Material: Gips 12.5 mm, Gips 12.5 mm, Stender isolert 200 mm, Gips 12.5 mm, Gips 12.5 mm
Pset_QuantityTakeOff - Reference: 242 IV0X Innervegg 250 mm; sets with these values: 2
Pset_WallCommon - LoadBearing: no; IsExternal: yes; ExtendToStructure: yes; Reference: 242 IV0X Innervegg 250 mm

# IfcWall: Basic Wall:242 Innervegg 250 mm, Basic Wall:242 Innervegg 250 mm:2503287
In: PLAN 01
Type - PredefinedType: STANDARD; Material: Gips 12.5 mm, Gips 12.5 mm, Stender isolert 200 mm, Gips 12.5 mm, Gips 12.5 mm
Pset_QuantityTakeOff - Reference: 242 Innervegg 250 mm; sets with these values: 2
Pset_WallCommon - LoadBearing: no; IsExternal: yes; ExtendToStructure: yes; Reference: 242 Innervegg 250 mm

# IfcWallStandardCase: Basic Wall:230 Betong yttervegg 200 mm (4)
In: PLAN 01
Type - PredefinedType: STANDARD; Material: Betong plasstøpt 200 mm
Pset_QuantityTakeOff - Reference: 230 Betong yttervegg 200 mm; sets with these values: 2
Pset_WallCommon - LoadBearing: no; IsExternal: yes; ExtendToStructure: no; Reference: 230 Betong yttervegg 200 mm
Name (Basic Wall:230 Betong yttervegg 200 mm:...)
1561823
3388404
4542657
4542793

# IfcWallStandardCase: Basic Wall:230 Betong yttervegg 270 mm, Basic Wall:230 Betong yttervegg 270 mm:4542850
In: PLAN 01
Type - PredefinedType: STANDARD; Material: Betong plasstøpt 270 mm
Pset_QuantityTakeOff - Reference: 230 Betong yttervegg 270 mm; sets with these values: 2
Pset_WallCommon - LoadBearing: no; IsExternal: yes; ExtendToStructure: no; Reference: 230 Betong yttervegg 270 mm

# IfcWallStandardCase: Basic Wall:230 Betong yttervegg 360 mm, Basic Wall:230 Betong yttervegg 360 mm:1561653
In: PLAN 01
Type - PredefinedType: STANDARD; Material: Betong plasstøpt 360 mm
Pset_QuantityTakeOff - Reference: 230 Betong yttervegg 360 mm; sets with these values: 2
Pset_WallCommon - LoadBearing: no; IsExternal: yes; ExtendToStructure: no; Reference: 230 Betong yttervegg 360 mm

# IfcWallStandardCase: Basic Wall:230 Eksist. Yttervegg 260 mm, Basic Wall:230 Eksist. Yttervegg 260 mm:3621114
In: PLAN 01
Type - PredefinedType: STANDARD; Material: Beige Fasadeplater 10 mm, _Maling hvit 250 mm
Pset_QuantityTakeOff - Reference: 230 Eksist. Yttervegg 260 mm; sets with these values: 2
Pset_WallCommon - LoadBearing: no; IsExternal: yes; ExtendToStructure: no; Reference: 230 Eksist. Yttervegg 260 mm

# IfcWallStandardCase: Basic Wall:230 Eksist. yttervegg 160 mm, Basic Wall:230 Eksist. yttervegg 160 mm:3638899
In: PLAN 02
Type - PredefinedType: STANDARD; Material: Beige Fasadeplater 160 mm
Pset_QuantityTakeOff - Reference: 230 Eksist. yttervegg 160 mm; sets with these values: 2
Pset_WallCommon - LoadBearing: no; IsExternal: yes; Reference: 230 Eksist. yttervegg 160 mm; ExtendToStructure: no

# IfcWallStandardCase: Basic Wall:230 Eksist. yttervegg 200 mm (15)
Type - PredefinedType: STANDARD; Material: Beige Fasadeplater 10 mm, Eksist. vegg 190 mm, Gips 12 mm
Pset_QuantityTakeOff - Reference: 230 Eksist. yttervegg 200 mm; sets with these values: 2
Pset_WallCommon - IsExternal: yes; Reference: 230 Eksist. yttervegg 200 mm
Name (Basic Wall:230 Eksist. yttervegg 200 mm:...) | In | LoadBearing | ExtendToStructure
1559632 | PLAN 01 | no | yes
1660288 | PLAN 02 | no | yes
1661965 | PLAN U1 | no | yes
1662964 | PLAN U1 | no | no
1663050 | PLAN U1 | no | no
1663090 | PLAN U1 | no | yes
1663154 | PLAN U1 | no | yes
2279893 | PLAN 02 | yes | yes
2280052 | PLAN 02 | yes | yes
3363638 | PLAN 02 | yes | yes
3364316 | PLAN 02 | yes | yes
3364806 | PLAN 02 | yes | no
3614699 | PLAN 02 | yes | yes
3638904 | PLAN 02 | no | no
4452278 | PLAN U1 | no | no

# IfcWallStandardCase: Basic Wall:230 Eksist. yttervegg 270 mm (4)
Type - PredefinedType: STANDARD; Material: Beige Fasadeplater 10 mm, Eksist. vegg 260 mm
Pset_QuantityTakeOff - Reference: 230 Eksist. yttervegg 270 mm; sets with these values: 2
Pset_WallCommon - LoadBearing: no; IsExternal: yes; Reference: 230 Eksist. yttervegg 270 mm
Name (Basic Wall:230 Eksist. yttervegg 270 mm:...) | In | ExtendToStructure
2280199 | PLAN 03 (EKS. TAK) | yes
2287162 | PLAN 01 | no
3619293 | PLAN 03 (EKS. TAK) | yes
3620022 | PLAN 03 (EKS. TAK) | yes

# IfcWallStandardCase: Basic Wall:230 Eksist. yttervegg 400 mm (2)
Type - PredefinedType: STANDARD; Material: Eksist. yttervegg 400 mm
Pset_QuantityTakeOff - Reference: 230 Eksist. yttervegg 400 mm; sets with these values: 2
Pset_WallCommon - LoadBearing: no; IsExternal: yes; Reference: 230 Eksist. yttervegg 400 mm
Name (Basic Wall:230 Eksist. yttervegg 400 mm:...) | In | ExtendToStructure
1419800 | PLAN 02 | yes
1662599 | PLAN U1 | no

# IfcWallStandardCase: Basic Wall:230 Generisk yttervegg 200 mm Med fasadeplater (2)
In: PLAN 01
Type - PredefinedType: STANDARD; Material: Beige Fasadeplater 10 mm, _Maling hvit 190 mm, Gips 12 mm
Pset_QuantityTakeOff - Reference: 230 Generisk yttervegg 200 mm Med fasadeplater; sets with these values: 2
Pset_WallCommon - LoadBearing: no; IsExternal: yes; ExtendToStructure: yes; Reference: 230 Generisk yttervegg 200 mm Med fasadeplater
Name (Basic Wall:230 Generisk yttervegg 200 mm Med fasadeplater:...)
3291425
3291978

# IfcWallStandardCase: Basic Wall:230 Generisk yttervegg 200 mm, Gjentetting, Basic Wall:230 Generisk yttervegg 200 mm, Gjentetting:1832946
In: PLAN 01
Type - PredefinedType: STANDARD; Material: Lettklinker 188 mm, Gips 12 mm
Pset_QuantityTakeOff - Reference: 230 Generisk yttervegg 200 mm, Gjentetting; sets with these values: 2
Pset_WallCommon - LoadBearing: no; IsExternal: yes; ExtendToStructure: no; Reference: 230 Generisk yttervegg 200 mm, Gjentetting

# IfcWallStandardCase: Basic Wall:230 Generisk yttervegg 200 mm, Gjentetting 2 (2)
In: PLAN 01
Type - PredefinedType: STANDARD; Material: Lettklinker 200 mm
Pset_QuantityTakeOff - Reference: 230 Generisk yttervegg 200 mm, Gjentetting 2; sets with these values: 2
Pset_WallCommon - LoadBearing: no; IsExternal: yes; ExtendToStructure: yes; Reference: 230 Generisk yttervegg 200 mm, Gjentetting 2
Name (Basic Wall:230 Generisk yttervegg 200 mm, Gjentetting 2:...)
1756926
2428639

# IfcWallStandardCase: Basic Wall:230 Generisk yttervegg 200 mm, trekledning begge sider, Basic Wall:230 Generisk yttervegg 200 mm, trekledning begge sider:4287423
In: PLAN 01
Type - PredefinedType: STANDARD; Material: Panel 35 mm, Betong plasstøpt 150 mm, Panel 35 mm
Pset_QuantityTakeOff - Reference: 230 Generisk yttervegg 200 mm, trekledning begge sider; sets with these values: 2
Pset_WallCommon - LoadBearing: no; IsExternal: yes; ExtendToStructure: no; Reference: 230 Generisk yttervegg 200 mm, trekledning begge sider

# IfcWallStandardCase: Basic Wall:230 Generisk yttervegg 212 mm, Gjentetting, Basic Wall:230 Generisk yttervegg 212 mm, Gjentetting:1832947
In: PLAN 01
Type - PredefinedType: STANDARD; Material: Lettklinker 212 mm
Pset_QuantityTakeOff - Reference: 230 Generisk yttervegg 212 mm, Gjentetting; sets with these values: 2
Pset_WallCommon - LoadBearing: no; IsExternal: yes; ExtendToStructure: yes; Reference: 230 Generisk yttervegg 212 mm, Gjentetting

# IfcWallStandardCase: Basic Wall:230 Generisk yttervegg 300 mm, Bet. Ny (2)
In: PLAN 01
Type - PredefinedType: STANDARD; Material: Panel 35 mm, Betong plasstøpt 150 mm, Stender isolert 100 mm, Gips 12 mm
Pset_QuantityTakeOff - Reference: 230 Generisk yttervegg 300 mm, Bet. Ny; sets with these values: 2
Pset_WallCommon - LoadBearing: no; IsExternal: yes; ExtendToStructure: no; Reference: 230 Generisk yttervegg 300 mm, Bet. Ny
Name (Basic Wall:230 Generisk yttervegg 300 mm, Bet. Ny:...)
4285015
4285016

# IfcWallStandardCase: Basic Wall:230 Generisk yttervegg 300 mm, Ny (5)
In: PLAN 01
Type - PredefinedType: STANDARD; Material: Panel 35 mm, Stender isolert 250 mm, Gips 12 mm
Pset_QuantityTakeOff - Reference: 230 Generisk yttervegg 300 mm, Ny; sets with these values: 2
Pset_WallCommon - LoadBearing: no; IsExternal: yes; Reference: 230 Generisk yttervegg 300 mm, Ny
Name (Basic Wall:230 Generisk yttervegg 300 mm, Ny:...) | ExtendToStructure
3292839 | no
3684367 | yes
3684368 | yes
3684380 | no
4285017 | no

# IfcWallStandardCase: Basic Wall:230 Generisk yttervegg 360 mm (3)
Type - PredefinedType: STANDARD; Material: Eksist. yttervegg 360 mm
Pset_QuantityTakeOff - Reference: 230 Generisk yttervegg 360 mm; sets with these values: 2
Pset_WallCommon - LoadBearing: no; IsExternal: yes; ExtendToStructure: yes; Reference: 230 Generisk yttervegg 360 mm
Name (Basic Wall:230 Generisk yttervegg 360 mm:...) | In
1560366 | PLAN 02
1567579 | PLAN 01
2523900 | PLAN U1

# IfcWallStandardCase: Basic Wall:232 Sokkel Garasje 300 mm (3)
In: PLAN 01
Type - PredefinedType: STANDARD; Material: A_Material_Concrete_Insitu_Beam_Semi-Rough_Grey 35 mm, <Unnamed> 250 mm, Våtromspanel 15 mm
Pset_QuantityTakeOff - Reference: 232 Sokkel Garasje 300 mm; sets with these values: 2
Pset_WallCommon - LoadBearing: no; IsExternal: yes; ExtendToStructure: no; Reference: 232 Sokkel Garasje 300 mm
Name (Basic Wall:232 Sokkel Garasje 300 mm:...)
1706303
1706327
1933117

# IfcWallStandardCase: Basic Wall:232 Stålvegg 70 mm (5)
In: PLAN 03 (EKS. TAK)
Type - PredefinedType: STANDARD; Material: Aluminum fasade 70 mm
Type - Pset_WallCommon - ThermalTransmittance: 3285.71 kg/K/s3
Pset_QuantityTakeOff - Reference: 232 Stålvegg 70 mm; sets with these values: 2
Pset_WallCommon - LoadBearing: no; IsExternal: yes; ExtendToStructure: no; Reference: 232 Stålvegg 70 mm
Name (Basic Wall:232 Stålvegg 70 mm:...)
3633691
3633692
3633693
4511920
4511923

# IfcWallStandardCase: Basic Wall:232 Yttervegg Garasje 300 mm (3)
In: PLAN 01
Type - PredefinedType: STANDARD; Material: A_Material_Metal_Zinc_Cladding Panels_Wall_250 mm 35 mm, <Unnamed> 250 mm, Våtromspanel 15 mm
Pset_QuantityTakeOff - Reference: 232 Yttervegg Garasje 300 mm; sets with these values: 2
Pset_WallCommon - LoadBearing: no; IsExternal: yes; ExtendToStructure: no; Reference: 232 Yttervegg Garasje 300 mm
Name (Basic Wall:232 Yttervegg Garasje 300 mm:...)
3431174
3431542
3431818

# IfcWallStandardCase: Basic Wall:240 Eksist. Innervegg 120 mm (14)
Type - PredefinedType: STANDARD; Material: Eksist. vegg 120 mm
Pset_QuantityTakeOff - Reference: 240 Eksist. Innervegg 120 mm; sets with these values: 2
Pset_WallCommon - LoadBearing: no; IsExternal: yes; Reference: 240 Eksist. Innervegg 120 mm
Name (Basic Wall:240 Eksist. Innervegg 120 mm:...) | In | ExtendToStructure
1564863 | PLAN 02 | yes
1564871 | PLAN 02 | yes
1564881 | PLAN 02 | yes
1564891 | PLAN 02 | yes
1564899 | PLAN 02 | yes
1565001 | PLAN 02 | yes
1565828 | PLAN 02 | yes
1567790 | PLAN 01 | no
1569532 | PLAN 02 | yes
1680985 | PLAN 02 | yes
2015444 | PLAN 02 | no
2277897 | PLAN 02 | no
2277899 | PLAN 02 | no
4530160 | PLAN 02 | yes

# IfcWallStandardCase: Basic Wall:240 Eksist. Innervegg 150 mm (47)
Type - PredefinedType: STANDARD; Material: Eksist. vegg 150 mm
Pset_QuantityTakeOff - Reference: 240 Eksist. Innervegg 150 mm; sets with these values: 2
Pset_WallCommon - LoadBearing: no; IsExternal: yes; Reference: 240 Eksist. Innervegg 150 mm
Name (Basic Wall:240 Eksist. Innervegg 150 mm:...) | In | ExtendToStructure
1563100 | PLAN 01 | yes
1565698 | PLAN 02 | no
1567438 | PLAN 01 | no
1567744 | PLAN 01 | yes
1567754 | PLAN 01 | yes
1567802 | PLAN 01 | yes
1568339 | PLAN 01 | yes
1568413 | PLAN 01 | yes
1663551 | PLAN U1 | no
1663662 | PLAN U1 | no
1663732 | PLAN U1 | yes
1663937 | PLAN U1 | yes
1664020 | PLAN U1 | no
1664150 | PLAN U1 | no
1664265 | PLAN U1 | no
1664372 | PLAN U1 | no
1664666 | PLAN U1 | no
1664714 | PLAN U1 | no
1664842 | PLAN U1 | no
1664914 | PLAN U1 | no
1665077 | PLAN U1 | no
1665219 | PLAN U1 | no
1665334 | PLAN U1 | no
1665434 | PLAN U1 | no
1665636 | PLAN U1 | no
1665728 | PLAN U1 | no
1665974 | PLAN U1 | no
1668526 | PLAN U1 | no
1669271 | PLAN U1 | no
1669362 | PLAN U1 | no
1669977 | PLAN U1 | no
1692969 | PLAN 01 | yes
1937690 | PLAN U1 | no
2110444 | PLAN U1 | no
2254909 | PLAN U1 | no
2427362 | PLAN U1 | no
2520849 | PLAN 01 | no
2707028 | PLAN U1 | no
2716671 | PLAN U1 | no
3253616 | PLAN U1 | no
3253624 | PLAN U1 | no
4083603 | PLAN 01 | yes
4268944 | PLAN U1 | no
4401130 | PLAN U1 | no
4452275 | PLAN U1 | no
4452276 | PLAN U1 | no
4452299 | PLAN U1 | no

# IfcWallStandardCase: Basic Wall:240 Eksist. innervegg 200 mm (10)
Type - PredefinedType: STANDARD; Material: Eksist. vegg 200 mm
Pset_QuantityTakeOff - Reference: 240 Eksist. innervegg 200 mm; sets with these values: 2
Pset_WallCommon - IsExternal: no; LoadBearing: no; Reference: 240 Eksist. innervegg 200 mm
Name (Basic Wall:240 Eksist. innervegg 200 mm:...) | In | ExtendToStructure
1565210 | PLAN 02 | yes
1565356 | PLAN 02 | yes
1570622 | PLAN 02 | yes
1661944 | PLAN U1 | no
1661945 | PLAN U1 | no
1661947 | PLAN U1 | no
1671144 | PLAN U1 | yes
1671288 | PLAN U1 | no
1947743 | PLAN U1 | no
1947961 | PLAN 02 | yes

# IfcWallStandardCase: Basic Wall:240 Eksist. innervegg 300 mm (3)
Type - PredefinedType: STANDARD; Material: <Unnamed> 300 mm
Pset_QuantityTakeOff - Reference: 240 Eksist. innervegg 300 mm; sets with these values: 2
Pset_WallCommon - IsExternal: no; LoadBearing: no; Reference: 240 Eksist. innervegg 300 mm
Name (Basic Wall:240 Eksist. innervegg 300 mm:...) | In | ExtendToStructure
1565099 | PLAN 02 | yes
1661943 | PLAN U1 | no
1661946 | PLAN U1 | no

# IfcWallStandardCase: Basic Wall:240 Innervegg betong 150 mm (3)
In: PLAN U1
Type - PredefinedType: STANDARD; Material: Betong plasstøpt 150 mm
Pset_QuantityTakeOff - Reference: 240 Innervegg betong 150 mm; sets with these values: 2
Pset_WallCommon - IsExternal: no; LoadBearing: no; ExtendToStructure: yes; Reference: 240 Innervegg betong 150 mm
Name (Basic Wall:240 Innervegg betong 150 mm:...)
1697543
1801910
2265175

# IfcWallStandardCase: Basic Wall:242 Baderomsplater BLÅ (4)
In: PLAN 01
Type - PredefinedType: STANDARD; Material: FIBO TRESPO BADEROMSPANELER BLÅ 10 mm
Pset_QuantityTakeOff - Reference: 242 Baderomsplater BLÅ; sets with these values: 2
Pset_WallCommon - LoadBearing: no; IsExternal: yes; ExtendToStructure: no; Reference: 242 Baderomsplater BLÅ
Name (Basic Wall:242 Baderomsplater BLÅ:...)
4251768
4251857
4252112
4252344

# IfcWallStandardCase: Basic Wall:242 Baderomsplater beige (4)
In: PLAN 01
Type - PredefinedType: STANDARD; Material: FIBO TRESPO BADEROMSPANELER Beige 10 mm
Pset_QuantityTakeOff - Reference: 242 Baderomsplater beige; sets with these values: 2
Pset_WallCommon - LoadBearing: no; IsExternal: yes; ExtendToStructure: no; Reference: 242 Baderomsplater beige
Name (Basic Wall:242 Baderomsplater beige:...)
4908793
4909032
4909293
4909493

# IfcWallStandardCase: Basic Wall:242 Baderomsplater grønn (9)
Type - PredefinedType: STANDARD; Material: FIBO TRESPO BADEROMSPANELER GRØNN 10 mm
Pset_QuantityTakeOff - Reference: 242 Baderomsplater grønn; sets with these values: 2
Pset_WallCommon - LoadBearing: no; IsExternal: yes; Reference: 242 Baderomsplater grønn
Name (Basic Wall:242 Baderomsplater grønn:...) | In | ExtendToStructure
4006138 | PLAN 02 | yes
4006324 | PLAN 02 | yes
4007238 | PLAN 02 | yes
4007394 | PLAN 02 | yes
4007537 | PLAN 02 | no
4007853 | PLAN 02 | yes
4007854 | PLAN 01 | no
4251966 | PLAN 01 | no
4252020 | PLAN 01 | no

# IfcWallStandardCase: Basic Wall:242 IV01 Innervegg 150 mm (75)
Type - PredefinedType: STANDARD; Material: Gips 12.5 mm, Gips 12.5 mm, Stender isolert 100 mm, Gips 12.5 mm, Gips 12.5 mm
Pset_QuantityTakeOff - Reference: 242 IV01 Innervegg 150 mm; sets with these values: 2
Pset_WallCommon - LoadBearing: no; IsExternal: yes; Reference: 242 IV01 Innervegg 150 mm
Name (Basic Wall:242 IV01 Innervegg 150 mm:...) | In | ExtendToStructure
1680579 | PLAN 01 | yes
1680618 | PLAN 01 | yes
1693647 | PLAN 01 | no
1693949 | PLAN 01 | yes
1694109 | PLAN 01 | no
1694614 | PLAN 01 | yes
1696794 | PLAN 01 | yes
1699181 | PLAN 01 | no
1700727 | PLAN 02 | yes
1749680 | PLAN 01 | yes
1750825 | PLAN 01 | yes
1753785 | PLAN 01 | yes
1784289 | PLAN 01 | yes
1817824 | PLAN 01 | yes
1817889 | PLAN 01 | yes
1818395 | PLAN 01 | yes
1832584 | PLAN 01 | yes
1891177 | PLAN 01 | no
1899421 | PLAN 01 | yes
1908905 | PLAN 01 | yes
1909550 | PLAN 01 | yes
1909955 | PLAN 01 | yes
2043622 | PLAN 01 | yes
2252091 | PLAN U1 | no
2256378 | PLAN 01 | yes
2256399 | PLAN 01 | yes
2512178 | PLAN 01 | no
2519548 | PLAN 01 | yes
2519551 | PLAN 01 | yes
2548162 | PLAN 01 | yes
2669805 | PLAN 01 | yes
2669828 | PLAN 01 | yes
2708092 | PLAN U1 | no
2710856 | PLAN U1 | no
2712803 | PLAN 02 | yes
2713463 | PLAN 02 | no
2713489 | PLAN 02 | yes
2713492 | PLAN 02 | yes
2713493 | PLAN 02 | no
2713499 | PLAN 02 | yes
2713500 | PLAN 02 | yes
2713878 | PLAN 02 | yes
2713906 | PLAN 02 | yes
2722133 | PLAN 02 | yes
2722191 | PLAN 02 | yes
2722991 | PLAN 02 | yes
2722992 | PLAN 02 | yes
2770673 | PLAN 01 | yes
2770674 | PLAN 01 | yes
2770675 | PLAN 01 | yes
2791517 | PLAN 01 | yes
2791549 | PLAN 01 | yes
2852849 | PLAN 01 | yes
3486303 | PLAN 01 | no
3486442 | PLAN 01 | no
3486516 | PLAN 01 | no
3670600 | PLAN 01 | yes
3795245 | PLAN 01 | no
3806583 | PLAN 01 | no
3809019 | PLAN 02 | yes
4166217 | PLAN U1 | no
4166255 | PLAN U1 | yes
4166369 | PLAN U1 | yes
4263026 | PLAN 01 | yes
4263093 | PLAN 01 | yes
4263197 | PLAN 01 | yes
4263263 | PLAN 01 | yes
4263329 | PLAN 01 | yes
4267994 | PLAN 01 | no
4305922 | PLAN 02 | yes
4306767 | PLAN 02 | yes
4347421 | PLAN U1 | no
4347791 | PLAN U1 | no
5012426 | PLAN U1 | no
5012466 | PLAN U1 | no

# IfcWallStandardCase: Basic Wall:242 IV01 Innervegg 150 mm, m/Gips på enden (3)
Type - PredefinedType: STANDARD; Material: Gips 12.5 mm, Gips 12.5 mm, Stender isolert 100 mm, Gips 12.5 mm, Gips 12.5 mm
Pset_QuantityTakeOff - Reference: 242 IV01 Innervegg 150 mm, m/Gips på enden; sets with these values: 2
Pset_WallCommon - LoadBearing: no; IsExternal: yes; ExtendToStructure: yes; Reference: 242 IV01 Innervegg 150 mm, m/Gips på enden
Name (Basic Wall:242 IV01 Innervegg 150 mm, m/Gips på enden:...) | In
1917368 | PLAN 01
2727514 | PLAN 02
4115192 | PLAN 01

# IfcWallStandardCase: Basic Wall:242 IV01 påforingsvegg bad 50 mm (4)
In: PLAN 02
Type - PredefinedType: STANDARD; Material: FIBO TRESPO BADEROMSPANELER GRØNN 10 mm, Våtromspanel 40 mm
Pset_QuantityTakeOff - Reference: 242 IV01 påforingsvegg bad 50 mm; sets with these values: 2
Pset_WallCommon - LoadBearing: no; IsExternal: yes; ExtendToStructure: yes; Reference: 242 IV01 påforingsvegg bad 50 mm
Name (Basic Wall:242 IV01 påforingsvegg bad 50 mm:...)
4005717
4005969
4007851
4007852

# IfcWallStandardCase: Basic Wall:242 IV0X Innervegg 250 mm, Basic Wall:242 IV0X Innervegg 250 mm:3713777
In: PLAN U1
Type - PredefinedType: STANDARD; Material: Gips 12.5 mm, Gips 12.5 mm, Stender isolert 200 mm, Gips 12.5 mm, Gips 12.5 mm
Pset_QuantityTakeOff - Reference: 242 IV0X Innervegg 250 mm; sets with these values: 2
Pset_WallCommon - LoadBearing: no; IsExternal: yes; ExtendToStructure: no; Reference: 242 IV0X Innervegg 250 mm

# IfcWallStandardCase: Basic Wall:242 Innervegg 120 mm (7)
Type - PredefinedType: STANDARD; Material: Gips 12.5 mm, Gips 12.5 mm, Stender isolert 70 mm, Gips 12.5 mm, Gips 12.5 mm
Pset_QuantityTakeOff - Reference: 242 Innervegg 120 mm; sets with these values: 2
Pset_WallCommon - LoadBearing: no; IsExternal: yes; Reference: 242 Innervegg 120 mm
Name (Basic Wall:242 Innervegg 120 mm:...) | In | ExtendToStructure
1701512 | PLAN 02 | no
1871471 | PLAN 02 | no
1911212 | PLAN 02 | no
2011244 | PLAN 02 | no
2288316 | PLAN 01 | yes
2288338 | PLAN 01 | yes
4943380 | PLAN 02 | yes

# IfcWallStandardCase: Basic Wall:242 Innervegg 250 mm (3)
Type - PredefinedType: STANDARD; Material: Gips 12.5 mm, Gips 12.5 mm, Stender isolert 200 mm, Gips 12.5 mm, Gips 12.5 mm
Pset_QuantityTakeOff - Reference: 242 Innervegg 250 mm; sets with these values: 2
Pset_WallCommon - LoadBearing: no; IsExternal: yes; ExtendToStructure: yes; Reference: 242 Innervegg 250 mm
Name (Basic Wall:242 Innervegg 250 mm:...) | In
1919789 | PLAN 01
2713488 | PLAN 02
2774075 | PLAN 02

# IfcWallStandardCase: Basic Wall:242 Skjørt 150 mm, Basic Wall:242 Skjørt 150 mm:3787834
In: PLAN 01
Type - PredefinedType: STANDARD; Material: Gips 12.5 mm, Gips 12.5 mm, Stender isolert 100 mm, Gips 12.5 mm, Gips 12.5 mm
Pset_QuantityTakeOff - Reference: 242 Skjørt 150 mm; sets with these values: 2
Pset_WallCommon - LoadBearing: no; IsExternal: yes; ExtendToStructure: no; Reference: 242 Skjørt 150 mm

# IfcWallStandardCase: Basic Wall:Betongdrager, Basic Wall:Betongdrager:2468408
In: PLAN 02
Type - PredefinedType: STANDARD; Material: Betong plasstøpt 300 mm
Pset_QuantityTakeOff - Reference: Betongdrager; sets with these values: 2
Pset_WallCommon - LoadBearing: no; IsExternal: yes; ExtendToStructure: yes; Reference: Betongdrager

# IfcWallStandardCase: Basic Wall:Fendring farge 1 (36)
In: PLAN 01
Type - PredefinedType: STANDARD; Material: Fendring Farge 1 10 mm
Pset_QuantityTakeOff - Reference: Fendring farge 1; sets with these values: 2
Pset_WallCommon - LoadBearing: no; IsExternal: yes; ExtendToStructure: no; Reference: Fendring farge 1
Name (Basic Wall:Fendring farge 1:...)
2524842
2525031
2525136
2525546
2525732
2526348
4042606
4043053
4043084
4043217
4043255
4049918
4049974
4071269
4071375
4071466
4254177
4254614
4254820
4255075
4255172
4255267
4255382
4255495
4255621
4255706
4255792
4255851
4255889
4255987
4256453
4256633
4256768
4257218
4257331
4257501

# IfcWallStandardCase: Basic Wall:Fendring type 2 (10)
In: PLAN 01
Type - PredefinedType: STANDARD; Material: Ask 12 mm
Pset_QuantityTakeOff - Reference: Fendring type 2; sets with these values: 2
Pset_WallCommon - LoadBearing: no; IsExternal: yes; Reference: Fendring type 2
Name (Basic Wall:Fendring type 2:...) | ExtendToStructure
2522644 | no
2522912 | no
2523003 | no
2523086 | no
2523299 | yes
2548637 | yes
2548803 | yes
2548896 | yes
4071576 | no
4320711 | no

# IfcWallStandardCase: Basic Wall:VEGG Garasje (2)
In: PLAN 01
Type - PredefinedType: STANDARD; Material: Våtromspanel 15 mm
Pset_QuantityTakeOff - Reference: VEGG Garasje; sets with these values: 2
Pset_WallCommon - LoadBearing: no; IsExternal: yes; ExtendToStructure: no; Reference: VEGG Garasje
Name (Basic Wall:VEGG Garasje:...)
3945863
3946012

# IfcWallStandardCase: Basic Wall:VEGGPANEL TRE (8)
In: PLAN 01
Type - PredefinedType: STANDARD; Material: Ask 12 mm
Pset_QuantityTakeOff - Reference: VEGGPANEL TRE; sets with these values: 2
Pset_WallCommon - LoadBearing: no; IsExternal: yes; ExtendToStructure: no; Reference: VEGGPANEL TRE
Name (Basic Wall:VEGGPANEL TRE:...)
2646438
3598485
3599689
4126367
4144392
4144624
4144687
4279758

# IfcWindow: 234-Fast:4,5x21M (2)
In: PLAN 03 (EKS. TAK)
Type - ParameterTakesPrecedence: no; Sizeable: no; Material: NO_Glass, Vinduskarm
OverallHeight: 2110 mm; OverallWidth: 450 mm
Pset_QuantityTakeOff - Reference: 4,5x21M
Pset_WindowCommon - IsExternal: yes; Reference: 4,5x21M
Name (234-Fast:4,5x21M:...)
3362830
3363459

# IfcWindow: 234-Åpningsbart - Hor:10x16M (7)
In: PLAN 01
Type - ParameterTakesPrecedence: no; Sizeable: no; Material: Vinduskarm Hvit, NO_Glass
OverallHeight: 1610 mm; OverallWidth: 1010 mm
Pset_QuantityTakeOff - Reference: 10x16M
Pset_WindowCommon - IsExternal: yes; Reference: 10x16M
Name (234-Åpningsbart - Hor:10x16M:...)
3637888
3638022
3638120
3638121
3638387
3638500
3638519

# IfcWindow: 234-Åpningsbart - Hor:10x16M Tre (6)
In: PLAN 01
Type - ParameterTakesPrecedence: no; Sizeable: no; Material: vinduskarm- tre, NO_Glass
OverallHeight: 1610 mm; OverallWidth: 1010 mm
Pset_QuantityTakeOff - Reference: 10x16M Tre
Pset_WindowCommon - IsExternal: yes; Reference: 10x16M Tre
Name (234-Åpningsbart - Hor:10x16M Tre:...)
3293653
3293654
3684370
3684375
3687906
3687907

# IfcWindow: 234-Åpningsbart:10x12M (18)
Type - ParameterTakesPrecedence: no; Sizeable: no; Material: Vinduskarm Hvit, NO_Glass
OverallHeight: 1210 mm; OverallWidth: 1010 mm
Pset_QuantityTakeOff - Reference: 10x12M
Pset_WindowCommon - IsExternal: yes; Reference: 10x12M
Name (234-Åpningsbart:10x12M:...) | In
3659323 | PLAN 02
3659510 | PLAN 02
3659531 | PLAN 02
3659552 | PLAN 02
3659573 | PLAN 02
3659594 | PLAN 02
3659615 | PLAN 02
3659636 | PLAN 02
3659734 | PLAN 02
3660056 | PLAN 02
3660089 | PLAN 02
3660118 | PLAN 02
3660149 | PLAN 02
3660180 | PLAN 02
3660211 | PLAN 02
3660242 | PLAN 02
3673071 | PLAN 01
3673072 | PLAN 01

# IfcWindow: 234-Åpningsbart:10x12M Eks. (15)
In: PLAN U1
Type - ParameterTakesPrecedence: no; Sizeable: no; Material: Vinduskarm, NO_Glass
OverallHeight: 1210 mm; OverallWidth: 1010 mm
Pset_QuantityTakeOff - Reference: 10x12M Eks.
Pset_WindowCommon - IsExternal: yes; Reference: 10x12M Eks.
Name (234-Åpningsbart:10x12M Eks.:...)
1661948
1661949
1661950
1661951
1661952
1661953
1661954
1661955
1661956
1661957
1661958
1661959
1661961
1661962
4452277
